VERSION 5.7 ;
  NOWIREEXTENSIONATPIN ON ;
  DIVIDERCHAR "/" ;
  BUSBITCHARS "[]" ;
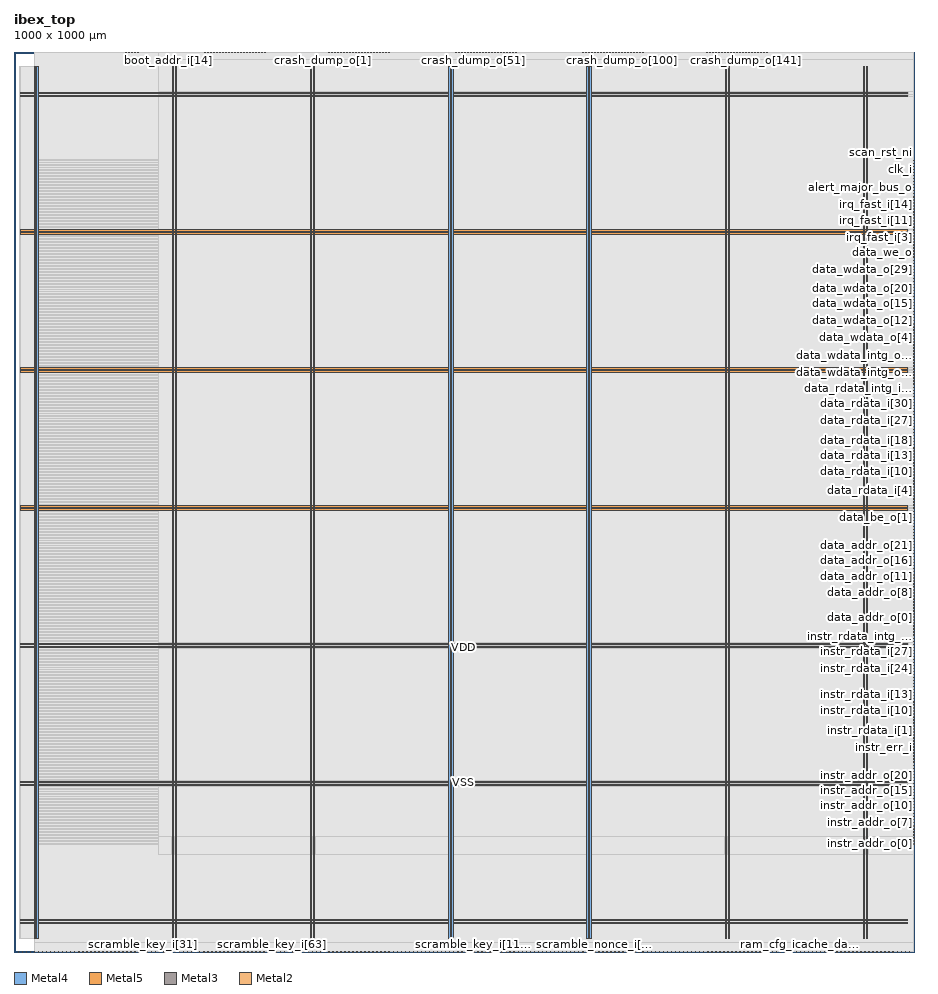
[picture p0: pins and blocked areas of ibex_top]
MACRO ibex_top
  CLASS BLOCK ;
  FOREIGN ibex_top ;
  ORIGIN 0.000 0.000 ;
  SIZE 1000.000 BY 1000.000 ;
  PIN VDD
    DIRECTION INOUT ;
    USE POWER ;
    PORT
      LAYER Metal4 ;
        RECT 22.240 15.380 23.840 984.220 ;
    END
    PORT
      LAYER Metal4 ;
        RECT 175.840 15.380 177.440 984.220 ;
    END
    PORT
      LAYER Metal4 ;
        RECT 329.440 15.380 331.040 984.220 ;
    END
    PORT
      LAYER Metal4 ;
        RECT 483.040 15.380 484.640 984.220 ;
    END
    PORT
      LAYER Metal4 ;
        RECT 636.640 15.380 638.240 984.220 ;
    END
    PORT
      LAYER Metal4 ;
        RECT 790.240 15.380 791.840 984.220 ;
    END
    PORT
      LAYER Metal4 ;
        RECT 943.840 15.380 945.440 984.220 ;
    END
    PORT
      LAYER Metal5 ;
        RECT 6.720 31.530 992.880 33.130 ;
    END
    PORT
      LAYER Metal5 ;
        RECT 6.720 184.710 992.880 186.310 ;
    END
    PORT
      LAYER Metal5 ;
        RECT 6.720 337.890 992.880 339.490 ;
    END
    PORT
      LAYER Metal5 ;
        RECT 6.720 491.070 992.880 492.670 ;
    END
    PORT
      LAYER Metal5 ;
        RECT 6.720 644.250 992.880 645.850 ;
    END
    PORT
      LAYER Metal5 ;
        RECT 6.720 797.430 992.880 799.030 ;
    END
    PORT
      LAYER Metal5 ;
        RECT 6.720 950.610 992.880 952.210 ;
    END
  END VDD
  PIN VSS
    DIRECTION INOUT ;
    USE GROUND ;
    PORT
      LAYER Metal4 ;
        RECT 25.540 15.380 27.140 984.220 ;
    END
    PORT
      LAYER Metal4 ;
        RECT 179.140 15.380 180.740 984.220 ;
    END
    PORT
      LAYER Metal4 ;
        RECT 332.740 15.380 334.340 984.220 ;
    END
    PORT
      LAYER Metal4 ;
        RECT 486.340 15.380 487.940 984.220 ;
    END
    PORT
      LAYER Metal4 ;
        RECT 639.940 15.380 641.540 984.220 ;
    END
    PORT
      LAYER Metal4 ;
        RECT 793.540 15.380 795.140 984.220 ;
    END
    PORT
      LAYER Metal4 ;
        RECT 947.140 15.380 948.740 984.220 ;
    END
    PORT
      LAYER Metal5 ;
        RECT 6.720 34.830 992.880 36.430 ;
    END
    PORT
      LAYER Metal5 ;
        RECT 6.720 188.010 992.880 189.610 ;
    END
    PORT
      LAYER Metal5 ;
        RECT 6.720 341.190 992.880 342.790 ;
    END
    PORT
      LAYER Metal5 ;
        RECT 6.720 494.370 992.880 495.970 ;
    END
    PORT
      LAYER Metal5 ;
        RECT 6.720 647.550 992.880 649.150 ;
    END
    PORT
      LAYER Metal5 ;
        RECT 6.720 800.730 992.880 802.330 ;
    END
    PORT
      LAYER Metal5 ;
        RECT 6.720 953.910 992.880 955.510 ;
    END
  END VSS
  PIN alert_major_bus_o
    DIRECTION OUTPUT ;
    USE SIGNAL ;
    ANTENNADIFFAREA 0.360800 ;
    PORT
      LAYER Metal3 ;
        RECT 999.440 848.960 1000.000 849.520 ;
    END
  END alert_major_bus_o
  PIN alert_major_internal_o
    DIRECTION OUTPUT ;
    USE SIGNAL ;
    ANTENNADIFFAREA 0.360800 ;
    PORT
      LAYER Metal3 ;
        RECT 999.440 852.320 1000.000 852.880 ;
    END
  END alert_major_internal_o
  PIN alert_minor_o
    DIRECTION OUTPUT ;
    USE SIGNAL ;
    ANTENNADIFFAREA 0.360800 ;
    PORT
      LAYER Metal3 ;
        RECT 999.440 855.680 1000.000 856.240 ;
    END
  END alert_minor_o
  PIN boot_addr_i[0]
    DIRECTION INPUT ;
    USE SIGNAL ;
    PORT
      LAYER Metal2 ;
        RECT 124.320 999.440 124.880 1000.000 ;
    END
  END boot_addr_i[0]
  PIN boot_addr_i[10]
    DIRECTION INPUT ;
    USE SIGNAL ;
    ANTENNAGATEAREA 0.396000 ;
    ANTENNADIFFAREA 0.410400 ;
    PORT
      LAYER Metal2 ;
        RECT 157.920 999.440 158.480 1000.000 ;
    END
  END boot_addr_i[10]
  PIN boot_addr_i[11]
    DIRECTION INPUT ;
    USE SIGNAL ;
    ANTENNAGATEAREA 0.396000 ;
    ANTENNADIFFAREA 0.410400 ;
    PORT
      LAYER Metal2 ;
        RECT 161.280 999.440 161.840 1000.000 ;
    END
  END boot_addr_i[11]
  PIN boot_addr_i[12]
    DIRECTION INPUT ;
    USE SIGNAL ;
    ANTENNAGATEAREA 0.396000 ;
    ANTENNADIFFAREA 0.410400 ;
    PORT
      LAYER Metal2 ;
        RECT 164.640 999.440 165.200 1000.000 ;
    END
  END boot_addr_i[12]
  PIN boot_addr_i[13]
    DIRECTION INPUT ;
    USE SIGNAL ;
    ANTENNAGATEAREA 0.396000 ;
    ANTENNADIFFAREA 0.410400 ;
    PORT
      LAYER Metal2 ;
        RECT 168.000 999.440 168.560 1000.000 ;
    END
  END boot_addr_i[13]
  PIN boot_addr_i[14]
    DIRECTION INPUT ;
    USE SIGNAL ;
    ANTENNAGATEAREA 0.396000 ;
    ANTENNADIFFAREA 0.410400 ;
    PORT
      LAYER Metal2 ;
        RECT 171.360 999.440 171.920 1000.000 ;
    END
  END boot_addr_i[14]
  PIN boot_addr_i[15]
    DIRECTION INPUT ;
    USE SIGNAL ;
    ANTENNAGATEAREA 0.396000 ;
    ANTENNADIFFAREA 0.410400 ;
    PORT
      LAYER Metal2 ;
        RECT 174.720 999.440 175.280 1000.000 ;
    END
  END boot_addr_i[15]
  PIN boot_addr_i[16]
    DIRECTION INPUT ;
    USE SIGNAL ;
    ANTENNAGATEAREA 0.396000 ;
    ANTENNADIFFAREA 0.410400 ;
    PORT
      LAYER Metal2 ;
        RECT 178.080 999.440 178.640 1000.000 ;
    END
  END boot_addr_i[16]
  PIN boot_addr_i[17]
    DIRECTION INPUT ;
    USE SIGNAL ;
    ANTENNAGATEAREA 0.396000 ;
    ANTENNADIFFAREA 0.410400 ;
    PORT
      LAYER Metal2 ;
        RECT 181.440 999.440 182.000 1000.000 ;
    END
  END boot_addr_i[17]
  PIN boot_addr_i[18]
    DIRECTION INPUT ;
    USE SIGNAL ;
    ANTENNAGATEAREA 0.396000 ;
    ANTENNADIFFAREA 0.410400 ;
    PORT
      LAYER Metal2 ;
        RECT 184.800 999.440 185.360 1000.000 ;
    END
  END boot_addr_i[18]
  PIN boot_addr_i[19]
    DIRECTION INPUT ;
    USE SIGNAL ;
    ANTENNAGATEAREA 0.396000 ;
    ANTENNADIFFAREA 0.410400 ;
    PORT
      LAYER Metal2 ;
        RECT 188.160 999.440 188.720 1000.000 ;
    END
  END boot_addr_i[19]
  PIN boot_addr_i[1]
    DIRECTION INPUT ;
    USE SIGNAL ;
    PORT
      LAYER Metal2 ;
        RECT 127.680 999.440 128.240 1000.000 ;
    END
  END boot_addr_i[1]
  PIN boot_addr_i[20]
    DIRECTION INPUT ;
    USE SIGNAL ;
    ANTENNAGATEAREA 0.396000 ;
    ANTENNADIFFAREA 0.410400 ;
    PORT
      LAYER Metal2 ;
        RECT 191.520 999.440 192.080 1000.000 ;
    END
  END boot_addr_i[20]
  PIN boot_addr_i[21]
    DIRECTION INPUT ;
    USE SIGNAL ;
    ANTENNAGATEAREA 0.396000 ;
    ANTENNADIFFAREA 0.410400 ;
    PORT
      LAYER Metal2 ;
        RECT 194.880 999.440 195.440 1000.000 ;
    END
  END boot_addr_i[21]
  PIN boot_addr_i[22]
    DIRECTION INPUT ;
    USE SIGNAL ;
    ANTENNAGATEAREA 0.396000 ;
    ANTENNADIFFAREA 0.410400 ;
    PORT
      LAYER Metal2 ;
        RECT 198.240 999.440 198.800 1000.000 ;
    END
  END boot_addr_i[22]
  PIN boot_addr_i[23]
    DIRECTION INPUT ;
    USE SIGNAL ;
    ANTENNAGATEAREA 0.396000 ;
    ANTENNADIFFAREA 0.410400 ;
    PORT
      LAYER Metal2 ;
        RECT 201.600 999.440 202.160 1000.000 ;
    END
  END boot_addr_i[23]
  PIN boot_addr_i[24]
    DIRECTION INPUT ;
    USE SIGNAL ;
    ANTENNAGATEAREA 0.396000 ;
    ANTENNADIFFAREA 0.410400 ;
    PORT
      LAYER Metal2 ;
        RECT 204.960 999.440 205.520 1000.000 ;
    END
  END boot_addr_i[24]
  PIN boot_addr_i[25]
    DIRECTION INPUT ;
    USE SIGNAL ;
    ANTENNAGATEAREA 0.396000 ;
    ANTENNADIFFAREA 0.410400 ;
    PORT
      LAYER Metal2 ;
        RECT 208.320 999.440 208.880 1000.000 ;
    END
  END boot_addr_i[25]
  PIN boot_addr_i[26]
    DIRECTION INPUT ;
    USE SIGNAL ;
    ANTENNAGATEAREA 0.396000 ;
    ANTENNADIFFAREA 0.410400 ;
    PORT
      LAYER Metal2 ;
        RECT 211.680 999.440 212.240 1000.000 ;
    END
  END boot_addr_i[26]
  PIN boot_addr_i[27]
    DIRECTION INPUT ;
    USE SIGNAL ;
    ANTENNAGATEAREA 0.396000 ;
    ANTENNADIFFAREA 0.410400 ;
    PORT
      LAYER Metal2 ;
        RECT 215.040 999.440 215.600 1000.000 ;
    END
  END boot_addr_i[27]
  PIN boot_addr_i[28]
    DIRECTION INPUT ;
    USE SIGNAL ;
    ANTENNAGATEAREA 0.396000 ;
    ANTENNADIFFAREA 0.410400 ;
    PORT
      LAYER Metal2 ;
        RECT 218.400 999.440 218.960 1000.000 ;
    END
  END boot_addr_i[28]
  PIN boot_addr_i[29]
    DIRECTION INPUT ;
    USE SIGNAL ;
    ANTENNAGATEAREA 0.396000 ;
    ANTENNADIFFAREA 0.410400 ;
    PORT
      LAYER Metal2 ;
        RECT 221.760 999.440 222.320 1000.000 ;
    END
  END boot_addr_i[29]
  PIN boot_addr_i[2]
    DIRECTION INPUT ;
    USE SIGNAL ;
    PORT
      LAYER Metal2 ;
        RECT 131.040 999.440 131.600 1000.000 ;
    END
  END boot_addr_i[2]
  PIN boot_addr_i[30]
    DIRECTION INPUT ;
    USE SIGNAL ;
    ANTENNAGATEAREA 0.396000 ;
    ANTENNADIFFAREA 0.410400 ;
    PORT
      LAYER Metal2 ;
        RECT 225.120 999.440 225.680 1000.000 ;
    END
  END boot_addr_i[30]
  PIN boot_addr_i[31]
    DIRECTION INPUT ;
    USE SIGNAL ;
    ANTENNAGATEAREA 0.396000 ;
    ANTENNADIFFAREA 0.410400 ;
    PORT
      LAYER Metal2 ;
        RECT 228.480 999.440 229.040 1000.000 ;
    END
  END boot_addr_i[31]
  PIN boot_addr_i[3]
    DIRECTION INPUT ;
    USE SIGNAL ;
    PORT
      LAYER Metal2 ;
        RECT 134.400 999.440 134.960 1000.000 ;
    END
  END boot_addr_i[3]
  PIN boot_addr_i[4]
    DIRECTION INPUT ;
    USE SIGNAL ;
    PORT
      LAYER Metal2 ;
        RECT 137.760 999.440 138.320 1000.000 ;
    END
  END boot_addr_i[4]
  PIN boot_addr_i[5]
    DIRECTION INPUT ;
    USE SIGNAL ;
    PORT
      LAYER Metal2 ;
        RECT 141.120 999.440 141.680 1000.000 ;
    END
  END boot_addr_i[5]
  PIN boot_addr_i[6]
    DIRECTION INPUT ;
    USE SIGNAL ;
    PORT
      LAYER Metal2 ;
        RECT 144.480 999.440 145.040 1000.000 ;
    END
  END boot_addr_i[6]
  PIN boot_addr_i[7]
    DIRECTION INPUT ;
    USE SIGNAL ;
    PORT
      LAYER Metal2 ;
        RECT 147.840 999.440 148.400 1000.000 ;
    END
  END boot_addr_i[7]
  PIN boot_addr_i[8]
    DIRECTION INPUT ;
    USE SIGNAL ;
    ANTENNAGATEAREA 0.396000 ;
    ANTENNADIFFAREA 0.410400 ;
    PORT
      LAYER Metal2 ;
        RECT 151.200 999.440 151.760 1000.000 ;
    END
  END boot_addr_i[8]
  PIN boot_addr_i[9]
    DIRECTION INPUT ;
    USE SIGNAL ;
    ANTENNAGATEAREA 0.396000 ;
    ANTENNADIFFAREA 0.410400 ;
    PORT
      LAYER Metal2 ;
        RECT 154.560 999.440 155.120 1000.000 ;
    END
  END boot_addr_i[9]
  PIN clk_i
    DIRECTION INPUT ;
    USE SIGNAL ;
    ANTENNAGATEAREA 9.476000 ;
    ANTENNADIFFAREA 0.820800 ;
    PORT
      LAYER Metal3 ;
        RECT 999.440 869.120 1000.000 869.680 ;
    END
  END clk_i
  PIN core_sleep_o
    DIRECTION OUTPUT ;
    USE SIGNAL ;
    ANTENNADIFFAREA 0.897600 ;
    PORT
      LAYER Metal3 ;
        RECT 999.440 859.040 1000.000 859.600 ;
    END
  END core_sleep_o
  PIN crash_dump_o[0]
    DIRECTION OUTPUT ;
    USE SIGNAL ;
    ANTENNADIFFAREA 0.897600 ;
    PORT
      LAYER Metal2 ;
        RECT 339.360 999.440 339.920 1000.000 ;
    END
  END crash_dump_o[0]
  PIN crash_dump_o[100]
    DIRECTION OUTPUT ;
    USE SIGNAL ;
    ANTENNADIFFAREA 0.897600 ;
    PORT
      LAYER Metal2 ;
        RECT 675.360 999.440 675.920 1000.000 ;
    END
  END crash_dump_o[100]
  PIN crash_dump_o[101]
    DIRECTION OUTPUT ;
    USE SIGNAL ;
    ANTENNADIFFAREA 0.897600 ;
    PORT
      LAYER Metal2 ;
        RECT 678.720 999.440 679.280 1000.000 ;
    END
  END crash_dump_o[101]
  PIN crash_dump_o[102]
    DIRECTION OUTPUT ;
    USE SIGNAL ;
    ANTENNADIFFAREA 0.897600 ;
    PORT
      LAYER Metal2 ;
        RECT 682.080 999.440 682.640 1000.000 ;
    END
  END crash_dump_o[102]
  PIN crash_dump_o[103]
    DIRECTION OUTPUT ;
    USE SIGNAL ;
    ANTENNADIFFAREA 0.897600 ;
    PORT
      LAYER Metal2 ;
        RECT 685.440 999.440 686.000 1000.000 ;
    END
  END crash_dump_o[103]
  PIN crash_dump_o[104]
    DIRECTION OUTPUT ;
    USE SIGNAL ;
    ANTENNADIFFAREA 0.897600 ;
    PORT
      LAYER Metal2 ;
        RECT 688.800 999.440 689.360 1000.000 ;
    END
  END crash_dump_o[104]
  PIN crash_dump_o[105]
    DIRECTION OUTPUT ;
    USE SIGNAL ;
    ANTENNADIFFAREA 0.897600 ;
    PORT
      LAYER Metal2 ;
        RECT 692.160 999.440 692.720 1000.000 ;
    END
  END crash_dump_o[105]
  PIN crash_dump_o[106]
    DIRECTION OUTPUT ;
    USE SIGNAL ;
    ANTENNADIFFAREA 0.897600 ;
    PORT
      LAYER Metal2 ;
        RECT 695.520 999.440 696.080 1000.000 ;
    END
  END crash_dump_o[106]
  PIN crash_dump_o[107]
    DIRECTION OUTPUT ;
    USE SIGNAL ;
    ANTENNADIFFAREA 0.897600 ;
    PORT
      LAYER Metal2 ;
        RECT 698.880 999.440 699.440 1000.000 ;
    END
  END crash_dump_o[107]
  PIN crash_dump_o[108]
    DIRECTION OUTPUT ;
    USE SIGNAL ;
    ANTENNADIFFAREA 0.897600 ;
    PORT
      LAYER Metal2 ;
        RECT 702.240 999.440 702.800 1000.000 ;
    END
  END crash_dump_o[108]
  PIN crash_dump_o[109]
    DIRECTION OUTPUT ;
    USE SIGNAL ;
    ANTENNADIFFAREA 0.897600 ;
    PORT
      LAYER Metal2 ;
        RECT 705.600 999.440 706.160 1000.000 ;
    END
  END crash_dump_o[109]
  PIN crash_dump_o[10]
    DIRECTION OUTPUT ;
    USE SIGNAL ;
    ANTENNADIFFAREA 0.897600 ;
    PORT
      LAYER Metal2 ;
        RECT 372.960 999.440 373.520 1000.000 ;
    END
  END crash_dump_o[10]
  PIN crash_dump_o[110]
    DIRECTION OUTPUT ;
    USE SIGNAL ;
    ANTENNADIFFAREA 0.897600 ;
    PORT
      LAYER Metal2 ;
        RECT 708.960 999.440 709.520 1000.000 ;
    END
  END crash_dump_o[110]
  PIN crash_dump_o[111]
    DIRECTION OUTPUT ;
    USE SIGNAL ;
    ANTENNADIFFAREA 0.897600 ;
    PORT
      LAYER Metal2 ;
        RECT 712.320 999.440 712.880 1000.000 ;
    END
  END crash_dump_o[111]
  PIN crash_dump_o[112]
    DIRECTION OUTPUT ;
    USE SIGNAL ;
    ANTENNADIFFAREA 0.897600 ;
    PORT
      LAYER Metal2 ;
        RECT 715.680 999.440 716.240 1000.000 ;
    END
  END crash_dump_o[112]
  PIN crash_dump_o[113]
    DIRECTION OUTPUT ;
    USE SIGNAL ;
    ANTENNADIFFAREA 0.897600 ;
    PORT
      LAYER Metal2 ;
        RECT 719.040 999.440 719.600 1000.000 ;
    END
  END crash_dump_o[113]
  PIN crash_dump_o[114]
    DIRECTION OUTPUT ;
    USE SIGNAL ;
    ANTENNADIFFAREA 0.897600 ;
    PORT
      LAYER Metal2 ;
        RECT 722.400 999.440 722.960 1000.000 ;
    END
  END crash_dump_o[114]
  PIN crash_dump_o[115]
    DIRECTION OUTPUT ;
    USE SIGNAL ;
    ANTENNADIFFAREA 0.897600 ;
    PORT
      LAYER Metal2 ;
        RECT 725.760 999.440 726.320 1000.000 ;
    END
  END crash_dump_o[115]
  PIN crash_dump_o[116]
    DIRECTION OUTPUT ;
    USE SIGNAL ;
    ANTENNADIFFAREA 0.897600 ;
    PORT
      LAYER Metal2 ;
        RECT 729.120 999.440 729.680 1000.000 ;
    END
  END crash_dump_o[116]
  PIN crash_dump_o[117]
    DIRECTION OUTPUT ;
    USE SIGNAL ;
    ANTENNADIFFAREA 0.897600 ;
    PORT
      LAYER Metal2 ;
        RECT 732.480 999.440 733.040 1000.000 ;
    END
  END crash_dump_o[117]
  PIN crash_dump_o[118]
    DIRECTION OUTPUT ;
    USE SIGNAL ;
    ANTENNADIFFAREA 0.897600 ;
    PORT
      LAYER Metal2 ;
        RECT 735.840 999.440 736.400 1000.000 ;
    END
  END crash_dump_o[118]
  PIN crash_dump_o[119]
    DIRECTION OUTPUT ;
    USE SIGNAL ;
    ANTENNADIFFAREA 0.897600 ;
    PORT
      LAYER Metal2 ;
        RECT 739.200 999.440 739.760 1000.000 ;
    END
  END crash_dump_o[119]
  PIN crash_dump_o[11]
    DIRECTION OUTPUT ;
    USE SIGNAL ;
    ANTENNADIFFAREA 0.897600 ;
    PORT
      LAYER Metal2 ;
        RECT 376.320 999.440 376.880 1000.000 ;
    END
  END crash_dump_o[11]
  PIN crash_dump_o[120]
    DIRECTION OUTPUT ;
    USE SIGNAL ;
    ANTENNADIFFAREA 0.897600 ;
    PORT
      LAYER Metal2 ;
        RECT 742.560 999.440 743.120 1000.000 ;
    END
  END crash_dump_o[120]
  PIN crash_dump_o[121]
    DIRECTION OUTPUT ;
    USE SIGNAL ;
    ANTENNADIFFAREA 0.897600 ;
    PORT
      LAYER Metal2 ;
        RECT 745.920 999.440 746.480 1000.000 ;
    END
  END crash_dump_o[121]
  PIN crash_dump_o[122]
    DIRECTION OUTPUT ;
    USE SIGNAL ;
    ANTENNADIFFAREA 0.897600 ;
    PORT
      LAYER Metal2 ;
        RECT 749.280 999.440 749.840 1000.000 ;
    END
  END crash_dump_o[122]
  PIN crash_dump_o[123]
    DIRECTION OUTPUT ;
    USE SIGNAL ;
    ANTENNADIFFAREA 0.897600 ;
    PORT
      LAYER Metal2 ;
        RECT 752.640 999.440 753.200 1000.000 ;
    END
  END crash_dump_o[123]
  PIN crash_dump_o[124]
    DIRECTION OUTPUT ;
    USE SIGNAL ;
    ANTENNADIFFAREA 0.897600 ;
    PORT
      LAYER Metal2 ;
        RECT 756.000 999.440 756.560 1000.000 ;
    END
  END crash_dump_o[124]
  PIN crash_dump_o[125]
    DIRECTION OUTPUT ;
    USE SIGNAL ;
    ANTENNADIFFAREA 0.897600 ;
    PORT
      LAYER Metal2 ;
        RECT 759.360 999.440 759.920 1000.000 ;
    END
  END crash_dump_o[125]
  PIN crash_dump_o[126]
    DIRECTION OUTPUT ;
    USE SIGNAL ;
    ANTENNADIFFAREA 0.897600 ;
    PORT
      LAYER Metal2 ;
        RECT 762.720 999.440 763.280 1000.000 ;
    END
  END crash_dump_o[126]
  PIN crash_dump_o[127]
    DIRECTION OUTPUT ;
    USE SIGNAL ;
    ANTENNADIFFAREA 0.897600 ;
    PORT
      LAYER Metal2 ;
        RECT 766.080 999.440 766.640 1000.000 ;
    END
  END crash_dump_o[127]
  PIN crash_dump_o[128]
    DIRECTION OUTPUT ;
    USE SIGNAL ;
    ANTENNADIFFAREA 0.360800 ;
    PORT
      LAYER Metal2 ;
        RECT 769.440 999.440 770.000 1000.000 ;
    END
  END crash_dump_o[128]
  PIN crash_dump_o[129]
    DIRECTION OUTPUT ;
    USE SIGNAL ;
    ANTENNADIFFAREA 0.897600 ;
    PORT
      LAYER Metal2 ;
        RECT 772.800 999.440 773.360 1000.000 ;
    END
  END crash_dump_o[129]
  PIN crash_dump_o[12]
    DIRECTION OUTPUT ;
    USE SIGNAL ;
    ANTENNADIFFAREA 0.897600 ;
    PORT
      LAYER Metal2 ;
        RECT 379.680 999.440 380.240 1000.000 ;
    END
  END crash_dump_o[12]
  PIN crash_dump_o[130]
    DIRECTION OUTPUT ;
    USE SIGNAL ;
    ANTENNADIFFAREA 0.897600 ;
    PORT
      LAYER Metal2 ;
        RECT 776.160 999.440 776.720 1000.000 ;
    END
  END crash_dump_o[130]
  PIN crash_dump_o[131]
    DIRECTION OUTPUT ;
    USE SIGNAL ;
    ANTENNADIFFAREA 0.897600 ;
    PORT
      LAYER Metal2 ;
        RECT 779.520 999.440 780.080 1000.000 ;
    END
  END crash_dump_o[131]
  PIN crash_dump_o[132]
    DIRECTION OUTPUT ;
    USE SIGNAL ;
    ANTENNADIFFAREA 0.897600 ;
    PORT
      LAYER Metal2 ;
        RECT 782.880 999.440 783.440 1000.000 ;
    END
  END crash_dump_o[132]
  PIN crash_dump_o[133]
    DIRECTION OUTPUT ;
    USE SIGNAL ;
    ANTENNADIFFAREA 0.897600 ;
    PORT
      LAYER Metal2 ;
        RECT 786.240 999.440 786.800 1000.000 ;
    END
  END crash_dump_o[133]
  PIN crash_dump_o[134]
    DIRECTION OUTPUT ;
    USE SIGNAL ;
    ANTENNADIFFAREA 0.897600 ;
    PORT
      LAYER Metal2 ;
        RECT 789.600 999.440 790.160 1000.000 ;
    END
  END crash_dump_o[134]
  PIN crash_dump_o[135]
    DIRECTION OUTPUT ;
    USE SIGNAL ;
    ANTENNADIFFAREA 0.897600 ;
    PORT
      LAYER Metal2 ;
        RECT 792.960 999.440 793.520 1000.000 ;
    END
  END crash_dump_o[135]
  PIN crash_dump_o[136]
    DIRECTION OUTPUT ;
    USE SIGNAL ;
    ANTENNADIFFAREA 0.897600 ;
    PORT
      LAYER Metal2 ;
        RECT 796.320 999.440 796.880 1000.000 ;
    END
  END crash_dump_o[136]
  PIN crash_dump_o[137]
    DIRECTION OUTPUT ;
    USE SIGNAL ;
    ANTENNADIFFAREA 0.897600 ;
    PORT
      LAYER Metal2 ;
        RECT 799.680 999.440 800.240 1000.000 ;
    END
  END crash_dump_o[137]
  PIN crash_dump_o[138]
    DIRECTION OUTPUT ;
    USE SIGNAL ;
    ANTENNADIFFAREA 0.897600 ;
    PORT
      LAYER Metal2 ;
        RECT 803.040 999.440 803.600 1000.000 ;
    END
  END crash_dump_o[138]
  PIN crash_dump_o[139]
    DIRECTION OUTPUT ;
    USE SIGNAL ;
    ANTENNADIFFAREA 0.897600 ;
    PORT
      LAYER Metal2 ;
        RECT 806.400 999.440 806.960 1000.000 ;
    END
  END crash_dump_o[139]
  PIN crash_dump_o[13]
    DIRECTION OUTPUT ;
    USE SIGNAL ;
    ANTENNADIFFAREA 0.897600 ;
    PORT
      LAYER Metal2 ;
        RECT 383.040 999.440 383.600 1000.000 ;
    END
  END crash_dump_o[13]
  PIN crash_dump_o[140]
    DIRECTION OUTPUT ;
    USE SIGNAL ;
    ANTENNADIFFAREA 0.897600 ;
    PORT
      LAYER Metal2 ;
        RECT 809.760 999.440 810.320 1000.000 ;
    END
  END crash_dump_o[140]
  PIN crash_dump_o[141]
    DIRECTION OUTPUT ;
    USE SIGNAL ;
    ANTENNADIFFAREA 0.897600 ;
    PORT
      LAYER Metal2 ;
        RECT 813.120 999.440 813.680 1000.000 ;
    END
  END crash_dump_o[141]
  PIN crash_dump_o[142]
    DIRECTION OUTPUT ;
    USE SIGNAL ;
    ANTENNADIFFAREA 0.897600 ;
    PORT
      LAYER Metal2 ;
        RECT 816.480 999.440 817.040 1000.000 ;
    END
  END crash_dump_o[142]
  PIN crash_dump_o[143]
    DIRECTION OUTPUT ;
    USE SIGNAL ;
    ANTENNADIFFAREA 0.897600 ;
    PORT
      LAYER Metal2 ;
        RECT 819.840 999.440 820.400 1000.000 ;
    END
  END crash_dump_o[143]
  PIN crash_dump_o[144]
    DIRECTION OUTPUT ;
    USE SIGNAL ;
    ANTENNADIFFAREA 0.897600 ;
    PORT
      LAYER Metal2 ;
        RECT 823.200 999.440 823.760 1000.000 ;
    END
  END crash_dump_o[144]
  PIN crash_dump_o[145]
    DIRECTION OUTPUT ;
    USE SIGNAL ;
    ANTENNADIFFAREA 0.897600 ;
    PORT
      LAYER Metal2 ;
        RECT 826.560 999.440 827.120 1000.000 ;
    END
  END crash_dump_o[145]
  PIN crash_dump_o[146]
    DIRECTION OUTPUT ;
    USE SIGNAL ;
    ANTENNADIFFAREA 0.897600 ;
    PORT
      LAYER Metal2 ;
        RECT 829.920 999.440 830.480 1000.000 ;
    END
  END crash_dump_o[146]
  PIN crash_dump_o[147]
    DIRECTION OUTPUT ;
    USE SIGNAL ;
    ANTENNADIFFAREA 0.897600 ;
    PORT
      LAYER Metal2 ;
        RECT 833.280 999.440 833.840 1000.000 ;
    END
  END crash_dump_o[147]
  PIN crash_dump_o[148]
    DIRECTION OUTPUT ;
    USE SIGNAL ;
    ANTENNADIFFAREA 0.897600 ;
    PORT
      LAYER Metal2 ;
        RECT 836.640 999.440 837.200 1000.000 ;
    END
  END crash_dump_o[148]
  PIN crash_dump_o[149]
    DIRECTION OUTPUT ;
    USE SIGNAL ;
    ANTENNADIFFAREA 0.897600 ;
    PORT
      LAYER Metal2 ;
        RECT 840.000 999.440 840.560 1000.000 ;
    END
  END crash_dump_o[149]
  PIN crash_dump_o[14]
    DIRECTION OUTPUT ;
    USE SIGNAL ;
    ANTENNADIFFAREA 0.897600 ;
    PORT
      LAYER Metal2 ;
        RECT 386.400 999.440 386.960 1000.000 ;
    END
  END crash_dump_o[14]
  PIN crash_dump_o[150]
    DIRECTION OUTPUT ;
    USE SIGNAL ;
    ANTENNADIFFAREA 0.897600 ;
    PORT
      LAYER Metal2 ;
        RECT 843.360 999.440 843.920 1000.000 ;
    END
  END crash_dump_o[150]
  PIN crash_dump_o[151]
    DIRECTION OUTPUT ;
    USE SIGNAL ;
    ANTENNADIFFAREA 0.897600 ;
    PORT
      LAYER Metal2 ;
        RECT 846.720 999.440 847.280 1000.000 ;
    END
  END crash_dump_o[151]
  PIN crash_dump_o[152]
    DIRECTION OUTPUT ;
    USE SIGNAL ;
    ANTENNADIFFAREA 0.897600 ;
    PORT
      LAYER Metal2 ;
        RECT 850.080 999.440 850.640 1000.000 ;
    END
  END crash_dump_o[152]
  PIN crash_dump_o[153]
    DIRECTION OUTPUT ;
    USE SIGNAL ;
    ANTENNADIFFAREA 0.897600 ;
    PORT
      LAYER Metal2 ;
        RECT 853.440 999.440 854.000 1000.000 ;
    END
  END crash_dump_o[153]
  PIN crash_dump_o[154]
    DIRECTION OUTPUT ;
    USE SIGNAL ;
    ANTENNADIFFAREA 0.897600 ;
    PORT
      LAYER Metal2 ;
        RECT 856.800 999.440 857.360 1000.000 ;
    END
  END crash_dump_o[154]
  PIN crash_dump_o[155]
    DIRECTION OUTPUT ;
    USE SIGNAL ;
    ANTENNADIFFAREA 0.897600 ;
    PORT
      LAYER Metal2 ;
        RECT 860.160 999.440 860.720 1000.000 ;
    END
  END crash_dump_o[155]
  PIN crash_dump_o[156]
    DIRECTION OUTPUT ;
    USE SIGNAL ;
    ANTENNADIFFAREA 0.897600 ;
    PORT
      LAYER Metal2 ;
        RECT 863.520 999.440 864.080 1000.000 ;
    END
  END crash_dump_o[156]
  PIN crash_dump_o[157]
    DIRECTION OUTPUT ;
    USE SIGNAL ;
    ANTENNADIFFAREA 0.897600 ;
    PORT
      LAYER Metal2 ;
        RECT 866.880 999.440 867.440 1000.000 ;
    END
  END crash_dump_o[157]
  PIN crash_dump_o[158]
    DIRECTION OUTPUT ;
    USE SIGNAL ;
    ANTENNADIFFAREA 0.897600 ;
    PORT
      LAYER Metal2 ;
        RECT 870.240 999.440 870.800 1000.000 ;
    END
  END crash_dump_o[158]
  PIN crash_dump_o[159]
    DIRECTION OUTPUT ;
    USE SIGNAL ;
    ANTENNADIFFAREA 0.897600 ;
    PORT
      LAYER Metal2 ;
        RECT 873.600 999.440 874.160 1000.000 ;
    END
  END crash_dump_o[159]
  PIN crash_dump_o[15]
    DIRECTION OUTPUT ;
    USE SIGNAL ;
    ANTENNADIFFAREA 0.897600 ;
    PORT
      LAYER Metal2 ;
        RECT 389.760 999.440 390.320 1000.000 ;
    END
  END crash_dump_o[15]
  PIN crash_dump_o[16]
    DIRECTION OUTPUT ;
    USE SIGNAL ;
    ANTENNADIFFAREA 0.897600 ;
    PORT
      LAYER Metal2 ;
        RECT 393.120 999.440 393.680 1000.000 ;
    END
  END crash_dump_o[16]
  PIN crash_dump_o[17]
    DIRECTION OUTPUT ;
    USE SIGNAL ;
    ANTENNADIFFAREA 0.897600 ;
    PORT
      LAYER Metal2 ;
        RECT 396.480 999.440 397.040 1000.000 ;
    END
  END crash_dump_o[17]
  PIN crash_dump_o[18]
    DIRECTION OUTPUT ;
    USE SIGNAL ;
    ANTENNADIFFAREA 0.897600 ;
    PORT
      LAYER Metal2 ;
        RECT 399.840 999.440 400.400 1000.000 ;
    END
  END crash_dump_o[18]
  PIN crash_dump_o[19]
    DIRECTION OUTPUT ;
    USE SIGNAL ;
    ANTENNADIFFAREA 0.897600 ;
    PORT
      LAYER Metal2 ;
        RECT 403.200 999.440 403.760 1000.000 ;
    END
  END crash_dump_o[19]
  PIN crash_dump_o[1]
    DIRECTION OUTPUT ;
    USE SIGNAL ;
    ANTENNADIFFAREA 0.897600 ;
    PORT
      LAYER Metal2 ;
        RECT 342.720 999.440 343.280 1000.000 ;
    END
  END crash_dump_o[1]
  PIN crash_dump_o[20]
    DIRECTION OUTPUT ;
    USE SIGNAL ;
    ANTENNADIFFAREA 0.897600 ;
    PORT
      LAYER Metal2 ;
        RECT 406.560 999.440 407.120 1000.000 ;
    END
  END crash_dump_o[20]
  PIN crash_dump_o[21]
    DIRECTION OUTPUT ;
    USE SIGNAL ;
    ANTENNADIFFAREA 0.897600 ;
    PORT
      LAYER Metal2 ;
        RECT 409.920 999.440 410.480 1000.000 ;
    END
  END crash_dump_o[21]
  PIN crash_dump_o[22]
    DIRECTION OUTPUT ;
    USE SIGNAL ;
    ANTENNADIFFAREA 0.897600 ;
    PORT
      LAYER Metal2 ;
        RECT 413.280 999.440 413.840 1000.000 ;
    END
  END crash_dump_o[22]
  PIN crash_dump_o[23]
    DIRECTION OUTPUT ;
    USE SIGNAL ;
    ANTENNADIFFAREA 0.897600 ;
    PORT
      LAYER Metal2 ;
        RECT 416.640 999.440 417.200 1000.000 ;
    END
  END crash_dump_o[23]
  PIN crash_dump_o[24]
    DIRECTION OUTPUT ;
    USE SIGNAL ;
    ANTENNADIFFAREA 0.897600 ;
    PORT
      LAYER Metal2 ;
        RECT 420.000 999.440 420.560 1000.000 ;
    END
  END crash_dump_o[24]
  PIN crash_dump_o[25]
    DIRECTION OUTPUT ;
    USE SIGNAL ;
    ANTENNADIFFAREA 0.897600 ;
    PORT
      LAYER Metal2 ;
        RECT 423.360 999.440 423.920 1000.000 ;
    END
  END crash_dump_o[25]
  PIN crash_dump_o[26]
    DIRECTION OUTPUT ;
    USE SIGNAL ;
    ANTENNADIFFAREA 0.897600 ;
    PORT
      LAYER Metal2 ;
        RECT 426.720 999.440 427.280 1000.000 ;
    END
  END crash_dump_o[26]
  PIN crash_dump_o[27]
    DIRECTION OUTPUT ;
    USE SIGNAL ;
    ANTENNADIFFAREA 0.897600 ;
    PORT
      LAYER Metal2 ;
        RECT 430.080 999.440 430.640 1000.000 ;
    END
  END crash_dump_o[27]
  PIN crash_dump_o[28]
    DIRECTION OUTPUT ;
    USE SIGNAL ;
    ANTENNADIFFAREA 0.897600 ;
    PORT
      LAYER Metal2 ;
        RECT 433.440 999.440 434.000 1000.000 ;
    END
  END crash_dump_o[28]
  PIN crash_dump_o[29]
    DIRECTION OUTPUT ;
    USE SIGNAL ;
    ANTENNADIFFAREA 0.897600 ;
    PORT
      LAYER Metal2 ;
        RECT 436.800 999.440 437.360 1000.000 ;
    END
  END crash_dump_o[29]
  PIN crash_dump_o[2]
    DIRECTION OUTPUT ;
    USE SIGNAL ;
    ANTENNADIFFAREA 0.897600 ;
    PORT
      LAYER Metal2 ;
        RECT 346.080 999.440 346.640 1000.000 ;
    END
  END crash_dump_o[2]
  PIN crash_dump_o[30]
    DIRECTION OUTPUT ;
    USE SIGNAL ;
    ANTENNADIFFAREA 0.897600 ;
    PORT
      LAYER Metal2 ;
        RECT 440.160 999.440 440.720 1000.000 ;
    END
  END crash_dump_o[30]
  PIN crash_dump_o[31]
    DIRECTION OUTPUT ;
    USE SIGNAL ;
    ANTENNADIFFAREA 0.897600 ;
    PORT
      LAYER Metal2 ;
        RECT 443.520 999.440 444.080 1000.000 ;
    END
  END crash_dump_o[31]
  PIN crash_dump_o[32]
    DIRECTION OUTPUT ;
    USE SIGNAL ;
    ANTENNADIFFAREA 0.897600 ;
    PORT
      LAYER Metal2 ;
        RECT 446.880 999.440 447.440 1000.000 ;
    END
  END crash_dump_o[32]
  PIN crash_dump_o[33]
    DIRECTION OUTPUT ;
    USE SIGNAL ;
    ANTENNADIFFAREA 0.897600 ;
    PORT
      LAYER Metal2 ;
        RECT 450.240 999.440 450.800 1000.000 ;
    END
  END crash_dump_o[33]
  PIN crash_dump_o[34]
    DIRECTION OUTPUT ;
    USE SIGNAL ;
    ANTENNADIFFAREA 0.897600 ;
    PORT
      LAYER Metal2 ;
        RECT 453.600 999.440 454.160 1000.000 ;
    END
  END crash_dump_o[34]
  PIN crash_dump_o[35]
    DIRECTION OUTPUT ;
    USE SIGNAL ;
    ANTENNADIFFAREA 0.897600 ;
    PORT
      LAYER Metal2 ;
        RECT 456.960 999.440 457.520 1000.000 ;
    END
  END crash_dump_o[35]
  PIN crash_dump_o[36]
    DIRECTION OUTPUT ;
    USE SIGNAL ;
    ANTENNADIFFAREA 0.897600 ;
    PORT
      LAYER Metal2 ;
        RECT 460.320 999.440 460.880 1000.000 ;
    END
  END crash_dump_o[36]
  PIN crash_dump_o[37]
    DIRECTION OUTPUT ;
    USE SIGNAL ;
    ANTENNADIFFAREA 0.897600 ;
    PORT
      LAYER Metal2 ;
        RECT 463.680 999.440 464.240 1000.000 ;
    END
  END crash_dump_o[37]
  PIN crash_dump_o[38]
    DIRECTION OUTPUT ;
    USE SIGNAL ;
    ANTENNADIFFAREA 0.897600 ;
    PORT
      LAYER Metal2 ;
        RECT 467.040 999.440 467.600 1000.000 ;
    END
  END crash_dump_o[38]
  PIN crash_dump_o[39]
    DIRECTION OUTPUT ;
    USE SIGNAL ;
    ANTENNADIFFAREA 0.897600 ;
    PORT
      LAYER Metal2 ;
        RECT 470.400 999.440 470.960 1000.000 ;
    END
  END crash_dump_o[39]
  PIN crash_dump_o[3]
    DIRECTION OUTPUT ;
    USE SIGNAL ;
    ANTENNADIFFAREA 0.897600 ;
    PORT
      LAYER Metal2 ;
        RECT 349.440 999.440 350.000 1000.000 ;
    END
  END crash_dump_o[3]
  PIN crash_dump_o[40]
    DIRECTION OUTPUT ;
    USE SIGNAL ;
    ANTENNADIFFAREA 0.897600 ;
    PORT
      LAYER Metal2 ;
        RECT 473.760 999.440 474.320 1000.000 ;
    END
  END crash_dump_o[40]
  PIN crash_dump_o[41]
    DIRECTION OUTPUT ;
    USE SIGNAL ;
    ANTENNADIFFAREA 0.897600 ;
    PORT
      LAYER Metal2 ;
        RECT 477.120 999.440 477.680 1000.000 ;
    END
  END crash_dump_o[41]
  PIN crash_dump_o[42]
    DIRECTION OUTPUT ;
    USE SIGNAL ;
    ANTENNADIFFAREA 0.897600 ;
    PORT
      LAYER Metal2 ;
        RECT 480.480 999.440 481.040 1000.000 ;
    END
  END crash_dump_o[42]
  PIN crash_dump_o[43]
    DIRECTION OUTPUT ;
    USE SIGNAL ;
    ANTENNADIFFAREA 0.897600 ;
    PORT
      LAYER Metal2 ;
        RECT 483.840 999.440 484.400 1000.000 ;
    END
  END crash_dump_o[43]
  PIN crash_dump_o[44]
    DIRECTION OUTPUT ;
    USE SIGNAL ;
    ANTENNADIFFAREA 0.897600 ;
    PORT
      LAYER Metal2 ;
        RECT 487.200 999.440 487.760 1000.000 ;
    END
  END crash_dump_o[44]
  PIN crash_dump_o[45]
    DIRECTION OUTPUT ;
    USE SIGNAL ;
    ANTENNADIFFAREA 0.897600 ;
    PORT
      LAYER Metal2 ;
        RECT 490.560 999.440 491.120 1000.000 ;
    END
  END crash_dump_o[45]
  PIN crash_dump_o[46]
    DIRECTION OUTPUT ;
    USE SIGNAL ;
    ANTENNADIFFAREA 0.897600 ;
    PORT
      LAYER Metal2 ;
        RECT 493.920 999.440 494.480 1000.000 ;
    END
  END crash_dump_o[46]
  PIN crash_dump_o[47]
    DIRECTION OUTPUT ;
    USE SIGNAL ;
    ANTENNADIFFAREA 0.897600 ;
    PORT
      LAYER Metal2 ;
        RECT 497.280 999.440 497.840 1000.000 ;
    END
  END crash_dump_o[47]
  PIN crash_dump_o[48]
    DIRECTION OUTPUT ;
    USE SIGNAL ;
    ANTENNADIFFAREA 0.897600 ;
    PORT
      LAYER Metal2 ;
        RECT 500.640 999.440 501.200 1000.000 ;
    END
  END crash_dump_o[48]
  PIN crash_dump_o[49]
    DIRECTION OUTPUT ;
    USE SIGNAL ;
    ANTENNADIFFAREA 0.897600 ;
    PORT
      LAYER Metal2 ;
        RECT 504.000 999.440 504.560 1000.000 ;
    END
  END crash_dump_o[49]
  PIN crash_dump_o[4]
    DIRECTION OUTPUT ;
    USE SIGNAL ;
    ANTENNADIFFAREA 0.897600 ;
    PORT
      LAYER Metal2 ;
        RECT 352.800 999.440 353.360 1000.000 ;
    END
  END crash_dump_o[4]
  PIN crash_dump_o[50]
    DIRECTION OUTPUT ;
    USE SIGNAL ;
    ANTENNADIFFAREA 0.897600 ;
    PORT
      LAYER Metal2 ;
        RECT 507.360 999.440 507.920 1000.000 ;
    END
  END crash_dump_o[50]
  PIN crash_dump_o[51]
    DIRECTION OUTPUT ;
    USE SIGNAL ;
    ANTENNADIFFAREA 0.897600 ;
    PORT
      LAYER Metal2 ;
        RECT 510.720 999.440 511.280 1000.000 ;
    END
  END crash_dump_o[51]
  PIN crash_dump_o[52]
    DIRECTION OUTPUT ;
    USE SIGNAL ;
    ANTENNADIFFAREA 0.897600 ;
    PORT
      LAYER Metal2 ;
        RECT 514.080 999.440 514.640 1000.000 ;
    END
  END crash_dump_o[52]
  PIN crash_dump_o[53]
    DIRECTION OUTPUT ;
    USE SIGNAL ;
    ANTENNADIFFAREA 0.897600 ;
    PORT
      LAYER Metal2 ;
        RECT 517.440 999.440 518.000 1000.000 ;
    END
  END crash_dump_o[53]
  PIN crash_dump_o[54]
    DIRECTION OUTPUT ;
    USE SIGNAL ;
    ANTENNADIFFAREA 0.897600 ;
    PORT
      LAYER Metal2 ;
        RECT 520.800 999.440 521.360 1000.000 ;
    END
  END crash_dump_o[54]
  PIN crash_dump_o[55]
    DIRECTION OUTPUT ;
    USE SIGNAL ;
    ANTENNADIFFAREA 0.897600 ;
    PORT
      LAYER Metal2 ;
        RECT 524.160 999.440 524.720 1000.000 ;
    END
  END crash_dump_o[55]
  PIN crash_dump_o[56]
    DIRECTION OUTPUT ;
    USE SIGNAL ;
    ANTENNADIFFAREA 0.897600 ;
    PORT
      LAYER Metal2 ;
        RECT 527.520 999.440 528.080 1000.000 ;
    END
  END crash_dump_o[56]
  PIN crash_dump_o[57]
    DIRECTION OUTPUT ;
    USE SIGNAL ;
    ANTENNADIFFAREA 0.897600 ;
    PORT
      LAYER Metal2 ;
        RECT 530.880 999.440 531.440 1000.000 ;
    END
  END crash_dump_o[57]
  PIN crash_dump_o[58]
    DIRECTION OUTPUT ;
    USE SIGNAL ;
    ANTENNADIFFAREA 0.897600 ;
    PORT
      LAYER Metal2 ;
        RECT 534.240 999.440 534.800 1000.000 ;
    END
  END crash_dump_o[58]
  PIN crash_dump_o[59]
    DIRECTION OUTPUT ;
    USE SIGNAL ;
    ANTENNADIFFAREA 0.897600 ;
    PORT
      LAYER Metal2 ;
        RECT 537.600 999.440 538.160 1000.000 ;
    END
  END crash_dump_o[59]
  PIN crash_dump_o[5]
    DIRECTION OUTPUT ;
    USE SIGNAL ;
    ANTENNADIFFAREA 0.897600 ;
    PORT
      LAYER Metal2 ;
        RECT 356.160 999.440 356.720 1000.000 ;
    END
  END crash_dump_o[5]
  PIN crash_dump_o[60]
    DIRECTION OUTPUT ;
    USE SIGNAL ;
    ANTENNADIFFAREA 0.897600 ;
    PORT
      LAYER Metal2 ;
        RECT 540.960 999.440 541.520 1000.000 ;
    END
  END crash_dump_o[60]
  PIN crash_dump_o[61]
    DIRECTION OUTPUT ;
    USE SIGNAL ;
    ANTENNADIFFAREA 0.897600 ;
    PORT
      LAYER Metal2 ;
        RECT 544.320 999.440 544.880 1000.000 ;
    END
  END crash_dump_o[61]
  PIN crash_dump_o[62]
    DIRECTION OUTPUT ;
    USE SIGNAL ;
    ANTENNADIFFAREA 0.897600 ;
    PORT
      LAYER Metal2 ;
        RECT 547.680 999.440 548.240 1000.000 ;
    END
  END crash_dump_o[62]
  PIN crash_dump_o[63]
    DIRECTION OUTPUT ;
    USE SIGNAL ;
    ANTENNADIFFAREA 0.897600 ;
    PORT
      LAYER Metal2 ;
        RECT 551.040 999.440 551.600 1000.000 ;
    END
  END crash_dump_o[63]
  PIN crash_dump_o[64]
    DIRECTION OUTPUT ;
    USE SIGNAL ;
    ANTENNADIFFAREA 0.897600 ;
    PORT
      LAYER Metal2 ;
        RECT 554.400 999.440 554.960 1000.000 ;
    END
  END crash_dump_o[64]
  PIN crash_dump_o[65]
    DIRECTION OUTPUT ;
    USE SIGNAL ;
    ANTENNADIFFAREA 0.897600 ;
    PORT
      LAYER Metal2 ;
        RECT 557.760 999.440 558.320 1000.000 ;
    END
  END crash_dump_o[65]
  PIN crash_dump_o[66]
    DIRECTION OUTPUT ;
    USE SIGNAL ;
    ANTENNADIFFAREA 0.897600 ;
    PORT
      LAYER Metal2 ;
        RECT 561.120 999.440 561.680 1000.000 ;
    END
  END crash_dump_o[66]
  PIN crash_dump_o[67]
    DIRECTION OUTPUT ;
    USE SIGNAL ;
    ANTENNADIFFAREA 0.897600 ;
    PORT
      LAYER Metal2 ;
        RECT 564.480 999.440 565.040 1000.000 ;
    END
  END crash_dump_o[67]
  PIN crash_dump_o[68]
    DIRECTION OUTPUT ;
    USE SIGNAL ;
    ANTENNADIFFAREA 0.897600 ;
    PORT
      LAYER Metal2 ;
        RECT 567.840 999.440 568.400 1000.000 ;
    END
  END crash_dump_o[68]
  PIN crash_dump_o[69]
    DIRECTION OUTPUT ;
    USE SIGNAL ;
    ANTENNADIFFAREA 0.897600 ;
    PORT
      LAYER Metal2 ;
        RECT 571.200 999.440 571.760 1000.000 ;
    END
  END crash_dump_o[69]
  PIN crash_dump_o[6]
    DIRECTION OUTPUT ;
    USE SIGNAL ;
    ANTENNADIFFAREA 0.897600 ;
    PORT
      LAYER Metal2 ;
        RECT 359.520 999.440 360.080 1000.000 ;
    END
  END crash_dump_o[6]
  PIN crash_dump_o[70]
    DIRECTION OUTPUT ;
    USE SIGNAL ;
    ANTENNADIFFAREA 0.897600 ;
    PORT
      LAYER Metal2 ;
        RECT 574.560 999.440 575.120 1000.000 ;
    END
  END crash_dump_o[70]
  PIN crash_dump_o[71]
    DIRECTION OUTPUT ;
    USE SIGNAL ;
    ANTENNADIFFAREA 0.897600 ;
    PORT
      LAYER Metal2 ;
        RECT 577.920 999.440 578.480 1000.000 ;
    END
  END crash_dump_o[71]
  PIN crash_dump_o[72]
    DIRECTION OUTPUT ;
    USE SIGNAL ;
    ANTENNADIFFAREA 0.897600 ;
    PORT
      LAYER Metal2 ;
        RECT 581.280 999.440 581.840 1000.000 ;
    END
  END crash_dump_o[72]
  PIN crash_dump_o[73]
    DIRECTION OUTPUT ;
    USE SIGNAL ;
    ANTENNADIFFAREA 0.897600 ;
    PORT
      LAYER Metal2 ;
        RECT 584.640 999.440 585.200 1000.000 ;
    END
  END crash_dump_o[73]
  PIN crash_dump_o[74]
    DIRECTION OUTPUT ;
    USE SIGNAL ;
    ANTENNADIFFAREA 0.897600 ;
    PORT
      LAYER Metal2 ;
        RECT 588.000 999.440 588.560 1000.000 ;
    END
  END crash_dump_o[74]
  PIN crash_dump_o[75]
    DIRECTION OUTPUT ;
    USE SIGNAL ;
    ANTENNADIFFAREA 0.897600 ;
    PORT
      LAYER Metal2 ;
        RECT 591.360 999.440 591.920 1000.000 ;
    END
  END crash_dump_o[75]
  PIN crash_dump_o[76]
    DIRECTION OUTPUT ;
    USE SIGNAL ;
    ANTENNADIFFAREA 0.897600 ;
    PORT
      LAYER Metal2 ;
        RECT 594.720 999.440 595.280 1000.000 ;
    END
  END crash_dump_o[76]
  PIN crash_dump_o[77]
    DIRECTION OUTPUT ;
    USE SIGNAL ;
    ANTENNADIFFAREA 0.897600 ;
    PORT
      LAYER Metal2 ;
        RECT 598.080 999.440 598.640 1000.000 ;
    END
  END crash_dump_o[77]
  PIN crash_dump_o[78]
    DIRECTION OUTPUT ;
    USE SIGNAL ;
    ANTENNADIFFAREA 0.897600 ;
    PORT
      LAYER Metal2 ;
        RECT 601.440 999.440 602.000 1000.000 ;
    END
  END crash_dump_o[78]
  PIN crash_dump_o[79]
    DIRECTION OUTPUT ;
    USE SIGNAL ;
    ANTENNADIFFAREA 0.897600 ;
    PORT
      LAYER Metal2 ;
        RECT 604.800 999.440 605.360 1000.000 ;
    END
  END crash_dump_o[79]
  PIN crash_dump_o[7]
    DIRECTION OUTPUT ;
    USE SIGNAL ;
    ANTENNADIFFAREA 0.897600 ;
    PORT
      LAYER Metal2 ;
        RECT 362.880 999.440 363.440 1000.000 ;
    END
  END crash_dump_o[7]
  PIN crash_dump_o[80]
    DIRECTION OUTPUT ;
    USE SIGNAL ;
    ANTENNADIFFAREA 0.897600 ;
    PORT
      LAYER Metal2 ;
        RECT 608.160 999.440 608.720 1000.000 ;
    END
  END crash_dump_o[80]
  PIN crash_dump_o[81]
    DIRECTION OUTPUT ;
    USE SIGNAL ;
    ANTENNADIFFAREA 0.897600 ;
    PORT
      LAYER Metal2 ;
        RECT 611.520 999.440 612.080 1000.000 ;
    END
  END crash_dump_o[81]
  PIN crash_dump_o[82]
    DIRECTION OUTPUT ;
    USE SIGNAL ;
    ANTENNADIFFAREA 0.897600 ;
    PORT
      LAYER Metal2 ;
        RECT 614.880 999.440 615.440 1000.000 ;
    END
  END crash_dump_o[82]
  PIN crash_dump_o[83]
    DIRECTION OUTPUT ;
    USE SIGNAL ;
    ANTENNADIFFAREA 0.897600 ;
    PORT
      LAYER Metal2 ;
        RECT 618.240 999.440 618.800 1000.000 ;
    END
  END crash_dump_o[83]
  PIN crash_dump_o[84]
    DIRECTION OUTPUT ;
    USE SIGNAL ;
    ANTENNADIFFAREA 0.897600 ;
    PORT
      LAYER Metal2 ;
        RECT 621.600 999.440 622.160 1000.000 ;
    END
  END crash_dump_o[84]
  PIN crash_dump_o[85]
    DIRECTION OUTPUT ;
    USE SIGNAL ;
    ANTENNADIFFAREA 0.897600 ;
    PORT
      LAYER Metal2 ;
        RECT 624.960 999.440 625.520 1000.000 ;
    END
  END crash_dump_o[85]
  PIN crash_dump_o[86]
    DIRECTION OUTPUT ;
    USE SIGNAL ;
    ANTENNADIFFAREA 0.897600 ;
    PORT
      LAYER Metal2 ;
        RECT 628.320 999.440 628.880 1000.000 ;
    END
  END crash_dump_o[86]
  PIN crash_dump_o[87]
    DIRECTION OUTPUT ;
    USE SIGNAL ;
    ANTENNADIFFAREA 0.897600 ;
    PORT
      LAYER Metal2 ;
        RECT 631.680 999.440 632.240 1000.000 ;
    END
  END crash_dump_o[87]
  PIN crash_dump_o[88]
    DIRECTION OUTPUT ;
    USE SIGNAL ;
    ANTENNADIFFAREA 0.897600 ;
    PORT
      LAYER Metal2 ;
        RECT 635.040 999.440 635.600 1000.000 ;
    END
  END crash_dump_o[88]
  PIN crash_dump_o[89]
    DIRECTION OUTPUT ;
    USE SIGNAL ;
    ANTENNADIFFAREA 0.897600 ;
    PORT
      LAYER Metal2 ;
        RECT 638.400 999.440 638.960 1000.000 ;
    END
  END crash_dump_o[89]
  PIN crash_dump_o[8]
    DIRECTION OUTPUT ;
    USE SIGNAL ;
    ANTENNADIFFAREA 0.897600 ;
    PORT
      LAYER Metal2 ;
        RECT 366.240 999.440 366.800 1000.000 ;
    END
  END crash_dump_o[8]
  PIN crash_dump_o[90]
    DIRECTION OUTPUT ;
    USE SIGNAL ;
    ANTENNADIFFAREA 0.897600 ;
    PORT
      LAYER Metal2 ;
        RECT 641.760 999.440 642.320 1000.000 ;
    END
  END crash_dump_o[90]
  PIN crash_dump_o[91]
    DIRECTION OUTPUT ;
    USE SIGNAL ;
    ANTENNADIFFAREA 0.897600 ;
    PORT
      LAYER Metal2 ;
        RECT 645.120 999.440 645.680 1000.000 ;
    END
  END crash_dump_o[91]
  PIN crash_dump_o[92]
    DIRECTION OUTPUT ;
    USE SIGNAL ;
    ANTENNADIFFAREA 0.897600 ;
    PORT
      LAYER Metal2 ;
        RECT 648.480 999.440 649.040 1000.000 ;
    END
  END crash_dump_o[92]
  PIN crash_dump_o[93]
    DIRECTION OUTPUT ;
    USE SIGNAL ;
    ANTENNADIFFAREA 0.897600 ;
    PORT
      LAYER Metal2 ;
        RECT 651.840 999.440 652.400 1000.000 ;
    END
  END crash_dump_o[93]
  PIN crash_dump_o[94]
    DIRECTION OUTPUT ;
    USE SIGNAL ;
    ANTENNADIFFAREA 0.897600 ;
    PORT
      LAYER Metal2 ;
        RECT 655.200 999.440 655.760 1000.000 ;
    END
  END crash_dump_o[94]
  PIN crash_dump_o[95]
    DIRECTION OUTPUT ;
    USE SIGNAL ;
    ANTENNADIFFAREA 0.897600 ;
    PORT
      LAYER Metal2 ;
        RECT 658.560 999.440 659.120 1000.000 ;
    END
  END crash_dump_o[95]
  PIN crash_dump_o[96]
    DIRECTION OUTPUT ;
    USE SIGNAL ;
    ANTENNADIFFAREA 0.360800 ;
    PORT
      LAYER Metal2 ;
        RECT 661.920 999.440 662.480 1000.000 ;
    END
  END crash_dump_o[96]
  PIN crash_dump_o[97]
    DIRECTION OUTPUT ;
    USE SIGNAL ;
    ANTENNADIFFAREA 0.897600 ;
    PORT
      LAYER Metal2 ;
        RECT 665.280 999.440 665.840 1000.000 ;
    END
  END crash_dump_o[97]
  PIN crash_dump_o[98]
    DIRECTION OUTPUT ;
    USE SIGNAL ;
    ANTENNADIFFAREA 0.897600 ;
    PORT
      LAYER Metal2 ;
        RECT 668.640 999.440 669.200 1000.000 ;
    END
  END crash_dump_o[98]
  PIN crash_dump_o[99]
    DIRECTION OUTPUT ;
    USE SIGNAL ;
    ANTENNADIFFAREA 0.897600 ;
    PORT
      LAYER Metal2 ;
        RECT 672.000 999.440 672.560 1000.000 ;
    END
  END crash_dump_o[99]
  PIN crash_dump_o[9]
    DIRECTION OUTPUT ;
    USE SIGNAL ;
    ANTENNADIFFAREA 0.897600 ;
    PORT
      LAYER Metal2 ;
        RECT 369.600 999.440 370.160 1000.000 ;
    END
  END crash_dump_o[9]
  PIN data_addr_o[0]
    DIRECTION OUTPUT ;
    USE SIGNAL ;
    ANTENNADIFFAREA 0.360800 ;
    PORT
      LAYER Metal3 ;
        RECT 999.440 371.840 1000.000 372.400 ;
    END
  END data_addr_o[0]
  PIN data_addr_o[10]
    DIRECTION OUTPUT ;
    USE SIGNAL ;
    ANTENNADIFFAREA 0.897600 ;
    PORT
      LAYER Metal3 ;
        RECT 999.440 405.440 1000.000 406.000 ;
    END
  END data_addr_o[10]
  PIN data_addr_o[11]
    DIRECTION OUTPUT ;
    USE SIGNAL ;
    ANTENNADIFFAREA 0.897600 ;
    PORT
      LAYER Metal3 ;
        RECT 999.440 408.800 1000.000 409.360 ;
    END
  END data_addr_o[11]
  PIN data_addr_o[12]
    DIRECTION OUTPUT ;
    USE SIGNAL ;
    ANTENNADIFFAREA 0.897600 ;
    PORT
      LAYER Metal3 ;
        RECT 999.440 412.160 1000.000 412.720 ;
    END
  END data_addr_o[12]
  PIN data_addr_o[13]
    DIRECTION OUTPUT ;
    USE SIGNAL ;
    ANTENNADIFFAREA 0.897600 ;
    PORT
      LAYER Metal3 ;
        RECT 999.440 415.520 1000.000 416.080 ;
    END
  END data_addr_o[13]
  PIN data_addr_o[14]
    DIRECTION OUTPUT ;
    USE SIGNAL ;
    ANTENNADIFFAREA 0.897600 ;
    PORT
      LAYER Metal3 ;
        RECT 999.440 418.880 1000.000 419.440 ;
    END
  END data_addr_o[14]
  PIN data_addr_o[15]
    DIRECTION OUTPUT ;
    USE SIGNAL ;
    ANTENNADIFFAREA 0.897600 ;
    PORT
      LAYER Metal3 ;
        RECT 999.440 422.240 1000.000 422.800 ;
    END
  END data_addr_o[15]
  PIN data_addr_o[16]
    DIRECTION OUTPUT ;
    USE SIGNAL ;
    ANTENNADIFFAREA 0.897600 ;
    PORT
      LAYER Metal3 ;
        RECT 999.440 425.600 1000.000 426.160 ;
    END
  END data_addr_o[16]
  PIN data_addr_o[17]
    DIRECTION OUTPUT ;
    USE SIGNAL ;
    ANTENNADIFFAREA 0.897600 ;
    PORT
      LAYER Metal3 ;
        RECT 999.440 428.960 1000.000 429.520 ;
    END
  END data_addr_o[17]
  PIN data_addr_o[18]
    DIRECTION OUTPUT ;
    USE SIGNAL ;
    ANTENNADIFFAREA 0.897600 ;
    PORT
      LAYER Metal3 ;
        RECT 999.440 432.320 1000.000 432.880 ;
    END
  END data_addr_o[18]
  PIN data_addr_o[19]
    DIRECTION OUTPUT ;
    USE SIGNAL ;
    ANTENNADIFFAREA 0.897600 ;
    PORT
      LAYER Metal3 ;
        RECT 999.440 435.680 1000.000 436.240 ;
    END
  END data_addr_o[19]
  PIN data_addr_o[1]
    DIRECTION OUTPUT ;
    USE SIGNAL ;
    ANTENNADIFFAREA 0.360800 ;
    PORT
      LAYER Metal3 ;
        RECT 999.440 375.200 1000.000 375.760 ;
    END
  END data_addr_o[1]
  PIN data_addr_o[20]
    DIRECTION OUTPUT ;
    USE SIGNAL ;
    ANTENNADIFFAREA 0.897600 ;
    PORT
      LAYER Metal3 ;
        RECT 999.440 439.040 1000.000 439.600 ;
    END
  END data_addr_o[20]
  PIN data_addr_o[21]
    DIRECTION OUTPUT ;
    USE SIGNAL ;
    ANTENNADIFFAREA 0.897600 ;
    PORT
      LAYER Metal3 ;
        RECT 999.440 442.400 1000.000 442.960 ;
    END
  END data_addr_o[21]
  PIN data_addr_o[22]
    DIRECTION OUTPUT ;
    USE SIGNAL ;
    ANTENNADIFFAREA 0.897600 ;
    PORT
      LAYER Metal3 ;
        RECT 999.440 445.760 1000.000 446.320 ;
    END
  END data_addr_o[22]
  PIN data_addr_o[23]
    DIRECTION OUTPUT ;
    USE SIGNAL ;
    ANTENNADIFFAREA 0.897600 ;
    PORT
      LAYER Metal3 ;
        RECT 999.440 449.120 1000.000 449.680 ;
    END
  END data_addr_o[23]
  PIN data_addr_o[24]
    DIRECTION OUTPUT ;
    USE SIGNAL ;
    ANTENNADIFFAREA 0.897600 ;
    PORT
      LAYER Metal3 ;
        RECT 999.440 452.480 1000.000 453.040 ;
    END
  END data_addr_o[24]
  PIN data_addr_o[25]
    DIRECTION OUTPUT ;
    USE SIGNAL ;
    ANTENNADIFFAREA 0.897600 ;
    PORT
      LAYER Metal3 ;
        RECT 999.440 455.840 1000.000 456.400 ;
    END
  END data_addr_o[25]
  PIN data_addr_o[26]
    DIRECTION OUTPUT ;
    USE SIGNAL ;
    ANTENNADIFFAREA 0.897600 ;
    PORT
      LAYER Metal3 ;
        RECT 999.440 459.200 1000.000 459.760 ;
    END
  END data_addr_o[26]
  PIN data_addr_o[27]
    DIRECTION OUTPUT ;
    USE SIGNAL ;
    ANTENNADIFFAREA 0.897600 ;
    PORT
      LAYER Metal3 ;
        RECT 999.440 462.560 1000.000 463.120 ;
    END
  END data_addr_o[27]
  PIN data_addr_o[28]
    DIRECTION OUTPUT ;
    USE SIGNAL ;
    ANTENNADIFFAREA 0.897600 ;
    PORT
      LAYER Metal3 ;
        RECT 999.440 465.920 1000.000 466.480 ;
    END
  END data_addr_o[28]
  PIN data_addr_o[29]
    DIRECTION OUTPUT ;
    USE SIGNAL ;
    ANTENNADIFFAREA 0.897600 ;
    PORT
      LAYER Metal3 ;
        RECT 999.440 469.280 1000.000 469.840 ;
    END
  END data_addr_o[29]
  PIN data_addr_o[2]
    DIRECTION OUTPUT ;
    USE SIGNAL ;
    ANTENNADIFFAREA 0.897600 ;
    PORT
      LAYER Metal3 ;
        RECT 999.440 378.560 1000.000 379.120 ;
    END
  END data_addr_o[2]
  PIN data_addr_o[30]
    DIRECTION OUTPUT ;
    USE SIGNAL ;
    ANTENNADIFFAREA 0.897600 ;
    PORT
      LAYER Metal3 ;
        RECT 999.440 472.640 1000.000 473.200 ;
    END
  END data_addr_o[30]
  PIN data_addr_o[31]
    DIRECTION OUTPUT ;
    USE SIGNAL ;
    ANTENNADIFFAREA 0.897600 ;
    PORT
      LAYER Metal3 ;
        RECT 999.440 476.000 1000.000 476.560 ;
    END
  END data_addr_o[31]
  PIN data_addr_o[3]
    DIRECTION OUTPUT ;
    USE SIGNAL ;
    ANTENNADIFFAREA 0.897600 ;
    PORT
      LAYER Metal3 ;
        RECT 999.440 381.920 1000.000 382.480 ;
    END
  END data_addr_o[3]
  PIN data_addr_o[4]
    DIRECTION OUTPUT ;
    USE SIGNAL ;
    ANTENNADIFFAREA 0.897600 ;
    PORT
      LAYER Metal3 ;
        RECT 999.440 385.280 1000.000 385.840 ;
    END
  END data_addr_o[4]
  PIN data_addr_o[5]
    DIRECTION OUTPUT ;
    USE SIGNAL ;
    ANTENNADIFFAREA 0.897600 ;
    PORT
      LAYER Metal3 ;
        RECT 999.440 388.640 1000.000 389.200 ;
    END
  END data_addr_o[5]
  PIN data_addr_o[6]
    DIRECTION OUTPUT ;
    USE SIGNAL ;
    ANTENNADIFFAREA 0.897600 ;
    PORT
      LAYER Metal3 ;
        RECT 999.440 392.000 1000.000 392.560 ;
    END
  END data_addr_o[6]
  PIN data_addr_o[7]
    DIRECTION OUTPUT ;
    USE SIGNAL ;
    ANTENNADIFFAREA 0.897600 ;
    PORT
      LAYER Metal3 ;
        RECT 999.440 395.360 1000.000 395.920 ;
    END
  END data_addr_o[7]
  PIN data_addr_o[8]
    DIRECTION OUTPUT ;
    USE SIGNAL ;
    ANTENNADIFFAREA 0.897600 ;
    PORT
      LAYER Metal3 ;
        RECT 999.440 398.720 1000.000 399.280 ;
    END
  END data_addr_o[8]
  PIN data_addr_o[9]
    DIRECTION OUTPUT ;
    USE SIGNAL ;
    ANTENNADIFFAREA 0.897600 ;
    PORT
      LAYER Metal3 ;
        RECT 999.440 402.080 1000.000 402.640 ;
    END
  END data_addr_o[9]
  PIN data_be_o[0]
    DIRECTION OUTPUT ;
    USE SIGNAL ;
    ANTENNADIFFAREA 0.897600 ;
    PORT
      LAYER Metal3 ;
        RECT 999.440 479.360 1000.000 479.920 ;
    END
  END data_be_o[0]
  PIN data_be_o[1]
    DIRECTION OUTPUT ;
    USE SIGNAL ;
    ANTENNADIFFAREA 0.897600 ;
    PORT
      LAYER Metal3 ;
        RECT 999.440 482.720 1000.000 483.280 ;
    END
  END data_be_o[1]
  PIN data_be_o[2]
    DIRECTION OUTPUT ;
    USE SIGNAL ;
    ANTENNADIFFAREA 0.897600 ;
    PORT
      LAYER Metal3 ;
        RECT 999.440 486.080 1000.000 486.640 ;
    END
  END data_be_o[2]
  PIN data_be_o[3]
    DIRECTION OUTPUT ;
    USE SIGNAL ;
    ANTENNADIFFAREA 0.897600 ;
    PORT
      LAYER Metal3 ;
        RECT 999.440 489.440 1000.000 490.000 ;
    END
  END data_be_o[3]
  PIN data_err_i
    DIRECTION INPUT ;
    USE SIGNAL ;
    ANTENNAGATEAREA 0.396000 ;
    ANTENNADIFFAREA 0.410400 ;
    PORT
      LAYER Metal3 ;
        RECT 999.440 492.800 1000.000 493.360 ;
    END
  END data_err_i
  PIN data_gnt_i
    DIRECTION INPUT ;
    USE SIGNAL ;
    ANTENNAGATEAREA 0.396000 ;
    ANTENNADIFFAREA 0.410400 ;
    PORT
      LAYER Metal3 ;
        RECT 999.440 496.160 1000.000 496.720 ;
    END
  END data_gnt_i
  PIN data_rdata_i[0]
    DIRECTION INPUT ;
    USE SIGNAL ;
    ANTENNAGATEAREA 0.396000 ;
    ANTENNADIFFAREA 0.410400 ;
    PORT
      LAYER Metal3 ;
        RECT 999.440 499.520 1000.000 500.080 ;
    END
  END data_rdata_i[0]
  PIN data_rdata_i[10]
    DIRECTION INPUT ;
    USE SIGNAL ;
    ANTENNAGATEAREA 0.396000 ;
    ANTENNADIFFAREA 0.410400 ;
    PORT
      LAYER Metal3 ;
        RECT 999.440 533.120 1000.000 533.680 ;
    END
  END data_rdata_i[10]
  PIN data_rdata_i[11]
    DIRECTION INPUT ;
    USE SIGNAL ;
    ANTENNAGATEAREA 0.396000 ;
    ANTENNADIFFAREA 0.410400 ;
    PORT
      LAYER Metal3 ;
        RECT 999.440 536.480 1000.000 537.040 ;
    END
  END data_rdata_i[11]
  PIN data_rdata_i[12]
    DIRECTION INPUT ;
    USE SIGNAL ;
    ANTENNAGATEAREA 0.396000 ;
    ANTENNADIFFAREA 0.410400 ;
    PORT
      LAYER Metal3 ;
        RECT 999.440 539.840 1000.000 540.400 ;
    END
  END data_rdata_i[12]
  PIN data_rdata_i[13]
    DIRECTION INPUT ;
    USE SIGNAL ;
    ANTENNAGATEAREA 0.396000 ;
    ANTENNADIFFAREA 0.410400 ;
    PORT
      LAYER Metal3 ;
        RECT 999.440 543.200 1000.000 543.760 ;
    END
  END data_rdata_i[13]
  PIN data_rdata_i[14]
    DIRECTION INPUT ;
    USE SIGNAL ;
    ANTENNAGATEAREA 0.396000 ;
    ANTENNADIFFAREA 0.410400 ;
    PORT
      LAYER Metal3 ;
        RECT 999.440 546.560 1000.000 547.120 ;
    END
  END data_rdata_i[14]
  PIN data_rdata_i[15]
    DIRECTION INPUT ;
    USE SIGNAL ;
    ANTENNAGATEAREA 0.396000 ;
    ANTENNADIFFAREA 0.410400 ;
    PORT
      LAYER Metal3 ;
        RECT 999.440 549.920 1000.000 550.480 ;
    END
  END data_rdata_i[15]
  PIN data_rdata_i[16]
    DIRECTION INPUT ;
    USE SIGNAL ;
    ANTENNAGATEAREA 0.396000 ;
    ANTENNADIFFAREA 0.410400 ;
    PORT
      LAYER Metal3 ;
        RECT 999.440 553.280 1000.000 553.840 ;
    END
  END data_rdata_i[16]
  PIN data_rdata_i[17]
    DIRECTION INPUT ;
    USE SIGNAL ;
    ANTENNAGATEAREA 0.396000 ;
    ANTENNADIFFAREA 0.410400 ;
    PORT
      LAYER Metal3 ;
        RECT 999.440 556.640 1000.000 557.200 ;
    END
  END data_rdata_i[17]
  PIN data_rdata_i[18]
    DIRECTION INPUT ;
    USE SIGNAL ;
    ANTENNAGATEAREA 0.396000 ;
    ANTENNADIFFAREA 0.410400 ;
    PORT
      LAYER Metal3 ;
        RECT 999.440 560.000 1000.000 560.560 ;
    END
  END data_rdata_i[18]
  PIN data_rdata_i[19]
    DIRECTION INPUT ;
    USE SIGNAL ;
    ANTENNAGATEAREA 0.396000 ;
    ANTENNADIFFAREA 0.410400 ;
    PORT
      LAYER Metal3 ;
        RECT 999.440 563.360 1000.000 563.920 ;
    END
  END data_rdata_i[19]
  PIN data_rdata_i[1]
    DIRECTION INPUT ;
    USE SIGNAL ;
    ANTENNAGATEAREA 0.396000 ;
    ANTENNADIFFAREA 0.410400 ;
    PORT
      LAYER Metal3 ;
        RECT 999.440 502.880 1000.000 503.440 ;
    END
  END data_rdata_i[1]
  PIN data_rdata_i[20]
    DIRECTION INPUT ;
    USE SIGNAL ;
    ANTENNAGATEAREA 0.396000 ;
    ANTENNADIFFAREA 0.410400 ;
    PORT
      LAYER Metal3 ;
        RECT 999.440 566.720 1000.000 567.280 ;
    END
  END data_rdata_i[20]
  PIN data_rdata_i[21]
    DIRECTION INPUT ;
    USE SIGNAL ;
    ANTENNAGATEAREA 0.396000 ;
    ANTENNADIFFAREA 0.410400 ;
    PORT
      LAYER Metal3 ;
        RECT 999.440 570.080 1000.000 570.640 ;
    END
  END data_rdata_i[21]
  PIN data_rdata_i[22]
    DIRECTION INPUT ;
    USE SIGNAL ;
    ANTENNAGATEAREA 0.396000 ;
    ANTENNADIFFAREA 0.410400 ;
    PORT
      LAYER Metal3 ;
        RECT 999.440 573.440 1000.000 574.000 ;
    END
  END data_rdata_i[22]
  PIN data_rdata_i[23]
    DIRECTION INPUT ;
    USE SIGNAL ;
    ANTENNAGATEAREA 0.396000 ;
    ANTENNADIFFAREA 0.410400 ;
    PORT
      LAYER Metal3 ;
        RECT 999.440 576.800 1000.000 577.360 ;
    END
  END data_rdata_i[23]
  PIN data_rdata_i[24]
    DIRECTION INPUT ;
    USE SIGNAL ;
    ANTENNAGATEAREA 0.396000 ;
    ANTENNADIFFAREA 0.410400 ;
    PORT
      LAYER Metal3 ;
        RECT 999.440 580.160 1000.000 580.720 ;
    END
  END data_rdata_i[24]
  PIN data_rdata_i[25]
    DIRECTION INPUT ;
    USE SIGNAL ;
    ANTENNAGATEAREA 0.396000 ;
    ANTENNADIFFAREA 0.410400 ;
    PORT
      LAYER Metal3 ;
        RECT 999.440 583.520 1000.000 584.080 ;
    END
  END data_rdata_i[25]
  PIN data_rdata_i[26]
    DIRECTION INPUT ;
    USE SIGNAL ;
    ANTENNAGATEAREA 0.396000 ;
    ANTENNADIFFAREA 0.410400 ;
    PORT
      LAYER Metal3 ;
        RECT 999.440 586.880 1000.000 587.440 ;
    END
  END data_rdata_i[26]
  PIN data_rdata_i[27]
    DIRECTION INPUT ;
    USE SIGNAL ;
    ANTENNAGATEAREA 0.396000 ;
    ANTENNADIFFAREA 0.410400 ;
    PORT
      LAYER Metal3 ;
        RECT 999.440 590.240 1000.000 590.800 ;
    END
  END data_rdata_i[27]
  PIN data_rdata_i[28]
    DIRECTION INPUT ;
    USE SIGNAL ;
    ANTENNAGATEAREA 0.396000 ;
    ANTENNADIFFAREA 0.410400 ;
    PORT
      LAYER Metal3 ;
        RECT 999.440 593.600 1000.000 594.160 ;
    END
  END data_rdata_i[28]
  PIN data_rdata_i[29]
    DIRECTION INPUT ;
    USE SIGNAL ;
    ANTENNAGATEAREA 0.396000 ;
    ANTENNADIFFAREA 0.410400 ;
    PORT
      LAYER Metal3 ;
        RECT 999.440 596.960 1000.000 597.520 ;
    END
  END data_rdata_i[29]
  PIN data_rdata_i[2]
    DIRECTION INPUT ;
    USE SIGNAL ;
    ANTENNAGATEAREA 0.396000 ;
    ANTENNADIFFAREA 0.410400 ;
    PORT
      LAYER Metal3 ;
        RECT 999.440 506.240 1000.000 506.800 ;
    END
  END data_rdata_i[2]
  PIN data_rdata_i[30]
    DIRECTION INPUT ;
    USE SIGNAL ;
    ANTENNAGATEAREA 0.396000 ;
    ANTENNADIFFAREA 0.410400 ;
    PORT
      LAYER Metal3 ;
        RECT 999.440 600.320 1000.000 600.880 ;
    END
  END data_rdata_i[30]
  PIN data_rdata_i[31]
    DIRECTION INPUT ;
    USE SIGNAL ;
    ANTENNAGATEAREA 0.396000 ;
    ANTENNADIFFAREA 0.410400 ;
    PORT
      LAYER Metal3 ;
        RECT 999.440 603.680 1000.000 604.240 ;
    END
  END data_rdata_i[31]
  PIN data_rdata_i[3]
    DIRECTION INPUT ;
    USE SIGNAL ;
    ANTENNAGATEAREA 0.396000 ;
    ANTENNADIFFAREA 0.410400 ;
    PORT
      LAYER Metal3 ;
        RECT 999.440 509.600 1000.000 510.160 ;
    END
  END data_rdata_i[3]
  PIN data_rdata_i[4]
    DIRECTION INPUT ;
    USE SIGNAL ;
    ANTENNAGATEAREA 0.396000 ;
    ANTENNADIFFAREA 0.410400 ;
    PORT
      LAYER Metal3 ;
        RECT 999.440 512.960 1000.000 513.520 ;
    END
  END data_rdata_i[4]
  PIN data_rdata_i[5]
    DIRECTION INPUT ;
    USE SIGNAL ;
    ANTENNAGATEAREA 0.396000 ;
    ANTENNADIFFAREA 0.410400 ;
    PORT
      LAYER Metal3 ;
        RECT 999.440 516.320 1000.000 516.880 ;
    END
  END data_rdata_i[5]
  PIN data_rdata_i[6]
    DIRECTION INPUT ;
    USE SIGNAL ;
    ANTENNAGATEAREA 0.396000 ;
    ANTENNADIFFAREA 0.410400 ;
    PORT
      LAYER Metal3 ;
        RECT 999.440 519.680 1000.000 520.240 ;
    END
  END data_rdata_i[6]
  PIN data_rdata_i[7]
    DIRECTION INPUT ;
    USE SIGNAL ;
    ANTENNAGATEAREA 0.396000 ;
    ANTENNADIFFAREA 0.410400 ;
    PORT
      LAYER Metal3 ;
        RECT 999.440 523.040 1000.000 523.600 ;
    END
  END data_rdata_i[7]
  PIN data_rdata_i[8]
    DIRECTION INPUT ;
    USE SIGNAL ;
    ANTENNAGATEAREA 0.396000 ;
    ANTENNADIFFAREA 0.410400 ;
    PORT
      LAYER Metal3 ;
        RECT 999.440 526.400 1000.000 526.960 ;
    END
  END data_rdata_i[8]
  PIN data_rdata_i[9]
    DIRECTION INPUT ;
    USE SIGNAL ;
    ANTENNAGATEAREA 0.396000 ;
    ANTENNADIFFAREA 0.410400 ;
    PORT
      LAYER Metal3 ;
        RECT 999.440 529.760 1000.000 530.320 ;
    END
  END data_rdata_i[9]
  PIN data_rdata_intg_i[0]
    DIRECTION INPUT ;
    USE SIGNAL ;
    PORT
      LAYER Metal3 ;
        RECT 999.440 607.040 1000.000 607.600 ;
    END
  END data_rdata_intg_i[0]
  PIN data_rdata_intg_i[1]
    DIRECTION INPUT ;
    USE SIGNAL ;
    PORT
      LAYER Metal3 ;
        RECT 999.440 610.400 1000.000 610.960 ;
    END
  END data_rdata_intg_i[1]
  PIN data_rdata_intg_i[2]
    DIRECTION INPUT ;
    USE SIGNAL ;
    PORT
      LAYER Metal3 ;
        RECT 999.440 613.760 1000.000 614.320 ;
    END
  END data_rdata_intg_i[2]
  PIN data_rdata_intg_i[3]
    DIRECTION INPUT ;
    USE SIGNAL ;
    PORT
      LAYER Metal3 ;
        RECT 999.440 617.120 1000.000 617.680 ;
    END
  END data_rdata_intg_i[3]
  PIN data_rdata_intg_i[4]
    DIRECTION INPUT ;
    USE SIGNAL ;
    PORT
      LAYER Metal3 ;
        RECT 999.440 620.480 1000.000 621.040 ;
    END
  END data_rdata_intg_i[4]
  PIN data_rdata_intg_i[5]
    DIRECTION INPUT ;
    USE SIGNAL ;
    PORT
      LAYER Metal3 ;
        RECT 999.440 623.840 1000.000 624.400 ;
    END
  END data_rdata_intg_i[5]
  PIN data_rdata_intg_i[6]
    DIRECTION INPUT ;
    USE SIGNAL ;
    PORT
      LAYER Metal3 ;
        RECT 999.440 627.200 1000.000 627.760 ;
    END
  END data_rdata_intg_i[6]
  PIN data_req_o
    DIRECTION OUTPUT ;
    USE SIGNAL ;
    ANTENNADIFFAREA 0.897600 ;
    PORT
      LAYER Metal3 ;
        RECT 999.440 630.560 1000.000 631.120 ;
    END
  END data_req_o
  PIN data_rvalid_i
    DIRECTION INPUT ;
    USE SIGNAL ;
    ANTENNAGATEAREA 0.396000 ;
    ANTENNADIFFAREA 0.410400 ;
    PORT
      LAYER Metal3 ;
        RECT 999.440 633.920 1000.000 634.480 ;
    END
  END data_rvalid_i
  PIN data_wdata_intg_o[0]
    DIRECTION OUTPUT ;
    USE SIGNAL ;
    ANTENNADIFFAREA 0.360800 ;
    PORT
      LAYER Metal3 ;
        RECT 999.440 637.280 1000.000 637.840 ;
    END
  END data_wdata_intg_o[0]
  PIN data_wdata_intg_o[1]
    DIRECTION OUTPUT ;
    USE SIGNAL ;
    ANTENNADIFFAREA 0.360800 ;
    PORT
      LAYER Metal3 ;
        RECT 999.440 640.640 1000.000 641.200 ;
    END
  END data_wdata_intg_o[1]
  PIN data_wdata_intg_o[2]
    DIRECTION OUTPUT ;
    USE SIGNAL ;
    ANTENNADIFFAREA 0.360800 ;
    PORT
      LAYER Metal3 ;
        RECT 999.440 644.000 1000.000 644.560 ;
    END
  END data_wdata_intg_o[2]
  PIN data_wdata_intg_o[3]
    DIRECTION OUTPUT ;
    USE SIGNAL ;
    ANTENNADIFFAREA 0.360800 ;
    PORT
      LAYER Metal3 ;
        RECT 999.440 647.360 1000.000 647.920 ;
    END
  END data_wdata_intg_o[3]
  PIN data_wdata_intg_o[4]
    DIRECTION OUTPUT ;
    USE SIGNAL ;
    ANTENNADIFFAREA 0.360800 ;
    PORT
      LAYER Metal3 ;
        RECT 999.440 650.720 1000.000 651.280 ;
    END
  END data_wdata_intg_o[4]
  PIN data_wdata_intg_o[5]
    DIRECTION OUTPUT ;
    USE SIGNAL ;
    ANTENNADIFFAREA 0.360800 ;
    PORT
      LAYER Metal3 ;
        RECT 999.440 654.080 1000.000 654.640 ;
    END
  END data_wdata_intg_o[5]
  PIN data_wdata_intg_o[6]
    DIRECTION OUTPUT ;
    USE SIGNAL ;
    ANTENNADIFFAREA 0.360800 ;
    PORT
      LAYER Metal3 ;
        RECT 999.440 657.440 1000.000 658.000 ;
    END
  END data_wdata_intg_o[6]
  PIN data_wdata_o[0]
    DIRECTION OUTPUT ;
    USE SIGNAL ;
    ANTENNADIFFAREA 0.897600 ;
    PORT
      LAYER Metal3 ;
        RECT 999.440 660.800 1000.000 661.360 ;
    END
  END data_wdata_o[0]
  PIN data_wdata_o[10]
    DIRECTION OUTPUT ;
    USE SIGNAL ;
    ANTENNADIFFAREA 0.897600 ;
    PORT
      LAYER Metal3 ;
        RECT 999.440 694.400 1000.000 694.960 ;
    END
  END data_wdata_o[10]
  PIN data_wdata_o[11]
    DIRECTION OUTPUT ;
    USE SIGNAL ;
    ANTENNADIFFAREA 0.897600 ;
    PORT
      LAYER Metal3 ;
        RECT 999.440 697.760 1000.000 698.320 ;
    END
  END data_wdata_o[11]
  PIN data_wdata_o[12]
    DIRECTION OUTPUT ;
    USE SIGNAL ;
    ANTENNADIFFAREA 0.897600 ;
    PORT
      LAYER Metal3 ;
        RECT 999.440 701.120 1000.000 701.680 ;
    END
  END data_wdata_o[12]
  PIN data_wdata_o[13]
    DIRECTION OUTPUT ;
    USE SIGNAL ;
    ANTENNADIFFAREA 0.897600 ;
    PORT
      LAYER Metal3 ;
        RECT 999.440 704.480 1000.000 705.040 ;
    END
  END data_wdata_o[13]
  PIN data_wdata_o[14]
    DIRECTION OUTPUT ;
    USE SIGNAL ;
    ANTENNADIFFAREA 0.897600 ;
    PORT
      LAYER Metal3 ;
        RECT 999.440 707.840 1000.000 708.400 ;
    END
  END data_wdata_o[14]
  PIN data_wdata_o[15]
    DIRECTION OUTPUT ;
    USE SIGNAL ;
    ANTENNADIFFAREA 0.897600 ;
    PORT
      LAYER Metal3 ;
        RECT 999.440 711.200 1000.000 711.760 ;
    END
  END data_wdata_o[15]
  PIN data_wdata_o[16]
    DIRECTION OUTPUT ;
    USE SIGNAL ;
    ANTENNADIFFAREA 0.897600 ;
    PORT
      LAYER Metal3 ;
        RECT 999.440 714.560 1000.000 715.120 ;
    END
  END data_wdata_o[16]
  PIN data_wdata_o[17]
    DIRECTION OUTPUT ;
    USE SIGNAL ;
    ANTENNADIFFAREA 0.897600 ;
    PORT
      LAYER Metal3 ;
        RECT 999.440 717.920 1000.000 718.480 ;
    END
  END data_wdata_o[17]
  PIN data_wdata_o[18]
    DIRECTION OUTPUT ;
    USE SIGNAL ;
    ANTENNADIFFAREA 0.897600 ;
    PORT
      LAYER Metal3 ;
        RECT 999.440 721.280 1000.000 721.840 ;
    END
  END data_wdata_o[18]
  PIN data_wdata_o[19]
    DIRECTION OUTPUT ;
    USE SIGNAL ;
    ANTENNADIFFAREA 0.897600 ;
    PORT
      LAYER Metal3 ;
        RECT 999.440 724.640 1000.000 725.200 ;
    END
  END data_wdata_o[19]
  PIN data_wdata_o[1]
    DIRECTION OUTPUT ;
    USE SIGNAL ;
    ANTENNADIFFAREA 0.897600 ;
    PORT
      LAYER Metal3 ;
        RECT 999.440 664.160 1000.000 664.720 ;
    END
  END data_wdata_o[1]
  PIN data_wdata_o[20]
    DIRECTION OUTPUT ;
    USE SIGNAL ;
    ANTENNADIFFAREA 0.897600 ;
    PORT
      LAYER Metal3 ;
        RECT 999.440 728.000 1000.000 728.560 ;
    END
  END data_wdata_o[20]
  PIN data_wdata_o[21]
    DIRECTION OUTPUT ;
    USE SIGNAL ;
    ANTENNADIFFAREA 0.897600 ;
    PORT
      LAYER Metal3 ;
        RECT 999.440 731.360 1000.000 731.920 ;
    END
  END data_wdata_o[21]
  PIN data_wdata_o[22]
    DIRECTION OUTPUT ;
    USE SIGNAL ;
    ANTENNADIFFAREA 0.897600 ;
    PORT
      LAYER Metal3 ;
        RECT 999.440 734.720 1000.000 735.280 ;
    END
  END data_wdata_o[22]
  PIN data_wdata_o[23]
    DIRECTION OUTPUT ;
    USE SIGNAL ;
    ANTENNADIFFAREA 0.897600 ;
    PORT
      LAYER Metal3 ;
        RECT 999.440 738.080 1000.000 738.640 ;
    END
  END data_wdata_o[23]
  PIN data_wdata_o[24]
    DIRECTION OUTPUT ;
    USE SIGNAL ;
    ANTENNADIFFAREA 0.897600 ;
    PORT
      LAYER Metal3 ;
        RECT 999.440 741.440 1000.000 742.000 ;
    END
  END data_wdata_o[24]
  PIN data_wdata_o[25]
    DIRECTION OUTPUT ;
    USE SIGNAL ;
    ANTENNADIFFAREA 0.897600 ;
    PORT
      LAYER Metal3 ;
        RECT 999.440 744.800 1000.000 745.360 ;
    END
  END data_wdata_o[25]
  PIN data_wdata_o[26]
    DIRECTION OUTPUT ;
    USE SIGNAL ;
    ANTENNADIFFAREA 0.897600 ;
    PORT
      LAYER Metal3 ;
        RECT 999.440 748.160 1000.000 748.720 ;
    END
  END data_wdata_o[26]
  PIN data_wdata_o[27]
    DIRECTION OUTPUT ;
    USE SIGNAL ;
    ANTENNADIFFAREA 0.897600 ;
    PORT
      LAYER Metal3 ;
        RECT 999.440 751.520 1000.000 752.080 ;
    END
  END data_wdata_o[27]
  PIN data_wdata_o[28]
    DIRECTION OUTPUT ;
    USE SIGNAL ;
    ANTENNADIFFAREA 0.897600 ;
    PORT
      LAYER Metal3 ;
        RECT 999.440 754.880 1000.000 755.440 ;
    END
  END data_wdata_o[28]
  PIN data_wdata_o[29]
    DIRECTION OUTPUT ;
    USE SIGNAL ;
    ANTENNADIFFAREA 0.897600 ;
    PORT
      LAYER Metal3 ;
        RECT 999.440 758.240 1000.000 758.800 ;
    END
  END data_wdata_o[29]
  PIN data_wdata_o[2]
    DIRECTION OUTPUT ;
    USE SIGNAL ;
    ANTENNADIFFAREA 0.897600 ;
    PORT
      LAYER Metal3 ;
        RECT 999.440 667.520 1000.000 668.080 ;
    END
  END data_wdata_o[2]
  PIN data_wdata_o[30]
    DIRECTION OUTPUT ;
    USE SIGNAL ;
    ANTENNADIFFAREA 0.897600 ;
    PORT
      LAYER Metal3 ;
        RECT 999.440 761.600 1000.000 762.160 ;
    END
  END data_wdata_o[30]
  PIN data_wdata_o[31]
    DIRECTION OUTPUT ;
    USE SIGNAL ;
    ANTENNADIFFAREA 0.897600 ;
    PORT
      LAYER Metal3 ;
        RECT 999.440 764.960 1000.000 765.520 ;
    END
  END data_wdata_o[31]
  PIN data_wdata_o[3]
    DIRECTION OUTPUT ;
    USE SIGNAL ;
    ANTENNADIFFAREA 0.897600 ;
    PORT
      LAYER Metal3 ;
        RECT 999.440 670.880 1000.000 671.440 ;
    END
  END data_wdata_o[3]
  PIN data_wdata_o[4]
    DIRECTION OUTPUT ;
    USE SIGNAL ;
    ANTENNADIFFAREA 0.897600 ;
    PORT
      LAYER Metal3 ;
        RECT 999.440 674.240 1000.000 674.800 ;
    END
  END data_wdata_o[4]
  PIN data_wdata_o[5]
    DIRECTION OUTPUT ;
    USE SIGNAL ;
    ANTENNADIFFAREA 0.897600 ;
    PORT
      LAYER Metal3 ;
        RECT 999.440 677.600 1000.000 678.160 ;
    END
  END data_wdata_o[5]
  PIN data_wdata_o[6]
    DIRECTION OUTPUT ;
    USE SIGNAL ;
    ANTENNADIFFAREA 0.897600 ;
    PORT
      LAYER Metal3 ;
        RECT 999.440 680.960 1000.000 681.520 ;
    END
  END data_wdata_o[6]
  PIN data_wdata_o[7]
    DIRECTION OUTPUT ;
    USE SIGNAL ;
    ANTENNADIFFAREA 0.897600 ;
    PORT
      LAYER Metal3 ;
        RECT 999.440 684.320 1000.000 684.880 ;
    END
  END data_wdata_o[7]
  PIN data_wdata_o[8]
    DIRECTION OUTPUT ;
    USE SIGNAL ;
    ANTENNADIFFAREA 0.897600 ;
    PORT
      LAYER Metal3 ;
        RECT 999.440 687.680 1000.000 688.240 ;
    END
  END data_wdata_o[8]
  PIN data_wdata_o[9]
    DIRECTION OUTPUT ;
    USE SIGNAL ;
    ANTENNADIFFAREA 0.897600 ;
    PORT
      LAYER Metal3 ;
        RECT 999.440 691.040 1000.000 691.600 ;
    END
  END data_wdata_o[9]
  PIN data_we_o
    DIRECTION OUTPUT ;
    USE SIGNAL ;
    ANTENNADIFFAREA 0.897600 ;
    PORT
      LAYER Metal3 ;
        RECT 999.440 768.320 1000.000 768.880 ;
    END
  END data_we_o
  PIN debug_req_i
    DIRECTION INPUT ;
    USE SIGNAL ;
    ANTENNAGATEAREA 0.396000 ;
    ANTENNADIFFAREA 0.410400 ;
    PORT
      LAYER Metal3 ;
        RECT 999.440 865.760 1000.000 866.320 ;
    END
  END debug_req_i
  PIN double_fault_seen_o
    DIRECTION OUTPUT ;
    USE SIGNAL ;
    ANTENNADIFFAREA 0.897600 ;
    PORT
      LAYER Metal3 ;
        RECT 999.440 862.400 1000.000 862.960 ;
    END
  END double_fault_seen_o
  PIN fetch_enable_i[0]
    DIRECTION INPUT ;
    USE SIGNAL ;
    ANTENNAGATEAREA 0.396000 ;
    ANTENNADIFFAREA 0.410400 ;
    PORT
      LAYER Metal3 ;
        RECT 999.440 835.520 1000.000 836.080 ;
    END
  END fetch_enable_i[0]
  PIN fetch_enable_i[1]
    DIRECTION INPUT ;
    USE SIGNAL ;
    PORT
      LAYER Metal3 ;
        RECT 999.440 838.880 1000.000 839.440 ;
    END
  END fetch_enable_i[1]
  PIN fetch_enable_i[2]
    DIRECTION INPUT ;
    USE SIGNAL ;
    PORT
      LAYER Metal3 ;
        RECT 999.440 842.240 1000.000 842.800 ;
    END
  END fetch_enable_i[2]
  PIN fetch_enable_i[3]
    DIRECTION INPUT ;
    USE SIGNAL ;
    PORT
      LAYER Metal3 ;
        RECT 999.440 845.600 1000.000 846.160 ;
    END
  END fetch_enable_i[3]
  PIN hart_id_i[0]
    DIRECTION INPUT ;
    USE SIGNAL ;
    ANTENNAGATEAREA 0.396000 ;
    ANTENNADIFFAREA 0.410400 ;
    PORT
      LAYER Metal2 ;
        RECT 231.840 999.440 232.400 1000.000 ;
    END
  END hart_id_i[0]
  PIN hart_id_i[10]
    DIRECTION INPUT ;
    USE SIGNAL ;
    ANTENNAGATEAREA 0.396000 ;
    ANTENNADIFFAREA 0.410400 ;
    PORT
      LAYER Metal2 ;
        RECT 265.440 999.440 266.000 1000.000 ;
    END
  END hart_id_i[10]
  PIN hart_id_i[11]
    DIRECTION INPUT ;
    USE SIGNAL ;
    ANTENNAGATEAREA 0.396000 ;
    ANTENNADIFFAREA 0.410400 ;
    PORT
      LAYER Metal2 ;
        RECT 268.800 999.440 269.360 1000.000 ;
    END
  END hart_id_i[11]
  PIN hart_id_i[12]
    DIRECTION INPUT ;
    USE SIGNAL ;
    ANTENNAGATEAREA 0.396000 ;
    ANTENNADIFFAREA 0.410400 ;
    PORT
      LAYER Metal2 ;
        RECT 272.160 999.440 272.720 1000.000 ;
    END
  END hart_id_i[12]
  PIN hart_id_i[13]
    DIRECTION INPUT ;
    USE SIGNAL ;
    ANTENNAGATEAREA 0.396000 ;
    ANTENNADIFFAREA 0.410400 ;
    PORT
      LAYER Metal2 ;
        RECT 275.520 999.440 276.080 1000.000 ;
    END
  END hart_id_i[13]
  PIN hart_id_i[14]
    DIRECTION INPUT ;
    USE SIGNAL ;
    ANTENNAGATEAREA 0.396000 ;
    ANTENNADIFFAREA 0.410400 ;
    PORT
      LAYER Metal2 ;
        RECT 278.880 999.440 279.440 1000.000 ;
    END
  END hart_id_i[14]
  PIN hart_id_i[15]
    DIRECTION INPUT ;
    USE SIGNAL ;
    ANTENNAGATEAREA 0.396000 ;
    ANTENNADIFFAREA 0.410400 ;
    PORT
      LAYER Metal2 ;
        RECT 282.240 999.440 282.800 1000.000 ;
    END
  END hart_id_i[15]
  PIN hart_id_i[16]
    DIRECTION INPUT ;
    USE SIGNAL ;
    ANTENNAGATEAREA 0.396000 ;
    ANTENNADIFFAREA 0.410400 ;
    PORT
      LAYER Metal2 ;
        RECT 285.600 999.440 286.160 1000.000 ;
    END
  END hart_id_i[16]
  PIN hart_id_i[17]
    DIRECTION INPUT ;
    USE SIGNAL ;
    ANTENNAGATEAREA 0.396000 ;
    ANTENNADIFFAREA 0.410400 ;
    PORT
      LAYER Metal2 ;
        RECT 288.960 999.440 289.520 1000.000 ;
    END
  END hart_id_i[17]
  PIN hart_id_i[18]
    DIRECTION INPUT ;
    USE SIGNAL ;
    ANTENNAGATEAREA 0.396000 ;
    ANTENNADIFFAREA 0.410400 ;
    PORT
      LAYER Metal2 ;
        RECT 292.320 999.440 292.880 1000.000 ;
    END
  END hart_id_i[18]
  PIN hart_id_i[19]
    DIRECTION INPUT ;
    USE SIGNAL ;
    ANTENNAGATEAREA 0.396000 ;
    ANTENNADIFFAREA 0.410400 ;
    PORT
      LAYER Metal2 ;
        RECT 295.680 999.440 296.240 1000.000 ;
    END
  END hart_id_i[19]
  PIN hart_id_i[1]
    DIRECTION INPUT ;
    USE SIGNAL ;
    ANTENNAGATEAREA 0.396000 ;
    ANTENNADIFFAREA 0.410400 ;
    PORT
      LAYER Metal2 ;
        RECT 235.200 999.440 235.760 1000.000 ;
    END
  END hart_id_i[1]
  PIN hart_id_i[20]
    DIRECTION INPUT ;
    USE SIGNAL ;
    ANTENNAGATEAREA 0.396000 ;
    ANTENNADIFFAREA 0.410400 ;
    PORT
      LAYER Metal2 ;
        RECT 299.040 999.440 299.600 1000.000 ;
    END
  END hart_id_i[20]
  PIN hart_id_i[21]
    DIRECTION INPUT ;
    USE SIGNAL ;
    ANTENNAGATEAREA 0.396000 ;
    ANTENNADIFFAREA 0.410400 ;
    PORT
      LAYER Metal2 ;
        RECT 302.400 999.440 302.960 1000.000 ;
    END
  END hart_id_i[21]
  PIN hart_id_i[22]
    DIRECTION INPUT ;
    USE SIGNAL ;
    ANTENNAGATEAREA 0.396000 ;
    ANTENNADIFFAREA 0.410400 ;
    PORT
      LAYER Metal2 ;
        RECT 305.760 999.440 306.320 1000.000 ;
    END
  END hart_id_i[22]
  PIN hart_id_i[23]
    DIRECTION INPUT ;
    USE SIGNAL ;
    ANTENNAGATEAREA 0.396000 ;
    ANTENNADIFFAREA 0.410400 ;
    PORT
      LAYER Metal2 ;
        RECT 309.120 999.440 309.680 1000.000 ;
    END
  END hart_id_i[23]
  PIN hart_id_i[24]
    DIRECTION INPUT ;
    USE SIGNAL ;
    ANTENNAGATEAREA 0.396000 ;
    ANTENNADIFFAREA 0.410400 ;
    PORT
      LAYER Metal2 ;
        RECT 312.480 999.440 313.040 1000.000 ;
    END
  END hart_id_i[24]
  PIN hart_id_i[25]
    DIRECTION INPUT ;
    USE SIGNAL ;
    ANTENNAGATEAREA 0.396000 ;
    ANTENNADIFFAREA 0.410400 ;
    PORT
      LAYER Metal2 ;
        RECT 315.840 999.440 316.400 1000.000 ;
    END
  END hart_id_i[25]
  PIN hart_id_i[26]
    DIRECTION INPUT ;
    USE SIGNAL ;
    ANTENNAGATEAREA 0.396000 ;
    ANTENNADIFFAREA 0.410400 ;
    PORT
      LAYER Metal2 ;
        RECT 319.200 999.440 319.760 1000.000 ;
    END
  END hart_id_i[26]
  PIN hart_id_i[27]
    DIRECTION INPUT ;
    USE SIGNAL ;
    ANTENNAGATEAREA 0.396000 ;
    ANTENNADIFFAREA 0.410400 ;
    PORT
      LAYER Metal2 ;
        RECT 322.560 999.440 323.120 1000.000 ;
    END
  END hart_id_i[27]
  PIN hart_id_i[28]
    DIRECTION INPUT ;
    USE SIGNAL ;
    ANTENNAGATEAREA 0.396000 ;
    ANTENNADIFFAREA 0.410400 ;
    PORT
      LAYER Metal2 ;
        RECT 325.920 999.440 326.480 1000.000 ;
    END
  END hart_id_i[28]
  PIN hart_id_i[29]
    DIRECTION INPUT ;
    USE SIGNAL ;
    ANTENNAGATEAREA 0.396000 ;
    ANTENNADIFFAREA 0.410400 ;
    PORT
      LAYER Metal2 ;
        RECT 329.280 999.440 329.840 1000.000 ;
    END
  END hart_id_i[29]
  PIN hart_id_i[2]
    DIRECTION INPUT ;
    USE SIGNAL ;
    ANTENNAGATEAREA 0.396000 ;
    ANTENNADIFFAREA 0.410400 ;
    PORT
      LAYER Metal2 ;
        RECT 238.560 999.440 239.120 1000.000 ;
    END
  END hart_id_i[2]
  PIN hart_id_i[30]
    DIRECTION INPUT ;
    USE SIGNAL ;
    ANTENNAGATEAREA 0.396000 ;
    ANTENNADIFFAREA 0.410400 ;
    PORT
      LAYER Metal2 ;
        RECT 332.640 999.440 333.200 1000.000 ;
    END
  END hart_id_i[30]
  PIN hart_id_i[31]
    DIRECTION INPUT ;
    USE SIGNAL ;
    ANTENNAGATEAREA 0.396000 ;
    ANTENNADIFFAREA 0.410400 ;
    PORT
      LAYER Metal2 ;
        RECT 336.000 999.440 336.560 1000.000 ;
    END
  END hart_id_i[31]
  PIN hart_id_i[3]
    DIRECTION INPUT ;
    USE SIGNAL ;
    ANTENNAGATEAREA 0.396000 ;
    ANTENNADIFFAREA 0.410400 ;
    PORT
      LAYER Metal2 ;
        RECT 241.920 999.440 242.480 1000.000 ;
    END
  END hart_id_i[3]
  PIN hart_id_i[4]
    DIRECTION INPUT ;
    USE SIGNAL ;
    ANTENNAGATEAREA 0.396000 ;
    ANTENNADIFFAREA 0.410400 ;
    PORT
      LAYER Metal2 ;
        RECT 245.280 999.440 245.840 1000.000 ;
    END
  END hart_id_i[4]
  PIN hart_id_i[5]
    DIRECTION INPUT ;
    USE SIGNAL ;
    ANTENNAGATEAREA 0.396000 ;
    ANTENNADIFFAREA 0.410400 ;
    PORT
      LAYER Metal2 ;
        RECT 248.640 999.440 249.200 1000.000 ;
    END
  END hart_id_i[5]
  PIN hart_id_i[6]
    DIRECTION INPUT ;
    USE SIGNAL ;
    ANTENNAGATEAREA 0.396000 ;
    ANTENNADIFFAREA 0.410400 ;
    PORT
      LAYER Metal2 ;
        RECT 252.000 999.440 252.560 1000.000 ;
    END
  END hart_id_i[6]
  PIN hart_id_i[7]
    DIRECTION INPUT ;
    USE SIGNAL ;
    ANTENNAGATEAREA 0.396000 ;
    ANTENNADIFFAREA 0.410400 ;
    PORT
      LAYER Metal2 ;
        RECT 255.360 999.440 255.920 1000.000 ;
    END
  END hart_id_i[7]
  PIN hart_id_i[8]
    DIRECTION INPUT ;
    USE SIGNAL ;
    ANTENNAGATEAREA 0.396000 ;
    ANTENNADIFFAREA 0.410400 ;
    PORT
      LAYER Metal2 ;
        RECT 258.720 999.440 259.280 1000.000 ;
    END
  END hart_id_i[8]
  PIN hart_id_i[9]
    DIRECTION INPUT ;
    USE SIGNAL ;
    ANTENNAGATEAREA 0.396000 ;
    ANTENNADIFFAREA 0.410400 ;
    PORT
      LAYER Metal2 ;
        RECT 262.080 999.440 262.640 1000.000 ;
    END
  END hart_id_i[9]
  PIN instr_addr_o[0]
    DIRECTION OUTPUT ;
    USE SIGNAL ;
    ANTENNADIFFAREA 0.360800 ;
    PORT
      LAYER Metal3 ;
        RECT 999.440 119.840 1000.000 120.400 ;
    END
  END instr_addr_o[0]
  PIN instr_addr_o[10]
    DIRECTION OUTPUT ;
    USE SIGNAL ;
    ANTENNADIFFAREA 0.897600 ;
    PORT
      LAYER Metal3 ;
        RECT 999.440 153.440 1000.000 154.000 ;
    END
  END instr_addr_o[10]
  PIN instr_addr_o[11]
    DIRECTION OUTPUT ;
    USE SIGNAL ;
    ANTENNADIFFAREA 0.897600 ;
    PORT
      LAYER Metal3 ;
        RECT 999.440 156.800 1000.000 157.360 ;
    END
  END instr_addr_o[11]
  PIN instr_addr_o[12]
    DIRECTION OUTPUT ;
    USE SIGNAL ;
    ANTENNADIFFAREA 0.897600 ;
    PORT
      LAYER Metal3 ;
        RECT 999.440 160.160 1000.000 160.720 ;
    END
  END instr_addr_o[12]
  PIN instr_addr_o[13]
    DIRECTION OUTPUT ;
    USE SIGNAL ;
    ANTENNADIFFAREA 0.897600 ;
    PORT
      LAYER Metal3 ;
        RECT 999.440 163.520 1000.000 164.080 ;
    END
  END instr_addr_o[13]
  PIN instr_addr_o[14]
    DIRECTION OUTPUT ;
    USE SIGNAL ;
    ANTENNADIFFAREA 0.897600 ;
    PORT
      LAYER Metal3 ;
        RECT 999.440 166.880 1000.000 167.440 ;
    END
  END instr_addr_o[14]
  PIN instr_addr_o[15]
    DIRECTION OUTPUT ;
    USE SIGNAL ;
    ANTENNADIFFAREA 0.897600 ;
    PORT
      LAYER Metal3 ;
        RECT 999.440 170.240 1000.000 170.800 ;
    END
  END instr_addr_o[15]
  PIN instr_addr_o[16]
    DIRECTION OUTPUT ;
    USE SIGNAL ;
    ANTENNADIFFAREA 0.897600 ;
    PORT
      LAYER Metal3 ;
        RECT 999.440 173.600 1000.000 174.160 ;
    END
  END instr_addr_o[16]
  PIN instr_addr_o[17]
    DIRECTION OUTPUT ;
    USE SIGNAL ;
    ANTENNADIFFAREA 0.897600 ;
    PORT
      LAYER Metal3 ;
        RECT 999.440 176.960 1000.000 177.520 ;
    END
  END instr_addr_o[17]
  PIN instr_addr_o[18]
    DIRECTION OUTPUT ;
    USE SIGNAL ;
    ANTENNADIFFAREA 0.897600 ;
    PORT
      LAYER Metal3 ;
        RECT 999.440 180.320 1000.000 180.880 ;
    END
  END instr_addr_o[18]
  PIN instr_addr_o[19]
    DIRECTION OUTPUT ;
    USE SIGNAL ;
    ANTENNADIFFAREA 0.897600 ;
    PORT
      LAYER Metal3 ;
        RECT 999.440 183.680 1000.000 184.240 ;
    END
  END instr_addr_o[19]
  PIN instr_addr_o[1]
    DIRECTION OUTPUT ;
    USE SIGNAL ;
    ANTENNADIFFAREA 0.360800 ;
    PORT
      LAYER Metal3 ;
        RECT 999.440 123.200 1000.000 123.760 ;
    END
  END instr_addr_o[1]
  PIN instr_addr_o[20]
    DIRECTION OUTPUT ;
    USE SIGNAL ;
    ANTENNADIFFAREA 0.897600 ;
    PORT
      LAYER Metal3 ;
        RECT 999.440 187.040 1000.000 187.600 ;
    END
  END instr_addr_o[20]
  PIN instr_addr_o[21]
    DIRECTION OUTPUT ;
    USE SIGNAL ;
    ANTENNADIFFAREA 0.897600 ;
    PORT
      LAYER Metal3 ;
        RECT 999.440 190.400 1000.000 190.960 ;
    END
  END instr_addr_o[21]
  PIN instr_addr_o[22]
    DIRECTION OUTPUT ;
    USE SIGNAL ;
    ANTENNADIFFAREA 0.897600 ;
    PORT
      LAYER Metal3 ;
        RECT 999.440 193.760 1000.000 194.320 ;
    END
  END instr_addr_o[22]
  PIN instr_addr_o[23]
    DIRECTION OUTPUT ;
    USE SIGNAL ;
    ANTENNADIFFAREA 0.897600 ;
    PORT
      LAYER Metal3 ;
        RECT 999.440 197.120 1000.000 197.680 ;
    END
  END instr_addr_o[23]
  PIN instr_addr_o[24]
    DIRECTION OUTPUT ;
    USE SIGNAL ;
    ANTENNADIFFAREA 0.897600 ;
    PORT
      LAYER Metal3 ;
        RECT 999.440 200.480 1000.000 201.040 ;
    END
  END instr_addr_o[24]
  PIN instr_addr_o[25]
    DIRECTION OUTPUT ;
    USE SIGNAL ;
    ANTENNADIFFAREA 0.897600 ;
    PORT
      LAYER Metal3 ;
        RECT 999.440 203.840 1000.000 204.400 ;
    END
  END instr_addr_o[25]
  PIN instr_addr_o[26]
    DIRECTION OUTPUT ;
    USE SIGNAL ;
    ANTENNADIFFAREA 0.897600 ;
    PORT
      LAYER Metal3 ;
        RECT 999.440 207.200 1000.000 207.760 ;
    END
  END instr_addr_o[26]
  PIN instr_addr_o[27]
    DIRECTION OUTPUT ;
    USE SIGNAL ;
    ANTENNADIFFAREA 0.897600 ;
    PORT
      LAYER Metal3 ;
        RECT 999.440 210.560 1000.000 211.120 ;
    END
  END instr_addr_o[27]
  PIN instr_addr_o[28]
    DIRECTION OUTPUT ;
    USE SIGNAL ;
    ANTENNADIFFAREA 0.897600 ;
    PORT
      LAYER Metal3 ;
        RECT 999.440 213.920 1000.000 214.480 ;
    END
  END instr_addr_o[28]
  PIN instr_addr_o[29]
    DIRECTION OUTPUT ;
    USE SIGNAL ;
    ANTENNADIFFAREA 0.897600 ;
    PORT
      LAYER Metal3 ;
        RECT 999.440 217.280 1000.000 217.840 ;
    END
  END instr_addr_o[29]
  PIN instr_addr_o[2]
    DIRECTION OUTPUT ;
    USE SIGNAL ;
    ANTENNADIFFAREA 0.897600 ;
    PORT
      LAYER Metal3 ;
        RECT 999.440 126.560 1000.000 127.120 ;
    END
  END instr_addr_o[2]
  PIN instr_addr_o[30]
    DIRECTION OUTPUT ;
    USE SIGNAL ;
    ANTENNADIFFAREA 0.897600 ;
    PORT
      LAYER Metal3 ;
        RECT 999.440 220.640 1000.000 221.200 ;
    END
  END instr_addr_o[30]
  PIN instr_addr_o[31]
    DIRECTION OUTPUT ;
    USE SIGNAL ;
    ANTENNADIFFAREA 0.897600 ;
    PORT
      LAYER Metal3 ;
        RECT 999.440 224.000 1000.000 224.560 ;
    END
  END instr_addr_o[31]
  PIN instr_addr_o[3]
    DIRECTION OUTPUT ;
    USE SIGNAL ;
    ANTENNADIFFAREA 0.897600 ;
    PORT
      LAYER Metal3 ;
        RECT 999.440 129.920 1000.000 130.480 ;
    END
  END instr_addr_o[3]
  PIN instr_addr_o[4]
    DIRECTION OUTPUT ;
    USE SIGNAL ;
    ANTENNADIFFAREA 0.897600 ;
    PORT
      LAYER Metal3 ;
        RECT 999.440 133.280 1000.000 133.840 ;
    END
  END instr_addr_o[4]
  PIN instr_addr_o[5]
    DIRECTION OUTPUT ;
    USE SIGNAL ;
    ANTENNADIFFAREA 0.897600 ;
    PORT
      LAYER Metal3 ;
        RECT 999.440 136.640 1000.000 137.200 ;
    END
  END instr_addr_o[5]
  PIN instr_addr_o[6]
    DIRECTION OUTPUT ;
    USE SIGNAL ;
    ANTENNADIFFAREA 0.897600 ;
    PORT
      LAYER Metal3 ;
        RECT 999.440 140.000 1000.000 140.560 ;
    END
  END instr_addr_o[6]
  PIN instr_addr_o[7]
    DIRECTION OUTPUT ;
    USE SIGNAL ;
    ANTENNADIFFAREA 0.897600 ;
    PORT
      LAYER Metal3 ;
        RECT 999.440 143.360 1000.000 143.920 ;
    END
  END instr_addr_o[7]
  PIN instr_addr_o[8]
    DIRECTION OUTPUT ;
    USE SIGNAL ;
    ANTENNADIFFAREA 0.897600 ;
    PORT
      LAYER Metal3 ;
        RECT 999.440 146.720 1000.000 147.280 ;
    END
  END instr_addr_o[8]
  PIN instr_addr_o[9]
    DIRECTION OUTPUT ;
    USE SIGNAL ;
    ANTENNADIFFAREA 0.897600 ;
    PORT
      LAYER Metal3 ;
        RECT 999.440 150.080 1000.000 150.640 ;
    END
  END instr_addr_o[9]
  PIN instr_err_i
    DIRECTION INPUT ;
    USE SIGNAL ;
    ANTENNAGATEAREA 0.396000 ;
    ANTENNADIFFAREA 0.410400 ;
    PORT
      LAYER Metal3 ;
        RECT 999.440 227.360 1000.000 227.920 ;
    END
  END instr_err_i
  PIN instr_gnt_i
    DIRECTION INPUT ;
    USE SIGNAL ;
    ANTENNAGATEAREA 0.396000 ;
    ANTENNADIFFAREA 0.410400 ;
    PORT
      LAYER Metal3 ;
        RECT 999.440 230.720 1000.000 231.280 ;
    END
  END instr_gnt_i
  PIN instr_rdata_i[0]
    DIRECTION INPUT ;
    USE SIGNAL ;
    ANTENNAGATEAREA 0.396000 ;
    ANTENNADIFFAREA 0.410400 ;
    PORT
      LAYER Metal3 ;
        RECT 999.440 234.080 1000.000 234.640 ;
    END
  END instr_rdata_i[0]
  PIN instr_rdata_i[10]
    DIRECTION INPUT ;
    USE SIGNAL ;
    ANTENNAGATEAREA 0.396000 ;
    ANTENNADIFFAREA 0.410400 ;
    PORT
      LAYER Metal3 ;
        RECT 999.440 267.680 1000.000 268.240 ;
    END
  END instr_rdata_i[10]
  PIN instr_rdata_i[11]
    DIRECTION INPUT ;
    USE SIGNAL ;
    ANTENNAGATEAREA 0.396000 ;
    ANTENNADIFFAREA 0.410400 ;
    PORT
      LAYER Metal3 ;
        RECT 999.440 271.040 1000.000 271.600 ;
    END
  END instr_rdata_i[11]
  PIN instr_rdata_i[12]
    DIRECTION INPUT ;
    USE SIGNAL ;
    ANTENNAGATEAREA 0.396000 ;
    ANTENNADIFFAREA 0.410400 ;
    PORT
      LAYER Metal3 ;
        RECT 999.440 274.400 1000.000 274.960 ;
    END
  END instr_rdata_i[12]
  PIN instr_rdata_i[13]
    DIRECTION INPUT ;
    USE SIGNAL ;
    ANTENNAGATEAREA 0.396000 ;
    ANTENNADIFFAREA 0.410400 ;
    PORT
      LAYER Metal3 ;
        RECT 999.440 277.760 1000.000 278.320 ;
    END
  END instr_rdata_i[13]
  PIN instr_rdata_i[14]
    DIRECTION INPUT ;
    USE SIGNAL ;
    ANTENNAGATEAREA 0.396000 ;
    ANTENNADIFFAREA 0.410400 ;
    PORT
      LAYER Metal3 ;
        RECT 999.440 281.120 1000.000 281.680 ;
    END
  END instr_rdata_i[14]
  PIN instr_rdata_i[15]
    DIRECTION INPUT ;
    USE SIGNAL ;
    ANTENNAGATEAREA 0.396000 ;
    ANTENNADIFFAREA 0.410400 ;
    PORT
      LAYER Metal3 ;
        RECT 999.440 284.480 1000.000 285.040 ;
    END
  END instr_rdata_i[15]
  PIN instr_rdata_i[16]
    DIRECTION INPUT ;
    USE SIGNAL ;
    ANTENNAGATEAREA 0.396000 ;
    ANTENNADIFFAREA 0.410400 ;
    PORT
      LAYER Metal3 ;
        RECT 999.440 287.840 1000.000 288.400 ;
    END
  END instr_rdata_i[16]
  PIN instr_rdata_i[17]
    DIRECTION INPUT ;
    USE SIGNAL ;
    ANTENNAGATEAREA 0.396000 ;
    ANTENNADIFFAREA 0.410400 ;
    PORT
      LAYER Metal3 ;
        RECT 999.440 291.200 1000.000 291.760 ;
    END
  END instr_rdata_i[17]
  PIN instr_rdata_i[18]
    DIRECTION INPUT ;
    USE SIGNAL ;
    ANTENNAGATEAREA 0.396000 ;
    ANTENNADIFFAREA 0.410400 ;
    PORT
      LAYER Metal3 ;
        RECT 999.440 294.560 1000.000 295.120 ;
    END
  END instr_rdata_i[18]
  PIN instr_rdata_i[19]
    DIRECTION INPUT ;
    USE SIGNAL ;
    ANTENNAGATEAREA 0.396000 ;
    ANTENNADIFFAREA 0.410400 ;
    PORT
      LAYER Metal3 ;
        RECT 999.440 297.920 1000.000 298.480 ;
    END
  END instr_rdata_i[19]
  PIN instr_rdata_i[1]
    DIRECTION INPUT ;
    USE SIGNAL ;
    ANTENNAGATEAREA 0.396000 ;
    ANTENNADIFFAREA 0.410400 ;
    PORT
      LAYER Metal3 ;
        RECT 999.440 237.440 1000.000 238.000 ;
    END
  END instr_rdata_i[1]
  PIN instr_rdata_i[20]
    DIRECTION INPUT ;
    USE SIGNAL ;
    ANTENNAGATEAREA 0.396000 ;
    ANTENNADIFFAREA 0.410400 ;
    PORT
      LAYER Metal3 ;
        RECT 999.440 301.280 1000.000 301.840 ;
    END
  END instr_rdata_i[20]
  PIN instr_rdata_i[21]
    DIRECTION INPUT ;
    USE SIGNAL ;
    ANTENNAGATEAREA 0.396000 ;
    ANTENNADIFFAREA 0.410400 ;
    PORT
      LAYER Metal3 ;
        RECT 999.440 304.640 1000.000 305.200 ;
    END
  END instr_rdata_i[21]
  PIN instr_rdata_i[22]
    DIRECTION INPUT ;
    USE SIGNAL ;
    ANTENNAGATEAREA 0.396000 ;
    ANTENNADIFFAREA 0.410400 ;
    PORT
      LAYER Metal3 ;
        RECT 999.440 308.000 1000.000 308.560 ;
    END
  END instr_rdata_i[22]
  PIN instr_rdata_i[23]
    DIRECTION INPUT ;
    USE SIGNAL ;
    ANTENNAGATEAREA 0.396000 ;
    ANTENNADIFFAREA 0.410400 ;
    PORT
      LAYER Metal3 ;
        RECT 999.440 311.360 1000.000 311.920 ;
    END
  END instr_rdata_i[23]
  PIN instr_rdata_i[24]
    DIRECTION INPUT ;
    USE SIGNAL ;
    ANTENNAGATEAREA 0.396000 ;
    ANTENNADIFFAREA 0.410400 ;
    PORT
      LAYER Metal3 ;
        RECT 999.440 314.720 1000.000 315.280 ;
    END
  END instr_rdata_i[24]
  PIN instr_rdata_i[25]
    DIRECTION INPUT ;
    USE SIGNAL ;
    ANTENNAGATEAREA 0.396000 ;
    ANTENNADIFFAREA 0.410400 ;
    PORT
      LAYER Metal3 ;
        RECT 999.440 318.080 1000.000 318.640 ;
    END
  END instr_rdata_i[25]
  PIN instr_rdata_i[26]
    DIRECTION INPUT ;
    USE SIGNAL ;
    ANTENNAGATEAREA 0.396000 ;
    ANTENNADIFFAREA 0.410400 ;
    PORT
      LAYER Metal3 ;
        RECT 999.440 321.440 1000.000 322.000 ;
    END
  END instr_rdata_i[26]
  PIN instr_rdata_i[27]
    DIRECTION INPUT ;
    USE SIGNAL ;
    ANTENNAGATEAREA 0.396000 ;
    ANTENNADIFFAREA 0.410400 ;
    PORT
      LAYER Metal3 ;
        RECT 999.440 324.800 1000.000 325.360 ;
    END
  END instr_rdata_i[27]
  PIN instr_rdata_i[28]
    DIRECTION INPUT ;
    USE SIGNAL ;
    ANTENNAGATEAREA 0.396000 ;
    ANTENNADIFFAREA 0.410400 ;
    PORT
      LAYER Metal3 ;
        RECT 999.440 328.160 1000.000 328.720 ;
    END
  END instr_rdata_i[28]
  PIN instr_rdata_i[29]
    DIRECTION INPUT ;
    USE SIGNAL ;
    ANTENNAGATEAREA 0.396000 ;
    ANTENNADIFFAREA 0.410400 ;
    PORT
      LAYER Metal3 ;
        RECT 999.440 331.520 1000.000 332.080 ;
    END
  END instr_rdata_i[29]
  PIN instr_rdata_i[2]
    DIRECTION INPUT ;
    USE SIGNAL ;
    ANTENNAGATEAREA 0.396000 ;
    ANTENNADIFFAREA 0.410400 ;
    PORT
      LAYER Metal3 ;
        RECT 999.440 240.800 1000.000 241.360 ;
    END
  END instr_rdata_i[2]
  PIN instr_rdata_i[30]
    DIRECTION INPUT ;
    USE SIGNAL ;
    ANTENNAGATEAREA 0.396000 ;
    ANTENNADIFFAREA 0.410400 ;
    PORT
      LAYER Metal3 ;
        RECT 999.440 334.880 1000.000 335.440 ;
    END
  END instr_rdata_i[30]
  PIN instr_rdata_i[31]
    DIRECTION INPUT ;
    USE SIGNAL ;
    ANTENNAGATEAREA 0.396000 ;
    ANTENNADIFFAREA 0.410400 ;
    PORT
      LAYER Metal3 ;
        RECT 999.440 338.240 1000.000 338.800 ;
    END
  END instr_rdata_i[31]
  PIN instr_rdata_i[3]
    DIRECTION INPUT ;
    USE SIGNAL ;
    ANTENNAGATEAREA 0.396000 ;
    ANTENNADIFFAREA 0.410400 ;
    PORT
      LAYER Metal3 ;
        RECT 999.440 244.160 1000.000 244.720 ;
    END
  END instr_rdata_i[3]
  PIN instr_rdata_i[4]
    DIRECTION INPUT ;
    USE SIGNAL ;
    ANTENNAGATEAREA 0.396000 ;
    ANTENNADIFFAREA 0.410400 ;
    PORT
      LAYER Metal3 ;
        RECT 999.440 247.520 1000.000 248.080 ;
    END
  END instr_rdata_i[4]
  PIN instr_rdata_i[5]
    DIRECTION INPUT ;
    USE SIGNAL ;
    ANTENNAGATEAREA 0.396000 ;
    ANTENNADIFFAREA 0.410400 ;
    PORT
      LAYER Metal3 ;
        RECT 999.440 250.880 1000.000 251.440 ;
    END
  END instr_rdata_i[5]
  PIN instr_rdata_i[6]
    DIRECTION INPUT ;
    USE SIGNAL ;
    ANTENNAGATEAREA 0.396000 ;
    ANTENNADIFFAREA 0.410400 ;
    PORT
      LAYER Metal3 ;
        RECT 999.440 254.240 1000.000 254.800 ;
    END
  END instr_rdata_i[6]
  PIN instr_rdata_i[7]
    DIRECTION INPUT ;
    USE SIGNAL ;
    ANTENNAGATEAREA 0.396000 ;
    ANTENNADIFFAREA 0.410400 ;
    PORT
      LAYER Metal3 ;
        RECT 999.440 257.600 1000.000 258.160 ;
    END
  END instr_rdata_i[7]
  PIN instr_rdata_i[8]
    DIRECTION INPUT ;
    USE SIGNAL ;
    ANTENNAGATEAREA 0.396000 ;
    ANTENNADIFFAREA 0.410400 ;
    PORT
      LAYER Metal3 ;
        RECT 999.440 260.960 1000.000 261.520 ;
    END
  END instr_rdata_i[8]
  PIN instr_rdata_i[9]
    DIRECTION INPUT ;
    USE SIGNAL ;
    ANTENNAGATEAREA 0.396000 ;
    ANTENNADIFFAREA 0.410400 ;
    PORT
      LAYER Metal3 ;
        RECT 999.440 264.320 1000.000 264.880 ;
    END
  END instr_rdata_i[9]
  PIN instr_rdata_intg_i[0]
    DIRECTION INPUT ;
    USE SIGNAL ;
    PORT
      LAYER Metal3 ;
        RECT 999.440 341.600 1000.000 342.160 ;
    END
  END instr_rdata_intg_i[0]
  PIN instr_rdata_intg_i[1]
    DIRECTION INPUT ;
    USE SIGNAL ;
    PORT
      LAYER Metal3 ;
        RECT 999.440 344.960 1000.000 345.520 ;
    END
  END instr_rdata_intg_i[1]
  PIN instr_rdata_intg_i[2]
    DIRECTION INPUT ;
    USE SIGNAL ;
    PORT
      LAYER Metal3 ;
        RECT 999.440 348.320 1000.000 348.880 ;
    END
  END instr_rdata_intg_i[2]
  PIN instr_rdata_intg_i[3]
    DIRECTION INPUT ;
    USE SIGNAL ;
    PORT
      LAYER Metal3 ;
        RECT 999.440 351.680 1000.000 352.240 ;
    END
  END instr_rdata_intg_i[3]
  PIN instr_rdata_intg_i[4]
    DIRECTION INPUT ;
    USE SIGNAL ;
    PORT
      LAYER Metal3 ;
        RECT 999.440 355.040 1000.000 355.600 ;
    END
  END instr_rdata_intg_i[4]
  PIN instr_rdata_intg_i[5]
    DIRECTION INPUT ;
    USE SIGNAL ;
    PORT
      LAYER Metal3 ;
        RECT 999.440 358.400 1000.000 358.960 ;
    END
  END instr_rdata_intg_i[5]
  PIN instr_rdata_intg_i[6]
    DIRECTION INPUT ;
    USE SIGNAL ;
    PORT
      LAYER Metal3 ;
        RECT 999.440 361.760 1000.000 362.320 ;
    END
  END instr_rdata_intg_i[6]
  PIN instr_req_o
    DIRECTION OUTPUT ;
    USE SIGNAL ;
    ANTENNADIFFAREA 0.897600 ;
    PORT
      LAYER Metal3 ;
        RECT 999.440 365.120 1000.000 365.680 ;
    END
  END instr_req_o
  PIN instr_rvalid_i
    DIRECTION INPUT ;
    USE SIGNAL ;
    ANTENNAGATEAREA 0.396000 ;
    ANTENNADIFFAREA 0.410400 ;
    PORT
      LAYER Metal3 ;
        RECT 999.440 368.480 1000.000 369.040 ;
    END
  END instr_rvalid_i
  PIN irq_external_i
    DIRECTION INPUT ;
    USE SIGNAL ;
    ANTENNAGATEAREA 0.396000 ;
    ANTENNADIFFAREA 0.410400 ;
    PORT
      LAYER Metal3 ;
        RECT 999.440 771.680 1000.000 772.240 ;
    END
  END irq_external_i
  PIN irq_fast_i[0]
    DIRECTION INPUT ;
    USE SIGNAL ;
    ANTENNAGATEAREA 0.396000 ;
    ANTENNADIFFAREA 0.410400 ;
    PORT
      LAYER Metal3 ;
        RECT 999.440 775.040 1000.000 775.600 ;
    END
  END irq_fast_i[0]
  PIN irq_fast_i[10]
    DIRECTION INPUT ;
    USE SIGNAL ;
    ANTENNAGATEAREA 0.396000 ;
    ANTENNADIFFAREA 0.410400 ;
    PORT
      LAYER Metal3 ;
        RECT 999.440 808.640 1000.000 809.200 ;
    END
  END irq_fast_i[10]
  PIN irq_fast_i[11]
    DIRECTION INPUT ;
    USE SIGNAL ;
    ANTENNAGATEAREA 0.396000 ;
    ANTENNADIFFAREA 0.410400 ;
    PORT
      LAYER Metal3 ;
        RECT 999.440 812.000 1000.000 812.560 ;
    END
  END irq_fast_i[11]
  PIN irq_fast_i[12]
    DIRECTION INPUT ;
    USE SIGNAL ;
    ANTENNAGATEAREA 0.396000 ;
    ANTENNADIFFAREA 0.410400 ;
    PORT
      LAYER Metal3 ;
        RECT 999.440 815.360 1000.000 815.920 ;
    END
  END irq_fast_i[12]
  PIN irq_fast_i[13]
    DIRECTION INPUT ;
    USE SIGNAL ;
    ANTENNAGATEAREA 0.396000 ;
    ANTENNADIFFAREA 0.410400 ;
    PORT
      LAYER Metal3 ;
        RECT 999.440 818.720 1000.000 819.280 ;
    END
  END irq_fast_i[13]
  PIN irq_fast_i[14]
    DIRECTION INPUT ;
    USE SIGNAL ;
    ANTENNAGATEAREA 0.396000 ;
    ANTENNADIFFAREA 0.410400 ;
    PORT
      LAYER Metal3 ;
        RECT 999.440 822.080 1000.000 822.640 ;
    END
  END irq_fast_i[14]
  PIN irq_fast_i[1]
    DIRECTION INPUT ;
    USE SIGNAL ;
    ANTENNAGATEAREA 0.396000 ;
    ANTENNADIFFAREA 0.410400 ;
    PORT
      LAYER Metal3 ;
        RECT 999.440 778.400 1000.000 778.960 ;
    END
  END irq_fast_i[1]
  PIN irq_fast_i[2]
    DIRECTION INPUT ;
    USE SIGNAL ;
    ANTENNAGATEAREA 0.396000 ;
    ANTENNADIFFAREA 0.410400 ;
    PORT
      LAYER Metal3 ;
        RECT 999.440 781.760 1000.000 782.320 ;
    END
  END irq_fast_i[2]
  PIN irq_fast_i[3]
    DIRECTION INPUT ;
    USE SIGNAL ;
    ANTENNAGATEAREA 0.396000 ;
    ANTENNADIFFAREA 0.410400 ;
    PORT
      LAYER Metal3 ;
        RECT 999.440 785.120 1000.000 785.680 ;
    END
  END irq_fast_i[3]
  PIN irq_fast_i[4]
    DIRECTION INPUT ;
    USE SIGNAL ;
    ANTENNAGATEAREA 0.396000 ;
    ANTENNADIFFAREA 0.410400 ;
    PORT
      LAYER Metal3 ;
        RECT 999.440 788.480 1000.000 789.040 ;
    END
  END irq_fast_i[4]
  PIN irq_fast_i[5]
    DIRECTION INPUT ;
    USE SIGNAL ;
    ANTENNAGATEAREA 0.396000 ;
    ANTENNADIFFAREA 0.410400 ;
    PORT
      LAYER Metal3 ;
        RECT 999.440 791.840 1000.000 792.400 ;
    END
  END irq_fast_i[5]
  PIN irq_fast_i[6]
    DIRECTION INPUT ;
    USE SIGNAL ;
    ANTENNAGATEAREA 0.396000 ;
    ANTENNADIFFAREA 0.410400 ;
    PORT
      LAYER Metal3 ;
        RECT 999.440 795.200 1000.000 795.760 ;
    END
  END irq_fast_i[6]
  PIN irq_fast_i[7]
    DIRECTION INPUT ;
    USE SIGNAL ;
    ANTENNAGATEAREA 0.396000 ;
    ANTENNADIFFAREA 0.410400 ;
    PORT
      LAYER Metal3 ;
        RECT 999.440 798.560 1000.000 799.120 ;
    END
  END irq_fast_i[7]
  PIN irq_fast_i[8]
    DIRECTION INPUT ;
    USE SIGNAL ;
    ANTENNAGATEAREA 0.396000 ;
    ANTENNADIFFAREA 0.410400 ;
    PORT
      LAYER Metal3 ;
        RECT 999.440 801.920 1000.000 802.480 ;
    END
  END irq_fast_i[8]
  PIN irq_fast_i[9]
    DIRECTION INPUT ;
    USE SIGNAL ;
    ANTENNAGATEAREA 0.396000 ;
    ANTENNADIFFAREA 0.410400 ;
    PORT
      LAYER Metal3 ;
        RECT 999.440 805.280 1000.000 805.840 ;
    END
  END irq_fast_i[9]
  PIN irq_nm_i
    DIRECTION INPUT ;
    USE SIGNAL ;
    ANTENNAGATEAREA 0.396000 ;
    ANTENNADIFFAREA 0.410400 ;
    PORT
      LAYER Metal3 ;
        RECT 999.440 825.440 1000.000 826.000 ;
    END
  END irq_nm_i
  PIN irq_software_i
    DIRECTION INPUT ;
    USE SIGNAL ;
    ANTENNAGATEAREA 0.396000 ;
    ANTENNADIFFAREA 0.410400 ;
    PORT
      LAYER Metal3 ;
        RECT 999.440 828.800 1000.000 829.360 ;
    END
  END irq_software_i
  PIN irq_timer_i
    DIRECTION INPUT ;
    USE SIGNAL ;
    ANTENNAGATEAREA 0.396000 ;
    ANTENNADIFFAREA 0.410400 ;
    PORT
      LAYER Metal3 ;
        RECT 999.440 832.160 1000.000 832.720 ;
    END
  END irq_timer_i
  PIN ram_cfg_icache_data_i[0]
    DIRECTION INPUT ;
    USE SIGNAL ;
    PORT
      LAYER Metal2 ;
        RECT 873.600 0.000 874.160 0.560 ;
    END
  END ram_cfg_icache_data_i[0]
  PIN ram_cfg_icache_data_i[10]
    DIRECTION INPUT ;
    USE SIGNAL ;
    PORT
      LAYER Metal2 ;
        RECT 918.400 0.000 918.960 0.560 ;
    END
  END ram_cfg_icache_data_i[10]
  PIN ram_cfg_icache_data_i[11]
    DIRECTION INPUT ;
    USE SIGNAL ;
    PORT
      LAYER Metal2 ;
        RECT 922.880 0.000 923.440 0.560 ;
    END
  END ram_cfg_icache_data_i[11]
  PIN ram_cfg_icache_data_i[1]
    DIRECTION INPUT ;
    USE SIGNAL ;
    PORT
      LAYER Metal2 ;
        RECT 878.080 0.000 878.640 0.560 ;
    END
  END ram_cfg_icache_data_i[1]
  PIN ram_cfg_icache_data_i[2]
    DIRECTION INPUT ;
    USE SIGNAL ;
    PORT
      LAYER Metal2 ;
        RECT 882.560 0.000 883.120 0.560 ;
    END
  END ram_cfg_icache_data_i[2]
  PIN ram_cfg_icache_data_i[3]
    DIRECTION INPUT ;
    USE SIGNAL ;
    PORT
      LAYER Metal2 ;
        RECT 887.040 0.000 887.600 0.560 ;
    END
  END ram_cfg_icache_data_i[3]
  PIN ram_cfg_icache_data_i[4]
    DIRECTION INPUT ;
    USE SIGNAL ;
    PORT
      LAYER Metal2 ;
        RECT 891.520 0.000 892.080 0.560 ;
    END
  END ram_cfg_icache_data_i[4]
  PIN ram_cfg_icache_data_i[5]
    DIRECTION INPUT ;
    USE SIGNAL ;
    PORT
      LAYER Metal2 ;
        RECT 896.000 0.000 896.560 0.560 ;
    END
  END ram_cfg_icache_data_i[5]
  PIN ram_cfg_icache_data_i[6]
    DIRECTION INPUT ;
    USE SIGNAL ;
    PORT
      LAYER Metal2 ;
        RECT 900.480 0.000 901.040 0.560 ;
    END
  END ram_cfg_icache_data_i[6]
  PIN ram_cfg_icache_data_i[7]
    DIRECTION INPUT ;
    USE SIGNAL ;
    PORT
      LAYER Metal2 ;
        RECT 904.960 0.000 905.520 0.560 ;
    END
  END ram_cfg_icache_data_i[7]
  PIN ram_cfg_icache_data_i[8]
    DIRECTION INPUT ;
    USE SIGNAL ;
    PORT
      LAYER Metal2 ;
        RECT 909.440 0.000 910.000 0.560 ;
    END
  END ram_cfg_icache_data_i[8]
  PIN ram_cfg_icache_data_i[9]
    DIRECTION INPUT ;
    USE SIGNAL ;
    PORT
      LAYER Metal2 ;
        RECT 913.920 0.000 914.480 0.560 ;
    END
  END ram_cfg_icache_data_i[9]
  PIN ram_cfg_icache_tag_i[0]
    DIRECTION INPUT ;
    USE SIGNAL ;
    PORT
      LAYER Metal2 ;
        RECT 927.360 0.000 927.920 0.560 ;
    END
  END ram_cfg_icache_tag_i[0]
  PIN ram_cfg_icache_tag_i[10]
    DIRECTION INPUT ;
    USE SIGNAL ;
    PORT
      LAYER Metal2 ;
        RECT 972.160 0.000 972.720 0.560 ;
    END
  END ram_cfg_icache_tag_i[10]
  PIN ram_cfg_icache_tag_i[11]
    DIRECTION INPUT ;
    USE SIGNAL ;
    PORT
      LAYER Metal2 ;
        RECT 976.640 0.000 977.200 0.560 ;
    END
  END ram_cfg_icache_tag_i[11]
  PIN ram_cfg_icache_tag_i[1]
    DIRECTION INPUT ;
    USE SIGNAL ;
    PORT
      LAYER Metal2 ;
        RECT 931.840 0.000 932.400 0.560 ;
    END
  END ram_cfg_icache_tag_i[1]
  PIN ram_cfg_icache_tag_i[2]
    DIRECTION INPUT ;
    USE SIGNAL ;
    PORT
      LAYER Metal2 ;
        RECT 936.320 0.000 936.880 0.560 ;
    END
  END ram_cfg_icache_tag_i[2]
  PIN ram_cfg_icache_tag_i[3]
    DIRECTION INPUT ;
    USE SIGNAL ;
    PORT
      LAYER Metal2 ;
        RECT 940.800 0.000 941.360 0.560 ;
    END
  END ram_cfg_icache_tag_i[3]
  PIN ram_cfg_icache_tag_i[4]
    DIRECTION INPUT ;
    USE SIGNAL ;
    PORT
      LAYER Metal2 ;
        RECT 945.280 0.000 945.840 0.560 ;
    END
  END ram_cfg_icache_tag_i[4]
  PIN ram_cfg_icache_tag_i[5]
    DIRECTION INPUT ;
    USE SIGNAL ;
    PORT
      LAYER Metal2 ;
        RECT 949.760 0.000 950.320 0.560 ;
    END
  END ram_cfg_icache_tag_i[5]
  PIN ram_cfg_icache_tag_i[6]
    DIRECTION INPUT ;
    USE SIGNAL ;
    PORT
      LAYER Metal2 ;
        RECT 954.240 0.000 954.800 0.560 ;
    END
  END ram_cfg_icache_tag_i[6]
  PIN ram_cfg_icache_tag_i[7]
    DIRECTION INPUT ;
    USE SIGNAL ;
    PORT
      LAYER Metal2 ;
        RECT 958.720 0.000 959.280 0.560 ;
    END
  END ram_cfg_icache_tag_i[7]
  PIN ram_cfg_icache_tag_i[8]
    DIRECTION INPUT ;
    USE SIGNAL ;
    PORT
      LAYER Metal2 ;
        RECT 963.200 0.000 963.760 0.560 ;
    END
  END ram_cfg_icache_tag_i[8]
  PIN ram_cfg_icache_tag_i[9]
    DIRECTION INPUT ;
    USE SIGNAL ;
    PORT
      LAYER Metal2 ;
        RECT 967.680 0.000 968.240 0.560 ;
    END
  END ram_cfg_icache_tag_i[9]
  PIN ram_cfg_rsp_icache_data_o[0]
    DIRECTION OUTPUT ;
    USE SIGNAL ;
    ANTENNADIFFAREA 0.360800 ;
    PORT
      LAYER Metal2 ;
        RECT 981.120 0.000 981.680 0.560 ;
    END
  END ram_cfg_rsp_icache_data_o[0]
  PIN ram_cfg_rsp_icache_data_o[1]
    DIRECTION OUTPUT ;
    USE SIGNAL ;
    ANTENNADIFFAREA 0.360800 ;
    PORT
      LAYER Metal2 ;
        RECT 985.600 0.000 986.160 0.560 ;
    END
  END ram_cfg_rsp_icache_data_o[1]
  PIN ram_cfg_rsp_icache_tag_o[0]
    DIRECTION OUTPUT ;
    USE SIGNAL ;
    ANTENNADIFFAREA 0.360800 ;
    PORT
      LAYER Metal2 ;
        RECT 990.080 0.000 990.640 0.560 ;
    END
  END ram_cfg_rsp_icache_tag_o[0]
  PIN ram_cfg_rsp_icache_tag_o[1]
    DIRECTION OUTPUT ;
    USE SIGNAL ;
    ANTENNADIFFAREA 0.360800 ;
    PORT
      LAYER Metal2 ;
        RECT 994.560 0.000 995.120 0.560 ;
    END
  END ram_cfg_rsp_icache_tag_o[1]
  PIN rst_ni
    DIRECTION INPUT ;
    USE SIGNAL ;
    ANTENNAGATEAREA 0.396000 ;
    ANTENNADIFFAREA 0.410400 ;
    PORT
      LAYER Metal3 ;
        RECT 999.440 872.480 1000.000 873.040 ;
    END
  END rst_ni
  PIN scan_rst_ni
    DIRECTION INPUT ;
    USE SIGNAL ;
    PORT
      LAYER Metal3 ;
        RECT 999.440 879.200 1000.000 879.760 ;
    END
  END scan_rst_ni
  PIN scramble_key_i[0]
    DIRECTION INPUT ;
    USE SIGNAL ;
    PORT
      LAYER Metal2 ;
        RECT 4.480 0.000 5.040 0.560 ;
    END
  END scramble_key_i[0]
  PIN scramble_key_i[100]
    DIRECTION INPUT ;
    USE SIGNAL ;
    PORT
      LAYER Metal2 ;
        RECT 452.480 0.000 453.040 0.560 ;
    END
  END scramble_key_i[100]
  PIN scramble_key_i[101]
    DIRECTION INPUT ;
    USE SIGNAL ;
    PORT
      LAYER Metal2 ;
        RECT 456.960 0.000 457.520 0.560 ;
    END
  END scramble_key_i[101]
  PIN scramble_key_i[102]
    DIRECTION INPUT ;
    USE SIGNAL ;
    PORT
      LAYER Metal2 ;
        RECT 461.440 0.000 462.000 0.560 ;
    END
  END scramble_key_i[102]
  PIN scramble_key_i[103]
    DIRECTION INPUT ;
    USE SIGNAL ;
    PORT
      LAYER Metal2 ;
        RECT 465.920 0.000 466.480 0.560 ;
    END
  END scramble_key_i[103]
  PIN scramble_key_i[104]
    DIRECTION INPUT ;
    USE SIGNAL ;
    PORT
      LAYER Metal2 ;
        RECT 470.400 0.000 470.960 0.560 ;
    END
  END scramble_key_i[104]
  PIN scramble_key_i[105]
    DIRECTION INPUT ;
    USE SIGNAL ;
    PORT
      LAYER Metal2 ;
        RECT 474.880 0.000 475.440 0.560 ;
    END
  END scramble_key_i[105]
  PIN scramble_key_i[106]
    DIRECTION INPUT ;
    USE SIGNAL ;
    PORT
      LAYER Metal2 ;
        RECT 479.360 0.000 479.920 0.560 ;
    END
  END scramble_key_i[106]
  PIN scramble_key_i[107]
    DIRECTION INPUT ;
    USE SIGNAL ;
    PORT
      LAYER Metal2 ;
        RECT 483.840 0.000 484.400 0.560 ;
    END
  END scramble_key_i[107]
  PIN scramble_key_i[108]
    DIRECTION INPUT ;
    USE SIGNAL ;
    PORT
      LAYER Metal2 ;
        RECT 488.320 0.000 488.880 0.560 ;
    END
  END scramble_key_i[108]
  PIN scramble_key_i[109]
    DIRECTION INPUT ;
    USE SIGNAL ;
    PORT
      LAYER Metal2 ;
        RECT 492.800 0.000 493.360 0.560 ;
    END
  END scramble_key_i[109]
  PIN scramble_key_i[10]
    DIRECTION INPUT ;
    USE SIGNAL ;
    PORT
      LAYER Metal2 ;
        RECT 49.280 0.000 49.840 0.560 ;
    END
  END scramble_key_i[10]
  PIN scramble_key_i[110]
    DIRECTION INPUT ;
    USE SIGNAL ;
    PORT
      LAYER Metal2 ;
        RECT 497.280 0.000 497.840 0.560 ;
    END
  END scramble_key_i[110]
  PIN scramble_key_i[111]
    DIRECTION INPUT ;
    USE SIGNAL ;
    PORT
      LAYER Metal2 ;
        RECT 501.760 0.000 502.320 0.560 ;
    END
  END scramble_key_i[111]
  PIN scramble_key_i[112]
    DIRECTION INPUT ;
    USE SIGNAL ;
    PORT
      LAYER Metal2 ;
        RECT 506.240 0.000 506.800 0.560 ;
    END
  END scramble_key_i[112]
  PIN scramble_key_i[113]
    DIRECTION INPUT ;
    USE SIGNAL ;
    PORT
      LAYER Metal2 ;
        RECT 510.720 0.000 511.280 0.560 ;
    END
  END scramble_key_i[113]
  PIN scramble_key_i[114]
    DIRECTION INPUT ;
    USE SIGNAL ;
    PORT
      LAYER Metal2 ;
        RECT 515.200 0.000 515.760 0.560 ;
    END
  END scramble_key_i[114]
  PIN scramble_key_i[115]
    DIRECTION INPUT ;
    USE SIGNAL ;
    PORT
      LAYER Metal2 ;
        RECT 519.680 0.000 520.240 0.560 ;
    END
  END scramble_key_i[115]
  PIN scramble_key_i[116]
    DIRECTION INPUT ;
    USE SIGNAL ;
    PORT
      LAYER Metal2 ;
        RECT 524.160 0.000 524.720 0.560 ;
    END
  END scramble_key_i[116]
  PIN scramble_key_i[117]
    DIRECTION INPUT ;
    USE SIGNAL ;
    PORT
      LAYER Metal2 ;
        RECT 528.640 0.000 529.200 0.560 ;
    END
  END scramble_key_i[117]
  PIN scramble_key_i[118]
    DIRECTION INPUT ;
    USE SIGNAL ;
    PORT
      LAYER Metal2 ;
        RECT 533.120 0.000 533.680 0.560 ;
    END
  END scramble_key_i[118]
  PIN scramble_key_i[119]
    DIRECTION INPUT ;
    USE SIGNAL ;
    PORT
      LAYER Metal2 ;
        RECT 537.600 0.000 538.160 0.560 ;
    END
  END scramble_key_i[119]
  PIN scramble_key_i[11]
    DIRECTION INPUT ;
    USE SIGNAL ;
    PORT
      LAYER Metal2 ;
        RECT 53.760 0.000 54.320 0.560 ;
    END
  END scramble_key_i[11]
  PIN scramble_key_i[120]
    DIRECTION INPUT ;
    USE SIGNAL ;
    PORT
      LAYER Metal2 ;
        RECT 542.080 0.000 542.640 0.560 ;
    END
  END scramble_key_i[120]
  PIN scramble_key_i[121]
    DIRECTION INPUT ;
    USE SIGNAL ;
    PORT
      LAYER Metal2 ;
        RECT 546.560 0.000 547.120 0.560 ;
    END
  END scramble_key_i[121]
  PIN scramble_key_i[122]
    DIRECTION INPUT ;
    USE SIGNAL ;
    PORT
      LAYER Metal2 ;
        RECT 551.040 0.000 551.600 0.560 ;
    END
  END scramble_key_i[122]
  PIN scramble_key_i[123]
    DIRECTION INPUT ;
    USE SIGNAL ;
    PORT
      LAYER Metal2 ;
        RECT 555.520 0.000 556.080 0.560 ;
    END
  END scramble_key_i[123]
  PIN scramble_key_i[124]
    DIRECTION INPUT ;
    USE SIGNAL ;
    PORT
      LAYER Metal2 ;
        RECT 560.000 0.000 560.560 0.560 ;
    END
  END scramble_key_i[124]
  PIN scramble_key_i[125]
    DIRECTION INPUT ;
    USE SIGNAL ;
    PORT
      LAYER Metal2 ;
        RECT 564.480 0.000 565.040 0.560 ;
    END
  END scramble_key_i[125]
  PIN scramble_key_i[126]
    DIRECTION INPUT ;
    USE SIGNAL ;
    PORT
      LAYER Metal2 ;
        RECT 568.960 0.000 569.520 0.560 ;
    END
  END scramble_key_i[126]
  PIN scramble_key_i[127]
    DIRECTION INPUT ;
    USE SIGNAL ;
    PORT
      LAYER Metal2 ;
        RECT 573.440 0.000 574.000 0.560 ;
    END
  END scramble_key_i[127]
  PIN scramble_key_i[12]
    DIRECTION INPUT ;
    USE SIGNAL ;
    PORT
      LAYER Metal2 ;
        RECT 58.240 0.000 58.800 0.560 ;
    END
  END scramble_key_i[12]
  PIN scramble_key_i[13]
    DIRECTION INPUT ;
    USE SIGNAL ;
    PORT
      LAYER Metal2 ;
        RECT 62.720 0.000 63.280 0.560 ;
    END
  END scramble_key_i[13]
  PIN scramble_key_i[14]
    DIRECTION INPUT ;
    USE SIGNAL ;
    PORT
      LAYER Metal2 ;
        RECT 67.200 0.000 67.760 0.560 ;
    END
  END scramble_key_i[14]
  PIN scramble_key_i[15]
    DIRECTION INPUT ;
    USE SIGNAL ;
    PORT
      LAYER Metal2 ;
        RECT 71.680 0.000 72.240 0.560 ;
    END
  END scramble_key_i[15]
  PIN scramble_key_i[16]
    DIRECTION INPUT ;
    USE SIGNAL ;
    PORT
      LAYER Metal2 ;
        RECT 76.160 0.000 76.720 0.560 ;
    END
  END scramble_key_i[16]
  PIN scramble_key_i[17]
    DIRECTION INPUT ;
    USE SIGNAL ;
    PORT
      LAYER Metal2 ;
        RECT 80.640 0.000 81.200 0.560 ;
    END
  END scramble_key_i[17]
  PIN scramble_key_i[18]
    DIRECTION INPUT ;
    USE SIGNAL ;
    PORT
      LAYER Metal2 ;
        RECT 85.120 0.000 85.680 0.560 ;
    END
  END scramble_key_i[18]
  PIN scramble_key_i[19]
    DIRECTION INPUT ;
    USE SIGNAL ;
    PORT
      LAYER Metal2 ;
        RECT 89.600 0.000 90.160 0.560 ;
    END
  END scramble_key_i[19]
  PIN scramble_key_i[1]
    DIRECTION INPUT ;
    USE SIGNAL ;
    PORT
      LAYER Metal2 ;
        RECT 8.960 0.000 9.520 0.560 ;
    END
  END scramble_key_i[1]
  PIN scramble_key_i[20]
    DIRECTION INPUT ;
    USE SIGNAL ;
    PORT
      LAYER Metal2 ;
        RECT 94.080 0.000 94.640 0.560 ;
    END
  END scramble_key_i[20]
  PIN scramble_key_i[21]
    DIRECTION INPUT ;
    USE SIGNAL ;
    PORT
      LAYER Metal2 ;
        RECT 98.560 0.000 99.120 0.560 ;
    END
  END scramble_key_i[21]
  PIN scramble_key_i[22]
    DIRECTION INPUT ;
    USE SIGNAL ;
    PORT
      LAYER Metal2 ;
        RECT 103.040 0.000 103.600 0.560 ;
    END
  END scramble_key_i[22]
  PIN scramble_key_i[23]
    DIRECTION INPUT ;
    USE SIGNAL ;
    PORT
      LAYER Metal2 ;
        RECT 107.520 0.000 108.080 0.560 ;
    END
  END scramble_key_i[23]
  PIN scramble_key_i[24]
    DIRECTION INPUT ;
    USE SIGNAL ;
    PORT
      LAYER Metal2 ;
        RECT 112.000 0.000 112.560 0.560 ;
    END
  END scramble_key_i[24]
  PIN scramble_key_i[25]
    DIRECTION INPUT ;
    USE SIGNAL ;
    PORT
      LAYER Metal2 ;
        RECT 116.480 0.000 117.040 0.560 ;
    END
  END scramble_key_i[25]
  PIN scramble_key_i[26]
    DIRECTION INPUT ;
    USE SIGNAL ;
    PORT
      LAYER Metal2 ;
        RECT 120.960 0.000 121.520 0.560 ;
    END
  END scramble_key_i[26]
  PIN scramble_key_i[27]
    DIRECTION INPUT ;
    USE SIGNAL ;
    PORT
      LAYER Metal2 ;
        RECT 125.440 0.000 126.000 0.560 ;
    END
  END scramble_key_i[27]
  PIN scramble_key_i[28]
    DIRECTION INPUT ;
    USE SIGNAL ;
    PORT
      LAYER Metal2 ;
        RECT 129.920 0.000 130.480 0.560 ;
    END
  END scramble_key_i[28]
  PIN scramble_key_i[29]
    DIRECTION INPUT ;
    USE SIGNAL ;
    PORT
      LAYER Metal2 ;
        RECT 134.400 0.000 134.960 0.560 ;
    END
  END scramble_key_i[29]
  PIN scramble_key_i[2]
    DIRECTION INPUT ;
    USE SIGNAL ;
    PORT
      LAYER Metal2 ;
        RECT 13.440 0.000 14.000 0.560 ;
    END
  END scramble_key_i[2]
  PIN scramble_key_i[30]
    DIRECTION INPUT ;
    USE SIGNAL ;
    PORT
      LAYER Metal2 ;
        RECT 138.880 0.000 139.440 0.560 ;
    END
  END scramble_key_i[30]
  PIN scramble_key_i[31]
    DIRECTION INPUT ;
    USE SIGNAL ;
    PORT
      LAYER Metal2 ;
        RECT 143.360 0.000 143.920 0.560 ;
    END
  END scramble_key_i[31]
  PIN scramble_key_i[32]
    DIRECTION INPUT ;
    USE SIGNAL ;
    PORT
      LAYER Metal2 ;
        RECT 147.840 0.000 148.400 0.560 ;
    END
  END scramble_key_i[32]
  PIN scramble_key_i[33]
    DIRECTION INPUT ;
    USE SIGNAL ;
    PORT
      LAYER Metal2 ;
        RECT 152.320 0.000 152.880 0.560 ;
    END
  END scramble_key_i[33]
  PIN scramble_key_i[34]
    DIRECTION INPUT ;
    USE SIGNAL ;
    PORT
      LAYER Metal2 ;
        RECT 156.800 0.000 157.360 0.560 ;
    END
  END scramble_key_i[34]
  PIN scramble_key_i[35]
    DIRECTION INPUT ;
    USE SIGNAL ;
    PORT
      LAYER Metal2 ;
        RECT 161.280 0.000 161.840 0.560 ;
    END
  END scramble_key_i[35]
  PIN scramble_key_i[36]
    DIRECTION INPUT ;
    USE SIGNAL ;
    PORT
      LAYER Metal2 ;
        RECT 165.760 0.000 166.320 0.560 ;
    END
  END scramble_key_i[36]
  PIN scramble_key_i[37]
    DIRECTION INPUT ;
    USE SIGNAL ;
    PORT
      LAYER Metal2 ;
        RECT 170.240 0.000 170.800 0.560 ;
    END
  END scramble_key_i[37]
  PIN scramble_key_i[38]
    DIRECTION INPUT ;
    USE SIGNAL ;
    PORT
      LAYER Metal2 ;
        RECT 174.720 0.000 175.280 0.560 ;
    END
  END scramble_key_i[38]
  PIN scramble_key_i[39]
    DIRECTION INPUT ;
    USE SIGNAL ;
    PORT
      LAYER Metal2 ;
        RECT 179.200 0.000 179.760 0.560 ;
    END
  END scramble_key_i[39]
  PIN scramble_key_i[3]
    DIRECTION INPUT ;
    USE SIGNAL ;
    PORT
      LAYER Metal2 ;
        RECT 17.920 0.000 18.480 0.560 ;
    END
  END scramble_key_i[3]
  PIN scramble_key_i[40]
    DIRECTION INPUT ;
    USE SIGNAL ;
    PORT
      LAYER Metal2 ;
        RECT 183.680 0.000 184.240 0.560 ;
    END
  END scramble_key_i[40]
  PIN scramble_key_i[41]
    DIRECTION INPUT ;
    USE SIGNAL ;
    PORT
      LAYER Metal2 ;
        RECT 188.160 0.000 188.720 0.560 ;
    END
  END scramble_key_i[41]
  PIN scramble_key_i[42]
    DIRECTION INPUT ;
    USE SIGNAL ;
    PORT
      LAYER Metal2 ;
        RECT 192.640 0.000 193.200 0.560 ;
    END
  END scramble_key_i[42]
  PIN scramble_key_i[43]
    DIRECTION INPUT ;
    USE SIGNAL ;
    PORT
      LAYER Metal2 ;
        RECT 197.120 0.000 197.680 0.560 ;
    END
  END scramble_key_i[43]
  PIN scramble_key_i[44]
    DIRECTION INPUT ;
    USE SIGNAL ;
    PORT
      LAYER Metal2 ;
        RECT 201.600 0.000 202.160 0.560 ;
    END
  END scramble_key_i[44]
  PIN scramble_key_i[45]
    DIRECTION INPUT ;
    USE SIGNAL ;
    PORT
      LAYER Metal2 ;
        RECT 206.080 0.000 206.640 0.560 ;
    END
  END scramble_key_i[45]
  PIN scramble_key_i[46]
    DIRECTION INPUT ;
    USE SIGNAL ;
    PORT
      LAYER Metal2 ;
        RECT 210.560 0.000 211.120 0.560 ;
    END
  END scramble_key_i[46]
  PIN scramble_key_i[47]
    DIRECTION INPUT ;
    USE SIGNAL ;
    PORT
      LAYER Metal2 ;
        RECT 215.040 0.000 215.600 0.560 ;
    END
  END scramble_key_i[47]
  PIN scramble_key_i[48]
    DIRECTION INPUT ;
    USE SIGNAL ;
    PORT
      LAYER Metal2 ;
        RECT 219.520 0.000 220.080 0.560 ;
    END
  END scramble_key_i[48]
  PIN scramble_key_i[49]
    DIRECTION INPUT ;
    USE SIGNAL ;
    PORT
      LAYER Metal2 ;
        RECT 224.000 0.000 224.560 0.560 ;
    END
  END scramble_key_i[49]
  PIN scramble_key_i[4]
    DIRECTION INPUT ;
    USE SIGNAL ;
    PORT
      LAYER Metal2 ;
        RECT 22.400 0.000 22.960 0.560 ;
    END
  END scramble_key_i[4]
  PIN scramble_key_i[50]
    DIRECTION INPUT ;
    USE SIGNAL ;
    PORT
      LAYER Metal2 ;
        RECT 228.480 0.000 229.040 0.560 ;
    END
  END scramble_key_i[50]
  PIN scramble_key_i[51]
    DIRECTION INPUT ;
    USE SIGNAL ;
    PORT
      LAYER Metal2 ;
        RECT 232.960 0.000 233.520 0.560 ;
    END
  END scramble_key_i[51]
  PIN scramble_key_i[52]
    DIRECTION INPUT ;
    USE SIGNAL ;
    PORT
      LAYER Metal2 ;
        RECT 237.440 0.000 238.000 0.560 ;
    END
  END scramble_key_i[52]
  PIN scramble_key_i[53]
    DIRECTION INPUT ;
    USE SIGNAL ;
    PORT
      LAYER Metal2 ;
        RECT 241.920 0.000 242.480 0.560 ;
    END
  END scramble_key_i[53]
  PIN scramble_key_i[54]
    DIRECTION INPUT ;
    USE SIGNAL ;
    PORT
      LAYER Metal2 ;
        RECT 246.400 0.000 246.960 0.560 ;
    END
  END scramble_key_i[54]
  PIN scramble_key_i[55]
    DIRECTION INPUT ;
    USE SIGNAL ;
    PORT
      LAYER Metal2 ;
        RECT 250.880 0.000 251.440 0.560 ;
    END
  END scramble_key_i[55]
  PIN scramble_key_i[56]
    DIRECTION INPUT ;
    USE SIGNAL ;
    PORT
      LAYER Metal2 ;
        RECT 255.360 0.000 255.920 0.560 ;
    END
  END scramble_key_i[56]
  PIN scramble_key_i[57]
    DIRECTION INPUT ;
    USE SIGNAL ;
    PORT
      LAYER Metal2 ;
        RECT 259.840 0.000 260.400 0.560 ;
    END
  END scramble_key_i[57]
  PIN scramble_key_i[58]
    DIRECTION INPUT ;
    USE SIGNAL ;
    PORT
      LAYER Metal2 ;
        RECT 264.320 0.000 264.880 0.560 ;
    END
  END scramble_key_i[58]
  PIN scramble_key_i[59]
    DIRECTION INPUT ;
    USE SIGNAL ;
    PORT
      LAYER Metal2 ;
        RECT 268.800 0.000 269.360 0.560 ;
    END
  END scramble_key_i[59]
  PIN scramble_key_i[5]
    DIRECTION INPUT ;
    USE SIGNAL ;
    PORT
      LAYER Metal2 ;
        RECT 26.880 0.000 27.440 0.560 ;
    END
  END scramble_key_i[5]
  PIN scramble_key_i[60]
    DIRECTION INPUT ;
    USE SIGNAL ;
    PORT
      LAYER Metal2 ;
        RECT 273.280 0.000 273.840 0.560 ;
    END
  END scramble_key_i[60]
  PIN scramble_key_i[61]
    DIRECTION INPUT ;
    USE SIGNAL ;
    PORT
      LAYER Metal2 ;
        RECT 277.760 0.000 278.320 0.560 ;
    END
  END scramble_key_i[61]
  PIN scramble_key_i[62]
    DIRECTION INPUT ;
    USE SIGNAL ;
    PORT
      LAYER Metal2 ;
        RECT 282.240 0.000 282.800 0.560 ;
    END
  END scramble_key_i[62]
  PIN scramble_key_i[63]
    DIRECTION INPUT ;
    USE SIGNAL ;
    PORT
      LAYER Metal2 ;
        RECT 286.720 0.000 287.280 0.560 ;
    END
  END scramble_key_i[63]
  PIN scramble_key_i[64]
    DIRECTION INPUT ;
    USE SIGNAL ;
    PORT
      LAYER Metal2 ;
        RECT 291.200 0.000 291.760 0.560 ;
    END
  END scramble_key_i[64]
  PIN scramble_key_i[65]
    DIRECTION INPUT ;
    USE SIGNAL ;
    PORT
      LAYER Metal2 ;
        RECT 295.680 0.000 296.240 0.560 ;
    END
  END scramble_key_i[65]
  PIN scramble_key_i[66]
    DIRECTION INPUT ;
    USE SIGNAL ;
    PORT
      LAYER Metal2 ;
        RECT 300.160 0.000 300.720 0.560 ;
    END
  END scramble_key_i[66]
  PIN scramble_key_i[67]
    DIRECTION INPUT ;
    USE SIGNAL ;
    PORT
      LAYER Metal2 ;
        RECT 304.640 0.000 305.200 0.560 ;
    END
  END scramble_key_i[67]
  PIN scramble_key_i[68]
    DIRECTION INPUT ;
    USE SIGNAL ;
    PORT
      LAYER Metal2 ;
        RECT 309.120 0.000 309.680 0.560 ;
    END
  END scramble_key_i[68]
  PIN scramble_key_i[69]
    DIRECTION INPUT ;
    USE SIGNAL ;
    PORT
      LAYER Metal2 ;
        RECT 313.600 0.000 314.160 0.560 ;
    END
  END scramble_key_i[69]
  PIN scramble_key_i[6]
    DIRECTION INPUT ;
    USE SIGNAL ;
    PORT
      LAYER Metal2 ;
        RECT 31.360 0.000 31.920 0.560 ;
    END
  END scramble_key_i[6]
  PIN scramble_key_i[70]
    DIRECTION INPUT ;
    USE SIGNAL ;
    PORT
      LAYER Metal2 ;
        RECT 318.080 0.000 318.640 0.560 ;
    END
  END scramble_key_i[70]
  PIN scramble_key_i[71]
    DIRECTION INPUT ;
    USE SIGNAL ;
    PORT
      LAYER Metal2 ;
        RECT 322.560 0.000 323.120 0.560 ;
    END
  END scramble_key_i[71]
  PIN scramble_key_i[72]
    DIRECTION INPUT ;
    USE SIGNAL ;
    PORT
      LAYER Metal2 ;
        RECT 327.040 0.000 327.600 0.560 ;
    END
  END scramble_key_i[72]
  PIN scramble_key_i[73]
    DIRECTION INPUT ;
    USE SIGNAL ;
    PORT
      LAYER Metal2 ;
        RECT 331.520 0.000 332.080 0.560 ;
    END
  END scramble_key_i[73]
  PIN scramble_key_i[74]
    DIRECTION INPUT ;
    USE SIGNAL ;
    PORT
      LAYER Metal2 ;
        RECT 336.000 0.000 336.560 0.560 ;
    END
  END scramble_key_i[74]
  PIN scramble_key_i[75]
    DIRECTION INPUT ;
    USE SIGNAL ;
    PORT
      LAYER Metal2 ;
        RECT 340.480 0.000 341.040 0.560 ;
    END
  END scramble_key_i[75]
  PIN scramble_key_i[76]
    DIRECTION INPUT ;
    USE SIGNAL ;
    PORT
      LAYER Metal2 ;
        RECT 344.960 0.000 345.520 0.560 ;
    END
  END scramble_key_i[76]
  PIN scramble_key_i[77]
    DIRECTION INPUT ;
    USE SIGNAL ;
    PORT
      LAYER Metal2 ;
        RECT 349.440 0.000 350.000 0.560 ;
    END
  END scramble_key_i[77]
  PIN scramble_key_i[78]
    DIRECTION INPUT ;
    USE SIGNAL ;
    PORT
      LAYER Metal2 ;
        RECT 353.920 0.000 354.480 0.560 ;
    END
  END scramble_key_i[78]
  PIN scramble_key_i[79]
    DIRECTION INPUT ;
    USE SIGNAL ;
    PORT
      LAYER Metal2 ;
        RECT 358.400 0.000 358.960 0.560 ;
    END
  END scramble_key_i[79]
  PIN scramble_key_i[7]
    DIRECTION INPUT ;
    USE SIGNAL ;
    PORT
      LAYER Metal2 ;
        RECT 35.840 0.000 36.400 0.560 ;
    END
  END scramble_key_i[7]
  PIN scramble_key_i[80]
    DIRECTION INPUT ;
    USE SIGNAL ;
    PORT
      LAYER Metal2 ;
        RECT 362.880 0.000 363.440 0.560 ;
    END
  END scramble_key_i[80]
  PIN scramble_key_i[81]
    DIRECTION INPUT ;
    USE SIGNAL ;
    PORT
      LAYER Metal2 ;
        RECT 367.360 0.000 367.920 0.560 ;
    END
  END scramble_key_i[81]
  PIN scramble_key_i[82]
    DIRECTION INPUT ;
    USE SIGNAL ;
    PORT
      LAYER Metal2 ;
        RECT 371.840 0.000 372.400 0.560 ;
    END
  END scramble_key_i[82]
  PIN scramble_key_i[83]
    DIRECTION INPUT ;
    USE SIGNAL ;
    PORT
      LAYER Metal2 ;
        RECT 376.320 0.000 376.880 0.560 ;
    END
  END scramble_key_i[83]
  PIN scramble_key_i[84]
    DIRECTION INPUT ;
    USE SIGNAL ;
    PORT
      LAYER Metal2 ;
        RECT 380.800 0.000 381.360 0.560 ;
    END
  END scramble_key_i[84]
  PIN scramble_key_i[85]
    DIRECTION INPUT ;
    USE SIGNAL ;
    PORT
      LAYER Metal2 ;
        RECT 385.280 0.000 385.840 0.560 ;
    END
  END scramble_key_i[85]
  PIN scramble_key_i[86]
    DIRECTION INPUT ;
    USE SIGNAL ;
    PORT
      LAYER Metal2 ;
        RECT 389.760 0.000 390.320 0.560 ;
    END
  END scramble_key_i[86]
  PIN scramble_key_i[87]
    DIRECTION INPUT ;
    USE SIGNAL ;
    PORT
      LAYER Metal2 ;
        RECT 394.240 0.000 394.800 0.560 ;
    END
  END scramble_key_i[87]
  PIN scramble_key_i[88]
    DIRECTION INPUT ;
    USE SIGNAL ;
    PORT
      LAYER Metal2 ;
        RECT 398.720 0.000 399.280 0.560 ;
    END
  END scramble_key_i[88]
  PIN scramble_key_i[89]
    DIRECTION INPUT ;
    USE SIGNAL ;
    PORT
      LAYER Metal2 ;
        RECT 403.200 0.000 403.760 0.560 ;
    END
  END scramble_key_i[89]
  PIN scramble_key_i[8]
    DIRECTION INPUT ;
    USE SIGNAL ;
    PORT
      LAYER Metal2 ;
        RECT 40.320 0.000 40.880 0.560 ;
    END
  END scramble_key_i[8]
  PIN scramble_key_i[90]
    DIRECTION INPUT ;
    USE SIGNAL ;
    PORT
      LAYER Metal2 ;
        RECT 407.680 0.000 408.240 0.560 ;
    END
  END scramble_key_i[90]
  PIN scramble_key_i[91]
    DIRECTION INPUT ;
    USE SIGNAL ;
    PORT
      LAYER Metal2 ;
        RECT 412.160 0.000 412.720 0.560 ;
    END
  END scramble_key_i[91]
  PIN scramble_key_i[92]
    DIRECTION INPUT ;
    USE SIGNAL ;
    PORT
      LAYER Metal2 ;
        RECT 416.640 0.000 417.200 0.560 ;
    END
  END scramble_key_i[92]
  PIN scramble_key_i[93]
    DIRECTION INPUT ;
    USE SIGNAL ;
    PORT
      LAYER Metal2 ;
        RECT 421.120 0.000 421.680 0.560 ;
    END
  END scramble_key_i[93]
  PIN scramble_key_i[94]
    DIRECTION INPUT ;
    USE SIGNAL ;
    PORT
      LAYER Metal2 ;
        RECT 425.600 0.000 426.160 0.560 ;
    END
  END scramble_key_i[94]
  PIN scramble_key_i[95]
    DIRECTION INPUT ;
    USE SIGNAL ;
    PORT
      LAYER Metal2 ;
        RECT 430.080 0.000 430.640 0.560 ;
    END
  END scramble_key_i[95]
  PIN scramble_key_i[96]
    DIRECTION INPUT ;
    USE SIGNAL ;
    PORT
      LAYER Metal2 ;
        RECT 434.560 0.000 435.120 0.560 ;
    END
  END scramble_key_i[96]
  PIN scramble_key_i[97]
    DIRECTION INPUT ;
    USE SIGNAL ;
    PORT
      LAYER Metal2 ;
        RECT 439.040 0.000 439.600 0.560 ;
    END
  END scramble_key_i[97]
  PIN scramble_key_i[98]
    DIRECTION INPUT ;
    USE SIGNAL ;
    PORT
      LAYER Metal2 ;
        RECT 443.520 0.000 444.080 0.560 ;
    END
  END scramble_key_i[98]
  PIN scramble_key_i[99]
    DIRECTION INPUT ;
    USE SIGNAL ;
    PORT
      LAYER Metal2 ;
        RECT 448.000 0.000 448.560 0.560 ;
    END
  END scramble_key_i[99]
  PIN scramble_key_i[9]
    DIRECTION INPUT ;
    USE SIGNAL ;
    PORT
      LAYER Metal2 ;
        RECT 44.800 0.000 45.360 0.560 ;
    END
  END scramble_key_i[9]
  PIN scramble_key_valid_i
    DIRECTION INPUT ;
    USE SIGNAL ;
    PORT
      LAYER Metal2 ;
        RECT 577.920 0.000 578.480 0.560 ;
    END
  END scramble_key_valid_i
  PIN scramble_nonce_i[0]
    DIRECTION INPUT ;
    USE SIGNAL ;
    PORT
      LAYER Metal2 ;
        RECT 582.400 0.000 582.960 0.560 ;
    END
  END scramble_nonce_i[0]
  PIN scramble_nonce_i[10]
    DIRECTION INPUT ;
    USE SIGNAL ;
    PORT
      LAYER Metal2 ;
        RECT 627.200 0.000 627.760 0.560 ;
    END
  END scramble_nonce_i[10]
  PIN scramble_nonce_i[11]
    DIRECTION INPUT ;
    USE SIGNAL ;
    PORT
      LAYER Metal2 ;
        RECT 631.680 0.000 632.240 0.560 ;
    END
  END scramble_nonce_i[11]
  PIN scramble_nonce_i[12]
    DIRECTION INPUT ;
    USE SIGNAL ;
    PORT
      LAYER Metal2 ;
        RECT 636.160 0.000 636.720 0.560 ;
    END
  END scramble_nonce_i[12]
  PIN scramble_nonce_i[13]
    DIRECTION INPUT ;
    USE SIGNAL ;
    PORT
      LAYER Metal2 ;
        RECT 640.640 0.000 641.200 0.560 ;
    END
  END scramble_nonce_i[13]
  PIN scramble_nonce_i[14]
    DIRECTION INPUT ;
    USE SIGNAL ;
    PORT
      LAYER Metal2 ;
        RECT 645.120 0.000 645.680 0.560 ;
    END
  END scramble_nonce_i[14]
  PIN scramble_nonce_i[15]
    DIRECTION INPUT ;
    USE SIGNAL ;
    PORT
      LAYER Metal2 ;
        RECT 649.600 0.000 650.160 0.560 ;
    END
  END scramble_nonce_i[15]
  PIN scramble_nonce_i[16]
    DIRECTION INPUT ;
    USE SIGNAL ;
    PORT
      LAYER Metal2 ;
        RECT 654.080 0.000 654.640 0.560 ;
    END
  END scramble_nonce_i[16]
  PIN scramble_nonce_i[17]
    DIRECTION INPUT ;
    USE SIGNAL ;
    PORT
      LAYER Metal2 ;
        RECT 658.560 0.000 659.120 0.560 ;
    END
  END scramble_nonce_i[17]
  PIN scramble_nonce_i[18]
    DIRECTION INPUT ;
    USE SIGNAL ;
    PORT
      LAYER Metal2 ;
        RECT 663.040 0.000 663.600 0.560 ;
    END
  END scramble_nonce_i[18]
  PIN scramble_nonce_i[19]
    DIRECTION INPUT ;
    USE SIGNAL ;
    PORT
      LAYER Metal2 ;
        RECT 667.520 0.000 668.080 0.560 ;
    END
  END scramble_nonce_i[19]
  PIN scramble_nonce_i[1]
    DIRECTION INPUT ;
    USE SIGNAL ;
    PORT
      LAYER Metal2 ;
        RECT 586.880 0.000 587.440 0.560 ;
    END
  END scramble_nonce_i[1]
  PIN scramble_nonce_i[20]
    DIRECTION INPUT ;
    USE SIGNAL ;
    PORT
      LAYER Metal2 ;
        RECT 672.000 0.000 672.560 0.560 ;
    END
  END scramble_nonce_i[20]
  PIN scramble_nonce_i[21]
    DIRECTION INPUT ;
    USE SIGNAL ;
    PORT
      LAYER Metal2 ;
        RECT 676.480 0.000 677.040 0.560 ;
    END
  END scramble_nonce_i[21]
  PIN scramble_nonce_i[22]
    DIRECTION INPUT ;
    USE SIGNAL ;
    PORT
      LAYER Metal2 ;
        RECT 680.960 0.000 681.520 0.560 ;
    END
  END scramble_nonce_i[22]
  PIN scramble_nonce_i[23]
    DIRECTION INPUT ;
    USE SIGNAL ;
    PORT
      LAYER Metal2 ;
        RECT 685.440 0.000 686.000 0.560 ;
    END
  END scramble_nonce_i[23]
  PIN scramble_nonce_i[24]
    DIRECTION INPUT ;
    USE SIGNAL ;
    PORT
      LAYER Metal2 ;
        RECT 689.920 0.000 690.480 0.560 ;
    END
  END scramble_nonce_i[24]
  PIN scramble_nonce_i[25]
    DIRECTION INPUT ;
    USE SIGNAL ;
    PORT
      LAYER Metal2 ;
        RECT 694.400 0.000 694.960 0.560 ;
    END
  END scramble_nonce_i[25]
  PIN scramble_nonce_i[26]
    DIRECTION INPUT ;
    USE SIGNAL ;
    PORT
      LAYER Metal2 ;
        RECT 698.880 0.000 699.440 0.560 ;
    END
  END scramble_nonce_i[26]
  PIN scramble_nonce_i[27]
    DIRECTION INPUT ;
    USE SIGNAL ;
    PORT
      LAYER Metal2 ;
        RECT 703.360 0.000 703.920 0.560 ;
    END
  END scramble_nonce_i[27]
  PIN scramble_nonce_i[28]
    DIRECTION INPUT ;
    USE SIGNAL ;
    PORT
      LAYER Metal2 ;
        RECT 707.840 0.000 708.400 0.560 ;
    END
  END scramble_nonce_i[28]
  PIN scramble_nonce_i[29]
    DIRECTION INPUT ;
    USE SIGNAL ;
    PORT
      LAYER Metal2 ;
        RECT 712.320 0.000 712.880 0.560 ;
    END
  END scramble_nonce_i[29]
  PIN scramble_nonce_i[2]
    DIRECTION INPUT ;
    USE SIGNAL ;
    PORT
      LAYER Metal2 ;
        RECT 591.360 0.000 591.920 0.560 ;
    END
  END scramble_nonce_i[2]
  PIN scramble_nonce_i[30]
    DIRECTION INPUT ;
    USE SIGNAL ;
    PORT
      LAYER Metal2 ;
        RECT 716.800 0.000 717.360 0.560 ;
    END
  END scramble_nonce_i[30]
  PIN scramble_nonce_i[31]
    DIRECTION INPUT ;
    USE SIGNAL ;
    PORT
      LAYER Metal2 ;
        RECT 721.280 0.000 721.840 0.560 ;
    END
  END scramble_nonce_i[31]
  PIN scramble_nonce_i[32]
    DIRECTION INPUT ;
    USE SIGNAL ;
    PORT
      LAYER Metal2 ;
        RECT 725.760 0.000 726.320 0.560 ;
    END
  END scramble_nonce_i[32]
  PIN scramble_nonce_i[33]
    DIRECTION INPUT ;
    USE SIGNAL ;
    PORT
      LAYER Metal2 ;
        RECT 730.240 0.000 730.800 0.560 ;
    END
  END scramble_nonce_i[33]
  PIN scramble_nonce_i[34]
    DIRECTION INPUT ;
    USE SIGNAL ;
    PORT
      LAYER Metal2 ;
        RECT 734.720 0.000 735.280 0.560 ;
    END
  END scramble_nonce_i[34]
  PIN scramble_nonce_i[35]
    DIRECTION INPUT ;
    USE SIGNAL ;
    PORT
      LAYER Metal2 ;
        RECT 739.200 0.000 739.760 0.560 ;
    END
  END scramble_nonce_i[35]
  PIN scramble_nonce_i[36]
    DIRECTION INPUT ;
    USE SIGNAL ;
    PORT
      LAYER Metal2 ;
        RECT 743.680 0.000 744.240 0.560 ;
    END
  END scramble_nonce_i[36]
  PIN scramble_nonce_i[37]
    DIRECTION INPUT ;
    USE SIGNAL ;
    PORT
      LAYER Metal2 ;
        RECT 748.160 0.000 748.720 0.560 ;
    END
  END scramble_nonce_i[37]
  PIN scramble_nonce_i[38]
    DIRECTION INPUT ;
    USE SIGNAL ;
    PORT
      LAYER Metal2 ;
        RECT 752.640 0.000 753.200 0.560 ;
    END
  END scramble_nonce_i[38]
  PIN scramble_nonce_i[39]
    DIRECTION INPUT ;
    USE SIGNAL ;
    PORT
      LAYER Metal2 ;
        RECT 757.120 0.000 757.680 0.560 ;
    END
  END scramble_nonce_i[39]
  PIN scramble_nonce_i[3]
    DIRECTION INPUT ;
    USE SIGNAL ;
    PORT
      LAYER Metal2 ;
        RECT 595.840 0.000 596.400 0.560 ;
    END
  END scramble_nonce_i[3]
  PIN scramble_nonce_i[40]
    DIRECTION INPUT ;
    USE SIGNAL ;
    PORT
      LAYER Metal2 ;
        RECT 761.600 0.000 762.160 0.560 ;
    END
  END scramble_nonce_i[40]
  PIN scramble_nonce_i[41]
    DIRECTION INPUT ;
    USE SIGNAL ;
    PORT
      LAYER Metal2 ;
        RECT 766.080 0.000 766.640 0.560 ;
    END
  END scramble_nonce_i[41]
  PIN scramble_nonce_i[42]
    DIRECTION INPUT ;
    USE SIGNAL ;
    PORT
      LAYER Metal2 ;
        RECT 770.560 0.000 771.120 0.560 ;
    END
  END scramble_nonce_i[42]
  PIN scramble_nonce_i[43]
    DIRECTION INPUT ;
    USE SIGNAL ;
    PORT
      LAYER Metal2 ;
        RECT 775.040 0.000 775.600 0.560 ;
    END
  END scramble_nonce_i[43]
  PIN scramble_nonce_i[44]
    DIRECTION INPUT ;
    USE SIGNAL ;
    PORT
      LAYER Metal2 ;
        RECT 779.520 0.000 780.080 0.560 ;
    END
  END scramble_nonce_i[44]
  PIN scramble_nonce_i[45]
    DIRECTION INPUT ;
    USE SIGNAL ;
    PORT
      LAYER Metal2 ;
        RECT 784.000 0.000 784.560 0.560 ;
    END
  END scramble_nonce_i[45]
  PIN scramble_nonce_i[46]
    DIRECTION INPUT ;
    USE SIGNAL ;
    PORT
      LAYER Metal2 ;
        RECT 788.480 0.000 789.040 0.560 ;
    END
  END scramble_nonce_i[46]
  PIN scramble_nonce_i[47]
    DIRECTION INPUT ;
    USE SIGNAL ;
    PORT
      LAYER Metal2 ;
        RECT 792.960 0.000 793.520 0.560 ;
    END
  END scramble_nonce_i[47]
  PIN scramble_nonce_i[48]
    DIRECTION INPUT ;
    USE SIGNAL ;
    PORT
      LAYER Metal2 ;
        RECT 797.440 0.000 798.000 0.560 ;
    END
  END scramble_nonce_i[48]
  PIN scramble_nonce_i[49]
    DIRECTION INPUT ;
    USE SIGNAL ;
    PORT
      LAYER Metal2 ;
        RECT 801.920 0.000 802.480 0.560 ;
    END
  END scramble_nonce_i[49]
  PIN scramble_nonce_i[4]
    DIRECTION INPUT ;
    USE SIGNAL ;
    PORT
      LAYER Metal2 ;
        RECT 600.320 0.000 600.880 0.560 ;
    END
  END scramble_nonce_i[4]
  PIN scramble_nonce_i[50]
    DIRECTION INPUT ;
    USE SIGNAL ;
    PORT
      LAYER Metal2 ;
        RECT 806.400 0.000 806.960 0.560 ;
    END
  END scramble_nonce_i[50]
  PIN scramble_nonce_i[51]
    DIRECTION INPUT ;
    USE SIGNAL ;
    PORT
      LAYER Metal2 ;
        RECT 810.880 0.000 811.440 0.560 ;
    END
  END scramble_nonce_i[51]
  PIN scramble_nonce_i[52]
    DIRECTION INPUT ;
    USE SIGNAL ;
    PORT
      LAYER Metal2 ;
        RECT 815.360 0.000 815.920 0.560 ;
    END
  END scramble_nonce_i[52]
  PIN scramble_nonce_i[53]
    DIRECTION INPUT ;
    USE SIGNAL ;
    PORT
      LAYER Metal2 ;
        RECT 819.840 0.000 820.400 0.560 ;
    END
  END scramble_nonce_i[53]
  PIN scramble_nonce_i[54]
    DIRECTION INPUT ;
    USE SIGNAL ;
    PORT
      LAYER Metal2 ;
        RECT 824.320 0.000 824.880 0.560 ;
    END
  END scramble_nonce_i[54]
  PIN scramble_nonce_i[55]
    DIRECTION INPUT ;
    USE SIGNAL ;
    PORT
      LAYER Metal2 ;
        RECT 828.800 0.000 829.360 0.560 ;
    END
  END scramble_nonce_i[55]
  PIN scramble_nonce_i[56]
    DIRECTION INPUT ;
    USE SIGNAL ;
    PORT
      LAYER Metal2 ;
        RECT 833.280 0.000 833.840 0.560 ;
    END
  END scramble_nonce_i[56]
  PIN scramble_nonce_i[57]
    DIRECTION INPUT ;
    USE SIGNAL ;
    PORT
      LAYER Metal2 ;
        RECT 837.760 0.000 838.320 0.560 ;
    END
  END scramble_nonce_i[57]
  PIN scramble_nonce_i[58]
    DIRECTION INPUT ;
    USE SIGNAL ;
    PORT
      LAYER Metal2 ;
        RECT 842.240 0.000 842.800 0.560 ;
    END
  END scramble_nonce_i[58]
  PIN scramble_nonce_i[59]
    DIRECTION INPUT ;
    USE SIGNAL ;
    PORT
      LAYER Metal2 ;
        RECT 846.720 0.000 847.280 0.560 ;
    END
  END scramble_nonce_i[59]
  PIN scramble_nonce_i[5]
    DIRECTION INPUT ;
    USE SIGNAL ;
    PORT
      LAYER Metal2 ;
        RECT 604.800 0.000 605.360 0.560 ;
    END
  END scramble_nonce_i[5]
  PIN scramble_nonce_i[60]
    DIRECTION INPUT ;
    USE SIGNAL ;
    PORT
      LAYER Metal2 ;
        RECT 851.200 0.000 851.760 0.560 ;
    END
  END scramble_nonce_i[60]
  PIN scramble_nonce_i[61]
    DIRECTION INPUT ;
    USE SIGNAL ;
    PORT
      LAYER Metal2 ;
        RECT 855.680 0.000 856.240 0.560 ;
    END
  END scramble_nonce_i[61]
  PIN scramble_nonce_i[62]
    DIRECTION INPUT ;
    USE SIGNAL ;
    PORT
      LAYER Metal2 ;
        RECT 860.160 0.000 860.720 0.560 ;
    END
  END scramble_nonce_i[62]
  PIN scramble_nonce_i[63]
    DIRECTION INPUT ;
    USE SIGNAL ;
    PORT
      LAYER Metal2 ;
        RECT 864.640 0.000 865.200 0.560 ;
    END
  END scramble_nonce_i[63]
  PIN scramble_nonce_i[6]
    DIRECTION INPUT ;
    USE SIGNAL ;
    PORT
      LAYER Metal2 ;
        RECT 609.280 0.000 609.840 0.560 ;
    END
  END scramble_nonce_i[6]
  PIN scramble_nonce_i[7]
    DIRECTION INPUT ;
    USE SIGNAL ;
    PORT
      LAYER Metal2 ;
        RECT 613.760 0.000 614.320 0.560 ;
    END
  END scramble_nonce_i[7]
  PIN scramble_nonce_i[8]
    DIRECTION INPUT ;
    USE SIGNAL ;
    PORT
      LAYER Metal2 ;
        RECT 618.240 0.000 618.800 0.560 ;
    END
  END scramble_nonce_i[8]
  PIN scramble_nonce_i[9]
    DIRECTION INPUT ;
    USE SIGNAL ;
    PORT
      LAYER Metal2 ;
        RECT 622.720 0.000 623.280 0.560 ;
    END
  END scramble_nonce_i[9]
  PIN scramble_req_o
    DIRECTION OUTPUT ;
    USE SIGNAL ;
    ANTENNADIFFAREA 0.360800 ;
    PORT
      LAYER Metal2 ;
        RECT 869.120 0.000 869.680 0.560 ;
    END
  END scramble_req_o
  PIN test_en_i
    DIRECTION INPUT ;
    USE SIGNAL ;
    ANTENNAGATEAREA 0.396000 ;
    ANTENNADIFFAREA 0.410400 ;
    PORT
      LAYER Metal3 ;
        RECT 999.440 875.840 1000.000 876.400 ;
    END
  END test_en_i
  OBS
      LAYER Nwell ;
        RECT 6.290 15.250 993.310 984.350 ;
      LAYER Metal1 ;
        RECT 6.720 15.380 992.880 984.220 ;
      LAYER Metal2 ;
        RECT 22.380 999.140 124.020 999.860 ;
        RECT 125.180 999.140 127.380 999.860 ;
        RECT 128.540 999.140 130.740 999.860 ;
        RECT 131.900 999.140 134.100 999.860 ;
        RECT 135.260 999.140 137.460 999.860 ;
        RECT 138.620 999.140 140.820 999.860 ;
        RECT 141.980 999.140 144.180 999.860 ;
        RECT 145.340 999.140 147.540 999.860 ;
        RECT 148.700 999.140 150.900 999.860 ;
        RECT 152.060 999.140 154.260 999.860 ;
        RECT 155.420 999.140 157.620 999.860 ;
        RECT 158.780 999.140 160.980 999.860 ;
        RECT 162.140 999.140 164.340 999.860 ;
        RECT 165.500 999.140 167.700 999.860 ;
        RECT 168.860 999.140 171.060 999.860 ;
        RECT 172.220 999.140 174.420 999.860 ;
        RECT 175.580 999.140 177.780 999.860 ;
        RECT 178.940 999.140 181.140 999.860 ;
        RECT 182.300 999.140 184.500 999.860 ;
        RECT 185.660 999.140 187.860 999.860 ;
        RECT 189.020 999.140 191.220 999.860 ;
        RECT 192.380 999.140 194.580 999.860 ;
        RECT 195.740 999.140 197.940 999.860 ;
        RECT 199.100 999.140 201.300 999.860 ;
        RECT 202.460 999.140 204.660 999.860 ;
        RECT 205.820 999.140 208.020 999.860 ;
        RECT 209.180 999.140 211.380 999.860 ;
        RECT 212.540 999.140 214.740 999.860 ;
        RECT 215.900 999.140 218.100 999.860 ;
        RECT 219.260 999.140 221.460 999.860 ;
        RECT 222.620 999.140 224.820 999.860 ;
        RECT 225.980 999.140 228.180 999.860 ;
        RECT 229.340 999.140 231.540 999.860 ;
        RECT 232.700 999.140 234.900 999.860 ;
        RECT 236.060 999.140 238.260 999.860 ;
        RECT 239.420 999.140 241.620 999.860 ;
        RECT 242.780 999.140 244.980 999.860 ;
        RECT 246.140 999.140 248.340 999.860 ;
        RECT 249.500 999.140 251.700 999.860 ;
        RECT 252.860 999.140 255.060 999.860 ;
        RECT 256.220 999.140 258.420 999.860 ;
        RECT 259.580 999.140 261.780 999.860 ;
        RECT 262.940 999.140 265.140 999.860 ;
        RECT 266.300 999.140 268.500 999.860 ;
        RECT 269.660 999.140 271.860 999.860 ;
        RECT 273.020 999.140 275.220 999.860 ;
        RECT 276.380 999.140 278.580 999.860 ;
        RECT 279.740 999.140 281.940 999.860 ;
        RECT 283.100 999.140 285.300 999.860 ;
        RECT 286.460 999.140 288.660 999.860 ;
        RECT 289.820 999.140 292.020 999.860 ;
        RECT 293.180 999.140 295.380 999.860 ;
        RECT 296.540 999.140 298.740 999.860 ;
        RECT 299.900 999.140 302.100 999.860 ;
        RECT 303.260 999.140 305.460 999.860 ;
        RECT 306.620 999.140 308.820 999.860 ;
        RECT 309.980 999.140 312.180 999.860 ;
        RECT 313.340 999.140 315.540 999.860 ;
        RECT 316.700 999.140 318.900 999.860 ;
        RECT 320.060 999.140 322.260 999.860 ;
        RECT 323.420 999.140 325.620 999.860 ;
        RECT 326.780 999.140 328.980 999.860 ;
        RECT 330.140 999.140 332.340 999.860 ;
        RECT 333.500 999.140 335.700 999.860 ;
        RECT 336.860 999.140 339.060 999.860 ;
        RECT 340.220 999.140 342.420 999.860 ;
        RECT 343.580 999.140 345.780 999.860 ;
        RECT 346.940 999.140 349.140 999.860 ;
        RECT 350.300 999.140 352.500 999.860 ;
        RECT 353.660 999.140 355.860 999.860 ;
        RECT 357.020 999.140 359.220 999.860 ;
        RECT 360.380 999.140 362.580 999.860 ;
        RECT 363.740 999.140 365.940 999.860 ;
        RECT 367.100 999.140 369.300 999.860 ;
        RECT 370.460 999.140 372.660 999.860 ;
        RECT 373.820 999.140 376.020 999.860 ;
        RECT 377.180 999.140 379.380 999.860 ;
        RECT 380.540 999.140 382.740 999.860 ;
        RECT 383.900 999.140 386.100 999.860 ;
        RECT 387.260 999.140 389.460 999.860 ;
        RECT 390.620 999.140 392.820 999.860 ;
        RECT 393.980 999.140 396.180 999.860 ;
        RECT 397.340 999.140 399.540 999.860 ;
        RECT 400.700 999.140 402.900 999.860 ;
        RECT 404.060 999.140 406.260 999.860 ;
        RECT 407.420 999.140 409.620 999.860 ;
        RECT 410.780 999.140 412.980 999.860 ;
        RECT 414.140 999.140 416.340 999.860 ;
        RECT 417.500 999.140 419.700 999.860 ;
        RECT 420.860 999.140 423.060 999.860 ;
        RECT 424.220 999.140 426.420 999.860 ;
        RECT 427.580 999.140 429.780 999.860 ;
        RECT 430.940 999.140 433.140 999.860 ;
        RECT 434.300 999.140 436.500 999.860 ;
        RECT 437.660 999.140 439.860 999.860 ;
        RECT 441.020 999.140 443.220 999.860 ;
        RECT 444.380 999.140 446.580 999.860 ;
        RECT 447.740 999.140 449.940 999.860 ;
        RECT 451.100 999.140 453.300 999.860 ;
        RECT 454.460 999.140 456.660 999.860 ;
        RECT 457.820 999.140 460.020 999.860 ;
        RECT 461.180 999.140 463.380 999.860 ;
        RECT 464.540 999.140 466.740 999.860 ;
        RECT 467.900 999.140 470.100 999.860 ;
        RECT 471.260 999.140 473.460 999.860 ;
        RECT 474.620 999.140 476.820 999.860 ;
        RECT 477.980 999.140 480.180 999.860 ;
        RECT 481.340 999.140 483.540 999.860 ;
        RECT 484.700 999.140 486.900 999.860 ;
        RECT 488.060 999.140 490.260 999.860 ;
        RECT 491.420 999.140 493.620 999.860 ;
        RECT 494.780 999.140 496.980 999.860 ;
        RECT 498.140 999.140 500.340 999.860 ;
        RECT 501.500 999.140 503.700 999.860 ;
        RECT 504.860 999.140 507.060 999.860 ;
        RECT 508.220 999.140 510.420 999.860 ;
        RECT 511.580 999.140 513.780 999.860 ;
        RECT 514.940 999.140 517.140 999.860 ;
        RECT 518.300 999.140 520.500 999.860 ;
        RECT 521.660 999.140 523.860 999.860 ;
        RECT 525.020 999.140 527.220 999.860 ;
        RECT 528.380 999.140 530.580 999.860 ;
        RECT 531.740 999.140 533.940 999.860 ;
        RECT 535.100 999.140 537.300 999.860 ;
        RECT 538.460 999.140 540.660 999.860 ;
        RECT 541.820 999.140 544.020 999.860 ;
        RECT 545.180 999.140 547.380 999.860 ;
        RECT 548.540 999.140 550.740 999.860 ;
        RECT 551.900 999.140 554.100 999.860 ;
        RECT 555.260 999.140 557.460 999.860 ;
        RECT 558.620 999.140 560.820 999.860 ;
        RECT 561.980 999.140 564.180 999.860 ;
        RECT 565.340 999.140 567.540 999.860 ;
        RECT 568.700 999.140 570.900 999.860 ;
        RECT 572.060 999.140 574.260 999.860 ;
        RECT 575.420 999.140 577.620 999.860 ;
        RECT 578.780 999.140 580.980 999.860 ;
        RECT 582.140 999.140 584.340 999.860 ;
        RECT 585.500 999.140 587.700 999.860 ;
        RECT 588.860 999.140 591.060 999.860 ;
        RECT 592.220 999.140 594.420 999.860 ;
        RECT 595.580 999.140 597.780 999.860 ;
        RECT 598.940 999.140 601.140 999.860 ;
        RECT 602.300 999.140 604.500 999.860 ;
        RECT 605.660 999.140 607.860 999.860 ;
        RECT 609.020 999.140 611.220 999.860 ;
        RECT 612.380 999.140 614.580 999.860 ;
        RECT 615.740 999.140 617.940 999.860 ;
        RECT 619.100 999.140 621.300 999.860 ;
        RECT 622.460 999.140 624.660 999.860 ;
        RECT 625.820 999.140 628.020 999.860 ;
        RECT 629.180 999.140 631.380 999.860 ;
        RECT 632.540 999.140 634.740 999.860 ;
        RECT 635.900 999.140 638.100 999.860 ;
        RECT 639.260 999.140 641.460 999.860 ;
        RECT 642.620 999.140 644.820 999.860 ;
        RECT 645.980 999.140 648.180 999.860 ;
        RECT 649.340 999.140 651.540 999.860 ;
        RECT 652.700 999.140 654.900 999.860 ;
        RECT 656.060 999.140 658.260 999.860 ;
        RECT 659.420 999.140 661.620 999.860 ;
        RECT 662.780 999.140 664.980 999.860 ;
        RECT 666.140 999.140 668.340 999.860 ;
        RECT 669.500 999.140 671.700 999.860 ;
        RECT 672.860 999.140 675.060 999.860 ;
        RECT 676.220 999.140 678.420 999.860 ;
        RECT 679.580 999.140 681.780 999.860 ;
        RECT 682.940 999.140 685.140 999.860 ;
        RECT 686.300 999.140 688.500 999.860 ;
        RECT 689.660 999.140 691.860 999.860 ;
        RECT 693.020 999.140 695.220 999.860 ;
        RECT 696.380 999.140 698.580 999.860 ;
        RECT 699.740 999.140 701.940 999.860 ;
        RECT 703.100 999.140 705.300 999.860 ;
        RECT 706.460 999.140 708.660 999.860 ;
        RECT 709.820 999.140 712.020 999.860 ;
        RECT 713.180 999.140 715.380 999.860 ;
        RECT 716.540 999.140 718.740 999.860 ;
        RECT 719.900 999.140 722.100 999.860 ;
        RECT 723.260 999.140 725.460 999.860 ;
        RECT 726.620 999.140 728.820 999.860 ;
        RECT 729.980 999.140 732.180 999.860 ;
        RECT 733.340 999.140 735.540 999.860 ;
        RECT 736.700 999.140 738.900 999.860 ;
        RECT 740.060 999.140 742.260 999.860 ;
        RECT 743.420 999.140 745.620 999.860 ;
        RECT 746.780 999.140 748.980 999.860 ;
        RECT 750.140 999.140 752.340 999.860 ;
        RECT 753.500 999.140 755.700 999.860 ;
        RECT 756.860 999.140 759.060 999.860 ;
        RECT 760.220 999.140 762.420 999.860 ;
        RECT 763.580 999.140 765.780 999.860 ;
        RECT 766.940 999.140 769.140 999.860 ;
        RECT 770.300 999.140 772.500 999.860 ;
        RECT 773.660 999.140 775.860 999.860 ;
        RECT 777.020 999.140 779.220 999.860 ;
        RECT 780.380 999.140 782.580 999.860 ;
        RECT 783.740 999.140 785.940 999.860 ;
        RECT 787.100 999.140 789.300 999.860 ;
        RECT 790.460 999.140 792.660 999.860 ;
        RECT 793.820 999.140 796.020 999.860 ;
        RECT 797.180 999.140 799.380 999.860 ;
        RECT 800.540 999.140 802.740 999.860 ;
        RECT 803.900 999.140 806.100 999.860 ;
        RECT 807.260 999.140 809.460 999.860 ;
        RECT 810.620 999.140 812.820 999.860 ;
        RECT 813.980 999.140 816.180 999.860 ;
        RECT 817.340 999.140 819.540 999.860 ;
        RECT 820.700 999.140 822.900 999.860 ;
        RECT 824.060 999.140 826.260 999.860 ;
        RECT 827.420 999.140 829.620 999.860 ;
        RECT 830.780 999.140 832.980 999.860 ;
        RECT 834.140 999.140 836.340 999.860 ;
        RECT 837.500 999.140 839.700 999.860 ;
        RECT 840.860 999.140 843.060 999.860 ;
        RECT 844.220 999.140 846.420 999.860 ;
        RECT 847.580 999.140 849.780 999.860 ;
        RECT 850.940 999.140 853.140 999.860 ;
        RECT 854.300 999.140 856.500 999.860 ;
        RECT 857.660 999.140 859.860 999.860 ;
        RECT 861.020 999.140 863.220 999.860 ;
        RECT 864.380 999.140 866.580 999.860 ;
        RECT 867.740 999.140 869.940 999.860 ;
        RECT 871.100 999.140 873.300 999.860 ;
        RECT 874.460 999.140 999.460 999.860 ;
        RECT 22.380 0.860 999.460 999.140 ;
        RECT 23.260 0.560 26.580 0.860 ;
        RECT 27.740 0.560 31.060 0.860 ;
        RECT 32.220 0.560 35.540 0.860 ;
        RECT 36.700 0.560 40.020 0.860 ;
        RECT 41.180 0.560 44.500 0.860 ;
        RECT 45.660 0.560 48.980 0.860 ;
        RECT 50.140 0.560 53.460 0.860 ;
        RECT 54.620 0.560 57.940 0.860 ;
        RECT 59.100 0.560 62.420 0.860 ;
        RECT 63.580 0.560 66.900 0.860 ;
        RECT 68.060 0.560 71.380 0.860 ;
        RECT 72.540 0.560 75.860 0.860 ;
        RECT 77.020 0.560 80.340 0.860 ;
        RECT 81.500 0.560 84.820 0.860 ;
        RECT 85.980 0.560 89.300 0.860 ;
        RECT 90.460 0.560 93.780 0.860 ;
        RECT 94.940 0.560 98.260 0.860 ;
        RECT 99.420 0.560 102.740 0.860 ;
        RECT 103.900 0.560 107.220 0.860 ;
        RECT 108.380 0.560 111.700 0.860 ;
        RECT 112.860 0.560 116.180 0.860 ;
        RECT 117.340 0.560 120.660 0.860 ;
        RECT 121.820 0.560 125.140 0.860 ;
        RECT 126.300 0.560 129.620 0.860 ;
        RECT 130.780 0.560 134.100 0.860 ;
        RECT 135.260 0.560 138.580 0.860 ;
        RECT 139.740 0.560 143.060 0.860 ;
        RECT 144.220 0.560 147.540 0.860 ;
        RECT 148.700 0.560 152.020 0.860 ;
        RECT 153.180 0.560 156.500 0.860 ;
        RECT 157.660 0.560 160.980 0.860 ;
        RECT 162.140 0.560 165.460 0.860 ;
        RECT 166.620 0.560 169.940 0.860 ;
        RECT 171.100 0.560 174.420 0.860 ;
        RECT 175.580 0.560 178.900 0.860 ;
        RECT 180.060 0.560 183.380 0.860 ;
        RECT 184.540 0.560 187.860 0.860 ;
        RECT 189.020 0.560 192.340 0.860 ;
        RECT 193.500 0.560 196.820 0.860 ;
        RECT 197.980 0.560 201.300 0.860 ;
        RECT 202.460 0.560 205.780 0.860 ;
        RECT 206.940 0.560 210.260 0.860 ;
        RECT 211.420 0.560 214.740 0.860 ;
        RECT 215.900 0.560 219.220 0.860 ;
        RECT 220.380 0.560 223.700 0.860 ;
        RECT 224.860 0.560 228.180 0.860 ;
        RECT 229.340 0.560 232.660 0.860 ;
        RECT 233.820 0.560 237.140 0.860 ;
        RECT 238.300 0.560 241.620 0.860 ;
        RECT 242.780 0.560 246.100 0.860 ;
        RECT 247.260 0.560 250.580 0.860 ;
        RECT 251.740 0.560 255.060 0.860 ;
        RECT 256.220 0.560 259.540 0.860 ;
        RECT 260.700 0.560 264.020 0.860 ;
        RECT 265.180 0.560 268.500 0.860 ;
        RECT 269.660 0.560 272.980 0.860 ;
        RECT 274.140 0.560 277.460 0.860 ;
        RECT 278.620 0.560 281.940 0.860 ;
        RECT 283.100 0.560 286.420 0.860 ;
        RECT 287.580 0.560 290.900 0.860 ;
        RECT 292.060 0.560 295.380 0.860 ;
        RECT 296.540 0.560 299.860 0.860 ;
        RECT 301.020 0.560 304.340 0.860 ;
        RECT 305.500 0.560 308.820 0.860 ;
        RECT 309.980 0.560 313.300 0.860 ;
        RECT 314.460 0.560 317.780 0.860 ;
        RECT 318.940 0.560 322.260 0.860 ;
        RECT 323.420 0.560 326.740 0.860 ;
        RECT 327.900 0.560 331.220 0.860 ;
        RECT 332.380 0.560 335.700 0.860 ;
        RECT 336.860 0.560 340.180 0.860 ;
        RECT 341.340 0.560 344.660 0.860 ;
        RECT 345.820 0.560 349.140 0.860 ;
        RECT 350.300 0.560 353.620 0.860 ;
        RECT 354.780 0.560 358.100 0.860 ;
        RECT 359.260 0.560 362.580 0.860 ;
        RECT 363.740 0.560 367.060 0.860 ;
        RECT 368.220 0.560 371.540 0.860 ;
        RECT 372.700 0.560 376.020 0.860 ;
        RECT 377.180 0.560 380.500 0.860 ;
        RECT 381.660 0.560 384.980 0.860 ;
        RECT 386.140 0.560 389.460 0.860 ;
        RECT 390.620 0.560 393.940 0.860 ;
        RECT 395.100 0.560 398.420 0.860 ;
        RECT 399.580 0.560 402.900 0.860 ;
        RECT 404.060 0.560 407.380 0.860 ;
        RECT 408.540 0.560 411.860 0.860 ;
        RECT 413.020 0.560 416.340 0.860 ;
        RECT 417.500 0.560 420.820 0.860 ;
        RECT 421.980 0.560 425.300 0.860 ;
        RECT 426.460 0.560 429.780 0.860 ;
        RECT 430.940 0.560 434.260 0.860 ;
        RECT 435.420 0.560 438.740 0.860 ;
        RECT 439.900 0.560 443.220 0.860 ;
        RECT 444.380 0.560 447.700 0.860 ;
        RECT 448.860 0.560 452.180 0.860 ;
        RECT 453.340 0.560 456.660 0.860 ;
        RECT 457.820 0.560 461.140 0.860 ;
        RECT 462.300 0.560 465.620 0.860 ;
        RECT 466.780 0.560 470.100 0.860 ;
        RECT 471.260 0.560 474.580 0.860 ;
        RECT 475.740 0.560 479.060 0.860 ;
        RECT 480.220 0.560 483.540 0.860 ;
        RECT 484.700 0.560 488.020 0.860 ;
        RECT 489.180 0.560 492.500 0.860 ;
        RECT 493.660 0.560 496.980 0.860 ;
        RECT 498.140 0.560 501.460 0.860 ;
        RECT 502.620 0.560 505.940 0.860 ;
        RECT 507.100 0.560 510.420 0.860 ;
        RECT 511.580 0.560 514.900 0.860 ;
        RECT 516.060 0.560 519.380 0.860 ;
        RECT 520.540 0.560 523.860 0.860 ;
        RECT 525.020 0.560 528.340 0.860 ;
        RECT 529.500 0.560 532.820 0.860 ;
        RECT 533.980 0.560 537.300 0.860 ;
        RECT 538.460 0.560 541.780 0.860 ;
        RECT 542.940 0.560 546.260 0.860 ;
        RECT 547.420 0.560 550.740 0.860 ;
        RECT 551.900 0.560 555.220 0.860 ;
        RECT 556.380 0.560 559.700 0.860 ;
        RECT 560.860 0.560 564.180 0.860 ;
        RECT 565.340 0.560 568.660 0.860 ;
        RECT 569.820 0.560 573.140 0.860 ;
        RECT 574.300 0.560 577.620 0.860 ;
        RECT 578.780 0.560 582.100 0.860 ;
        RECT 583.260 0.560 586.580 0.860 ;
        RECT 587.740 0.560 591.060 0.860 ;
        RECT 592.220 0.560 595.540 0.860 ;
        RECT 596.700 0.560 600.020 0.860 ;
        RECT 601.180 0.560 604.500 0.860 ;
        RECT 605.660 0.560 608.980 0.860 ;
        RECT 610.140 0.560 613.460 0.860 ;
        RECT 614.620 0.560 617.940 0.860 ;
        RECT 619.100 0.560 622.420 0.860 ;
        RECT 623.580 0.560 626.900 0.860 ;
        RECT 628.060 0.560 631.380 0.860 ;
        RECT 632.540 0.560 635.860 0.860 ;
        RECT 637.020 0.560 640.340 0.860 ;
        RECT 641.500 0.560 644.820 0.860 ;
        RECT 645.980 0.560 649.300 0.860 ;
        RECT 650.460 0.560 653.780 0.860 ;
        RECT 654.940 0.560 658.260 0.860 ;
        RECT 659.420 0.560 662.740 0.860 ;
        RECT 663.900 0.560 667.220 0.860 ;
        RECT 668.380 0.560 671.700 0.860 ;
        RECT 672.860 0.560 676.180 0.860 ;
        RECT 677.340 0.560 680.660 0.860 ;
        RECT 681.820 0.560 685.140 0.860 ;
        RECT 686.300 0.560 689.620 0.860 ;
        RECT 690.780 0.560 694.100 0.860 ;
        RECT 695.260 0.560 698.580 0.860 ;
        RECT 699.740 0.560 703.060 0.860 ;
        RECT 704.220 0.560 707.540 0.860 ;
        RECT 708.700 0.560 712.020 0.860 ;
        RECT 713.180 0.560 716.500 0.860 ;
        RECT 717.660 0.560 720.980 0.860 ;
        RECT 722.140 0.560 725.460 0.860 ;
        RECT 726.620 0.560 729.940 0.860 ;
        RECT 731.100 0.560 734.420 0.860 ;
        RECT 735.580 0.560 738.900 0.860 ;
        RECT 740.060 0.560 743.380 0.860 ;
        RECT 744.540 0.560 747.860 0.860 ;
        RECT 749.020 0.560 752.340 0.860 ;
        RECT 753.500 0.560 756.820 0.860 ;
        RECT 757.980 0.560 761.300 0.860 ;
        RECT 762.460 0.560 765.780 0.860 ;
        RECT 766.940 0.560 770.260 0.860 ;
        RECT 771.420 0.560 774.740 0.860 ;
        RECT 775.900 0.560 779.220 0.860 ;
        RECT 780.380 0.560 783.700 0.860 ;
        RECT 784.860 0.560 788.180 0.860 ;
        RECT 789.340 0.560 792.660 0.860 ;
        RECT 793.820 0.560 797.140 0.860 ;
        RECT 798.300 0.560 801.620 0.860 ;
        RECT 802.780 0.560 806.100 0.860 ;
        RECT 807.260 0.560 810.580 0.860 ;
        RECT 811.740 0.560 815.060 0.860 ;
        RECT 816.220 0.560 819.540 0.860 ;
        RECT 820.700 0.560 824.020 0.860 ;
        RECT 825.180 0.560 828.500 0.860 ;
        RECT 829.660 0.560 832.980 0.860 ;
        RECT 834.140 0.560 837.460 0.860 ;
        RECT 838.620 0.560 841.940 0.860 ;
        RECT 843.100 0.560 846.420 0.860 ;
        RECT 847.580 0.560 850.900 0.860 ;
        RECT 852.060 0.560 855.380 0.860 ;
        RECT 856.540 0.560 859.860 0.860 ;
        RECT 861.020 0.560 864.340 0.860 ;
        RECT 865.500 0.560 868.820 0.860 ;
        RECT 869.980 0.560 873.300 0.860 ;
        RECT 874.460 0.560 877.780 0.860 ;
        RECT 878.940 0.560 882.260 0.860 ;
        RECT 883.420 0.560 886.740 0.860 ;
        RECT 887.900 0.560 891.220 0.860 ;
        RECT 892.380 0.560 895.700 0.860 ;
        RECT 896.860 0.560 900.180 0.860 ;
        RECT 901.340 0.560 904.660 0.860 ;
        RECT 905.820 0.560 909.140 0.860 ;
        RECT 910.300 0.560 913.620 0.860 ;
        RECT 914.780 0.560 918.100 0.860 ;
        RECT 919.260 0.560 922.580 0.860 ;
        RECT 923.740 0.560 927.060 0.860 ;
        RECT 928.220 0.560 931.540 0.860 ;
        RECT 932.700 0.560 936.020 0.860 ;
        RECT 937.180 0.560 940.500 0.860 ;
        RECT 941.660 0.560 944.980 0.860 ;
        RECT 946.140 0.560 949.460 0.860 ;
        RECT 950.620 0.560 953.940 0.860 ;
        RECT 955.100 0.560 958.420 0.860 ;
        RECT 959.580 0.560 962.900 0.860 ;
        RECT 964.060 0.560 967.380 0.860 ;
        RECT 968.540 0.560 971.860 0.860 ;
        RECT 973.020 0.560 976.340 0.860 ;
        RECT 977.500 0.560 980.820 0.860 ;
        RECT 981.980 0.560 985.300 0.860 ;
        RECT 986.460 0.560 989.780 0.860 ;
        RECT 990.940 0.560 994.260 0.860 ;
        RECT 995.420 0.560 999.460 0.860 ;
      LAYER Metal3 ;
        RECT 22.330 880.060 999.860 999.460 ;
        RECT 22.330 878.900 999.140 880.060 ;
        RECT 22.330 876.700 999.860 878.900 ;
        RECT 22.330 875.540 999.140 876.700 ;
        RECT 22.330 873.340 999.860 875.540 ;
        RECT 22.330 872.180 999.140 873.340 ;
        RECT 22.330 869.980 999.860 872.180 ;
        RECT 22.330 868.820 999.140 869.980 ;
        RECT 22.330 866.620 999.860 868.820 ;
        RECT 22.330 865.460 999.140 866.620 ;
        RECT 22.330 863.260 999.860 865.460 ;
        RECT 22.330 862.100 999.140 863.260 ;
        RECT 22.330 859.900 999.860 862.100 ;
        RECT 22.330 858.740 999.140 859.900 ;
        RECT 22.330 856.540 999.860 858.740 ;
        RECT 22.330 855.380 999.140 856.540 ;
        RECT 22.330 853.180 999.860 855.380 ;
        RECT 22.330 852.020 999.140 853.180 ;
        RECT 22.330 849.820 999.860 852.020 ;
        RECT 22.330 848.660 999.140 849.820 ;
        RECT 22.330 846.460 999.860 848.660 ;
        RECT 22.330 845.300 999.140 846.460 ;
        RECT 22.330 843.100 999.860 845.300 ;
        RECT 22.330 841.940 999.140 843.100 ;
        RECT 22.330 839.740 999.860 841.940 ;
        RECT 22.330 838.580 999.140 839.740 ;
        RECT 22.330 836.380 999.860 838.580 ;
        RECT 22.330 835.220 999.140 836.380 ;
        RECT 22.330 833.020 999.860 835.220 ;
        RECT 22.330 831.860 999.140 833.020 ;
        RECT 22.330 829.660 999.860 831.860 ;
        RECT 22.330 828.500 999.140 829.660 ;
        RECT 22.330 826.300 999.860 828.500 ;
        RECT 22.330 825.140 999.140 826.300 ;
        RECT 22.330 822.940 999.860 825.140 ;
        RECT 22.330 821.780 999.140 822.940 ;
        RECT 22.330 819.580 999.860 821.780 ;
        RECT 22.330 818.420 999.140 819.580 ;
        RECT 22.330 816.220 999.860 818.420 ;
        RECT 22.330 815.060 999.140 816.220 ;
        RECT 22.330 812.860 999.860 815.060 ;
        RECT 22.330 811.700 999.140 812.860 ;
        RECT 22.330 809.500 999.860 811.700 ;
        RECT 22.330 808.340 999.140 809.500 ;
        RECT 22.330 806.140 999.860 808.340 ;
        RECT 22.330 804.980 999.140 806.140 ;
        RECT 22.330 802.780 999.860 804.980 ;
        RECT 22.330 801.620 999.140 802.780 ;
        RECT 22.330 799.420 999.860 801.620 ;
        RECT 22.330 798.260 999.140 799.420 ;
        RECT 22.330 796.060 999.860 798.260 ;
        RECT 22.330 794.900 999.140 796.060 ;
        RECT 22.330 792.700 999.860 794.900 ;
        RECT 22.330 791.540 999.140 792.700 ;
        RECT 22.330 789.340 999.860 791.540 ;
        RECT 22.330 788.180 999.140 789.340 ;
        RECT 22.330 785.980 999.860 788.180 ;
        RECT 22.330 784.820 999.140 785.980 ;
        RECT 22.330 782.620 999.860 784.820 ;
        RECT 22.330 781.460 999.140 782.620 ;
        RECT 22.330 779.260 999.860 781.460 ;
        RECT 22.330 778.100 999.140 779.260 ;
        RECT 22.330 775.900 999.860 778.100 ;
        RECT 22.330 774.740 999.140 775.900 ;
        RECT 22.330 772.540 999.860 774.740 ;
        RECT 22.330 771.380 999.140 772.540 ;
        RECT 22.330 769.180 999.860 771.380 ;
        RECT 22.330 768.020 999.140 769.180 ;
        RECT 22.330 765.820 999.860 768.020 ;
        RECT 22.330 764.660 999.140 765.820 ;
        RECT 22.330 762.460 999.860 764.660 ;
        RECT 22.330 761.300 999.140 762.460 ;
        RECT 22.330 759.100 999.860 761.300 ;
        RECT 22.330 757.940 999.140 759.100 ;
        RECT 22.330 755.740 999.860 757.940 ;
        RECT 22.330 754.580 999.140 755.740 ;
        RECT 22.330 752.380 999.860 754.580 ;
        RECT 22.330 751.220 999.140 752.380 ;
        RECT 22.330 749.020 999.860 751.220 ;
        RECT 22.330 747.860 999.140 749.020 ;
        RECT 22.330 745.660 999.860 747.860 ;
        RECT 22.330 744.500 999.140 745.660 ;
        RECT 22.330 742.300 999.860 744.500 ;
        RECT 22.330 741.140 999.140 742.300 ;
        RECT 22.330 738.940 999.860 741.140 ;
        RECT 22.330 737.780 999.140 738.940 ;
        RECT 22.330 735.580 999.860 737.780 ;
        RECT 22.330 734.420 999.140 735.580 ;
        RECT 22.330 732.220 999.860 734.420 ;
        RECT 22.330 731.060 999.140 732.220 ;
        RECT 22.330 728.860 999.860 731.060 ;
        RECT 22.330 727.700 999.140 728.860 ;
        RECT 22.330 725.500 999.860 727.700 ;
        RECT 22.330 724.340 999.140 725.500 ;
        RECT 22.330 722.140 999.860 724.340 ;
        RECT 22.330 720.980 999.140 722.140 ;
        RECT 22.330 718.780 999.860 720.980 ;
        RECT 22.330 717.620 999.140 718.780 ;
        RECT 22.330 715.420 999.860 717.620 ;
        RECT 22.330 714.260 999.140 715.420 ;
        RECT 22.330 712.060 999.860 714.260 ;
        RECT 22.330 710.900 999.140 712.060 ;
        RECT 22.330 708.700 999.860 710.900 ;
        RECT 22.330 707.540 999.140 708.700 ;
        RECT 22.330 705.340 999.860 707.540 ;
        RECT 22.330 704.180 999.140 705.340 ;
        RECT 22.330 701.980 999.860 704.180 ;
        RECT 22.330 700.820 999.140 701.980 ;
        RECT 22.330 698.620 999.860 700.820 ;
        RECT 22.330 697.460 999.140 698.620 ;
        RECT 22.330 695.260 999.860 697.460 ;
        RECT 22.330 694.100 999.140 695.260 ;
        RECT 22.330 691.900 999.860 694.100 ;
        RECT 22.330 690.740 999.140 691.900 ;
        RECT 22.330 688.540 999.860 690.740 ;
        RECT 22.330 687.380 999.140 688.540 ;
        RECT 22.330 685.180 999.860 687.380 ;
        RECT 22.330 684.020 999.140 685.180 ;
        RECT 22.330 681.820 999.860 684.020 ;
        RECT 22.330 680.660 999.140 681.820 ;
        RECT 22.330 678.460 999.860 680.660 ;
        RECT 22.330 677.300 999.140 678.460 ;
        RECT 22.330 675.100 999.860 677.300 ;
        RECT 22.330 673.940 999.140 675.100 ;
        RECT 22.330 671.740 999.860 673.940 ;
        RECT 22.330 670.580 999.140 671.740 ;
        RECT 22.330 668.380 999.860 670.580 ;
        RECT 22.330 667.220 999.140 668.380 ;
        RECT 22.330 665.020 999.860 667.220 ;
        RECT 22.330 663.860 999.140 665.020 ;
        RECT 22.330 661.660 999.860 663.860 ;
        RECT 22.330 660.500 999.140 661.660 ;
        RECT 22.330 658.300 999.860 660.500 ;
        RECT 22.330 657.140 999.140 658.300 ;
        RECT 22.330 654.940 999.860 657.140 ;
        RECT 22.330 653.780 999.140 654.940 ;
        RECT 22.330 651.580 999.860 653.780 ;
        RECT 22.330 650.420 999.140 651.580 ;
        RECT 22.330 648.220 999.860 650.420 ;
        RECT 22.330 647.060 999.140 648.220 ;
        RECT 22.330 644.860 999.860 647.060 ;
        RECT 22.330 643.700 999.140 644.860 ;
        RECT 22.330 641.500 999.860 643.700 ;
        RECT 22.330 640.340 999.140 641.500 ;
        RECT 22.330 638.140 999.860 640.340 ;
        RECT 22.330 636.980 999.140 638.140 ;
        RECT 22.330 634.780 999.860 636.980 ;
        RECT 22.330 633.620 999.140 634.780 ;
        RECT 22.330 631.420 999.860 633.620 ;
        RECT 22.330 630.260 999.140 631.420 ;
        RECT 22.330 628.060 999.860 630.260 ;
        RECT 22.330 626.900 999.140 628.060 ;
        RECT 22.330 624.700 999.860 626.900 ;
        RECT 22.330 623.540 999.140 624.700 ;
        RECT 22.330 621.340 999.860 623.540 ;
        RECT 22.330 620.180 999.140 621.340 ;
        RECT 22.330 617.980 999.860 620.180 ;
        RECT 22.330 616.820 999.140 617.980 ;
        RECT 22.330 614.620 999.860 616.820 ;
        RECT 22.330 613.460 999.140 614.620 ;
        RECT 22.330 611.260 999.860 613.460 ;
        RECT 22.330 610.100 999.140 611.260 ;
        RECT 22.330 607.900 999.860 610.100 ;
        RECT 22.330 606.740 999.140 607.900 ;
        RECT 22.330 604.540 999.860 606.740 ;
        RECT 22.330 603.380 999.140 604.540 ;
        RECT 22.330 601.180 999.860 603.380 ;
        RECT 22.330 600.020 999.140 601.180 ;
        RECT 22.330 597.820 999.860 600.020 ;
        RECT 22.330 596.660 999.140 597.820 ;
        RECT 22.330 594.460 999.860 596.660 ;
        RECT 22.330 593.300 999.140 594.460 ;
        RECT 22.330 591.100 999.860 593.300 ;
        RECT 22.330 589.940 999.140 591.100 ;
        RECT 22.330 587.740 999.860 589.940 ;
        RECT 22.330 586.580 999.140 587.740 ;
        RECT 22.330 584.380 999.860 586.580 ;
        RECT 22.330 583.220 999.140 584.380 ;
        RECT 22.330 581.020 999.860 583.220 ;
        RECT 22.330 579.860 999.140 581.020 ;
        RECT 22.330 577.660 999.860 579.860 ;
        RECT 22.330 576.500 999.140 577.660 ;
        RECT 22.330 574.300 999.860 576.500 ;
        RECT 22.330 573.140 999.140 574.300 ;
        RECT 22.330 570.940 999.860 573.140 ;
        RECT 22.330 569.780 999.140 570.940 ;
        RECT 22.330 567.580 999.860 569.780 ;
        RECT 22.330 566.420 999.140 567.580 ;
        RECT 22.330 564.220 999.860 566.420 ;
        RECT 22.330 563.060 999.140 564.220 ;
        RECT 22.330 560.860 999.860 563.060 ;
        RECT 22.330 559.700 999.140 560.860 ;
        RECT 22.330 557.500 999.860 559.700 ;
        RECT 22.330 556.340 999.140 557.500 ;
        RECT 22.330 554.140 999.860 556.340 ;
        RECT 22.330 552.980 999.140 554.140 ;
        RECT 22.330 550.780 999.860 552.980 ;
        RECT 22.330 549.620 999.140 550.780 ;
        RECT 22.330 547.420 999.860 549.620 ;
        RECT 22.330 546.260 999.140 547.420 ;
        RECT 22.330 544.060 999.860 546.260 ;
        RECT 22.330 542.900 999.140 544.060 ;
        RECT 22.330 540.700 999.860 542.900 ;
        RECT 22.330 539.540 999.140 540.700 ;
        RECT 22.330 537.340 999.860 539.540 ;
        RECT 22.330 536.180 999.140 537.340 ;
        RECT 22.330 533.980 999.860 536.180 ;
        RECT 22.330 532.820 999.140 533.980 ;
        RECT 22.330 530.620 999.860 532.820 ;
        RECT 22.330 529.460 999.140 530.620 ;
        RECT 22.330 527.260 999.860 529.460 ;
        RECT 22.330 526.100 999.140 527.260 ;
        RECT 22.330 523.900 999.860 526.100 ;
        RECT 22.330 522.740 999.140 523.900 ;
        RECT 22.330 520.540 999.860 522.740 ;
        RECT 22.330 519.380 999.140 520.540 ;
        RECT 22.330 517.180 999.860 519.380 ;
        RECT 22.330 516.020 999.140 517.180 ;
        RECT 22.330 513.820 999.860 516.020 ;
        RECT 22.330 512.660 999.140 513.820 ;
        RECT 22.330 510.460 999.860 512.660 ;
        RECT 22.330 509.300 999.140 510.460 ;
        RECT 22.330 507.100 999.860 509.300 ;
        RECT 22.330 505.940 999.140 507.100 ;
        RECT 22.330 503.740 999.860 505.940 ;
        RECT 22.330 502.580 999.140 503.740 ;
        RECT 22.330 500.380 999.860 502.580 ;
        RECT 22.330 499.220 999.140 500.380 ;
        RECT 22.330 497.020 999.860 499.220 ;
        RECT 22.330 495.860 999.140 497.020 ;
        RECT 22.330 493.660 999.860 495.860 ;
        RECT 22.330 492.500 999.140 493.660 ;
        RECT 22.330 490.300 999.860 492.500 ;
        RECT 22.330 489.140 999.140 490.300 ;
        RECT 22.330 486.940 999.860 489.140 ;
        RECT 22.330 485.780 999.140 486.940 ;
        RECT 22.330 483.580 999.860 485.780 ;
        RECT 22.330 482.420 999.140 483.580 ;
        RECT 22.330 480.220 999.860 482.420 ;
        RECT 22.330 479.060 999.140 480.220 ;
        RECT 22.330 476.860 999.860 479.060 ;
        RECT 22.330 475.700 999.140 476.860 ;
        RECT 22.330 473.500 999.860 475.700 ;
        RECT 22.330 472.340 999.140 473.500 ;
        RECT 22.330 470.140 999.860 472.340 ;
        RECT 22.330 468.980 999.140 470.140 ;
        RECT 22.330 466.780 999.860 468.980 ;
        RECT 22.330 465.620 999.140 466.780 ;
        RECT 22.330 463.420 999.860 465.620 ;
        RECT 22.330 462.260 999.140 463.420 ;
        RECT 22.330 460.060 999.860 462.260 ;
        RECT 22.330 458.900 999.140 460.060 ;
        RECT 22.330 456.700 999.860 458.900 ;
        RECT 22.330 455.540 999.140 456.700 ;
        RECT 22.330 453.340 999.860 455.540 ;
        RECT 22.330 452.180 999.140 453.340 ;
        RECT 22.330 449.980 999.860 452.180 ;
        RECT 22.330 448.820 999.140 449.980 ;
        RECT 22.330 446.620 999.860 448.820 ;
        RECT 22.330 445.460 999.140 446.620 ;
        RECT 22.330 443.260 999.860 445.460 ;
        RECT 22.330 442.100 999.140 443.260 ;
        RECT 22.330 439.900 999.860 442.100 ;
        RECT 22.330 438.740 999.140 439.900 ;
        RECT 22.330 436.540 999.860 438.740 ;
        RECT 22.330 435.380 999.140 436.540 ;
        RECT 22.330 433.180 999.860 435.380 ;
        RECT 22.330 432.020 999.140 433.180 ;
        RECT 22.330 429.820 999.860 432.020 ;
        RECT 22.330 428.660 999.140 429.820 ;
        RECT 22.330 426.460 999.860 428.660 ;
        RECT 22.330 425.300 999.140 426.460 ;
        RECT 22.330 423.100 999.860 425.300 ;
        RECT 22.330 421.940 999.140 423.100 ;
        RECT 22.330 419.740 999.860 421.940 ;
        RECT 22.330 418.580 999.140 419.740 ;
        RECT 22.330 416.380 999.860 418.580 ;
        RECT 22.330 415.220 999.140 416.380 ;
        RECT 22.330 413.020 999.860 415.220 ;
        RECT 22.330 411.860 999.140 413.020 ;
        RECT 22.330 409.660 999.860 411.860 ;
        RECT 22.330 408.500 999.140 409.660 ;
        RECT 22.330 406.300 999.860 408.500 ;
        RECT 22.330 405.140 999.140 406.300 ;
        RECT 22.330 402.940 999.860 405.140 ;
        RECT 22.330 401.780 999.140 402.940 ;
        RECT 22.330 399.580 999.860 401.780 ;
        RECT 22.330 398.420 999.140 399.580 ;
        RECT 22.330 396.220 999.860 398.420 ;
        RECT 22.330 395.060 999.140 396.220 ;
        RECT 22.330 392.860 999.860 395.060 ;
        RECT 22.330 391.700 999.140 392.860 ;
        RECT 22.330 389.500 999.860 391.700 ;
        RECT 22.330 388.340 999.140 389.500 ;
        RECT 22.330 386.140 999.860 388.340 ;
        RECT 22.330 384.980 999.140 386.140 ;
        RECT 22.330 382.780 999.860 384.980 ;
        RECT 22.330 381.620 999.140 382.780 ;
        RECT 22.330 379.420 999.860 381.620 ;
        RECT 22.330 378.260 999.140 379.420 ;
        RECT 22.330 376.060 999.860 378.260 ;
        RECT 22.330 374.900 999.140 376.060 ;
        RECT 22.330 372.700 999.860 374.900 ;
        RECT 22.330 371.540 999.140 372.700 ;
        RECT 22.330 369.340 999.860 371.540 ;
        RECT 22.330 368.180 999.140 369.340 ;
        RECT 22.330 365.980 999.860 368.180 ;
        RECT 22.330 364.820 999.140 365.980 ;
        RECT 22.330 362.620 999.860 364.820 ;
        RECT 22.330 361.460 999.140 362.620 ;
        RECT 22.330 359.260 999.860 361.460 ;
        RECT 22.330 358.100 999.140 359.260 ;
        RECT 22.330 355.900 999.860 358.100 ;
        RECT 22.330 354.740 999.140 355.900 ;
        RECT 22.330 352.540 999.860 354.740 ;
        RECT 22.330 351.380 999.140 352.540 ;
        RECT 22.330 349.180 999.860 351.380 ;
        RECT 22.330 348.020 999.140 349.180 ;
        RECT 22.330 345.820 999.860 348.020 ;
        RECT 22.330 344.660 999.140 345.820 ;
        RECT 22.330 342.460 999.860 344.660 ;
        RECT 22.330 341.300 999.140 342.460 ;
        RECT 22.330 339.100 999.860 341.300 ;
        RECT 22.330 337.940 999.140 339.100 ;
        RECT 22.330 335.740 999.860 337.940 ;
        RECT 22.330 334.580 999.140 335.740 ;
        RECT 22.330 332.380 999.860 334.580 ;
        RECT 22.330 331.220 999.140 332.380 ;
        RECT 22.330 329.020 999.860 331.220 ;
        RECT 22.330 327.860 999.140 329.020 ;
        RECT 22.330 325.660 999.860 327.860 ;
        RECT 22.330 324.500 999.140 325.660 ;
        RECT 22.330 322.300 999.860 324.500 ;
        RECT 22.330 321.140 999.140 322.300 ;
        RECT 22.330 318.940 999.860 321.140 ;
        RECT 22.330 317.780 999.140 318.940 ;
        RECT 22.330 315.580 999.860 317.780 ;
        RECT 22.330 314.420 999.140 315.580 ;
        RECT 22.330 312.220 999.860 314.420 ;
        RECT 22.330 311.060 999.140 312.220 ;
        RECT 22.330 308.860 999.860 311.060 ;
        RECT 22.330 307.700 999.140 308.860 ;
        RECT 22.330 305.500 999.860 307.700 ;
        RECT 22.330 304.340 999.140 305.500 ;
        RECT 22.330 302.140 999.860 304.340 ;
        RECT 22.330 300.980 999.140 302.140 ;
        RECT 22.330 298.780 999.860 300.980 ;
        RECT 22.330 297.620 999.140 298.780 ;
        RECT 22.330 295.420 999.860 297.620 ;
        RECT 22.330 294.260 999.140 295.420 ;
        RECT 22.330 292.060 999.860 294.260 ;
        RECT 22.330 290.900 999.140 292.060 ;
        RECT 22.330 288.700 999.860 290.900 ;
        RECT 22.330 287.540 999.140 288.700 ;
        RECT 22.330 285.340 999.860 287.540 ;
        RECT 22.330 284.180 999.140 285.340 ;
        RECT 22.330 281.980 999.860 284.180 ;
        RECT 22.330 280.820 999.140 281.980 ;
        RECT 22.330 278.620 999.860 280.820 ;
        RECT 22.330 277.460 999.140 278.620 ;
        RECT 22.330 275.260 999.860 277.460 ;
        RECT 22.330 274.100 999.140 275.260 ;
        RECT 22.330 271.900 999.860 274.100 ;
        RECT 22.330 270.740 999.140 271.900 ;
        RECT 22.330 268.540 999.860 270.740 ;
        RECT 22.330 267.380 999.140 268.540 ;
        RECT 22.330 265.180 999.860 267.380 ;
        RECT 22.330 264.020 999.140 265.180 ;
        RECT 22.330 261.820 999.860 264.020 ;
        RECT 22.330 260.660 999.140 261.820 ;
        RECT 22.330 258.460 999.860 260.660 ;
        RECT 22.330 257.300 999.140 258.460 ;
        RECT 22.330 255.100 999.860 257.300 ;
        RECT 22.330 253.940 999.140 255.100 ;
        RECT 22.330 251.740 999.860 253.940 ;
        RECT 22.330 250.580 999.140 251.740 ;
        RECT 22.330 248.380 999.860 250.580 ;
        RECT 22.330 247.220 999.140 248.380 ;
        RECT 22.330 245.020 999.860 247.220 ;
        RECT 22.330 243.860 999.140 245.020 ;
        RECT 22.330 241.660 999.860 243.860 ;
        RECT 22.330 240.500 999.140 241.660 ;
        RECT 22.330 238.300 999.860 240.500 ;
        RECT 22.330 237.140 999.140 238.300 ;
        RECT 22.330 234.940 999.860 237.140 ;
        RECT 22.330 233.780 999.140 234.940 ;
        RECT 22.330 231.580 999.860 233.780 ;
        RECT 22.330 230.420 999.140 231.580 ;
        RECT 22.330 228.220 999.860 230.420 ;
        RECT 22.330 227.060 999.140 228.220 ;
        RECT 22.330 224.860 999.860 227.060 ;
        RECT 22.330 223.700 999.140 224.860 ;
        RECT 22.330 221.500 999.860 223.700 ;
        RECT 22.330 220.340 999.140 221.500 ;
        RECT 22.330 218.140 999.860 220.340 ;
        RECT 22.330 216.980 999.140 218.140 ;
        RECT 22.330 214.780 999.860 216.980 ;
        RECT 22.330 213.620 999.140 214.780 ;
        RECT 22.330 211.420 999.860 213.620 ;
        RECT 22.330 210.260 999.140 211.420 ;
        RECT 22.330 208.060 999.860 210.260 ;
        RECT 22.330 206.900 999.140 208.060 ;
        RECT 22.330 204.700 999.860 206.900 ;
        RECT 22.330 203.540 999.140 204.700 ;
        RECT 22.330 201.340 999.860 203.540 ;
        RECT 22.330 200.180 999.140 201.340 ;
        RECT 22.330 197.980 999.860 200.180 ;
        RECT 22.330 196.820 999.140 197.980 ;
        RECT 22.330 194.620 999.860 196.820 ;
        RECT 22.330 193.460 999.140 194.620 ;
        RECT 22.330 191.260 999.860 193.460 ;
        RECT 22.330 190.100 999.140 191.260 ;
        RECT 22.330 187.900 999.860 190.100 ;
        RECT 22.330 186.740 999.140 187.900 ;
        RECT 22.330 184.540 999.860 186.740 ;
        RECT 22.330 183.380 999.140 184.540 ;
        RECT 22.330 181.180 999.860 183.380 ;
        RECT 22.330 180.020 999.140 181.180 ;
        RECT 22.330 177.820 999.860 180.020 ;
        RECT 22.330 176.660 999.140 177.820 ;
        RECT 22.330 174.460 999.860 176.660 ;
        RECT 22.330 173.300 999.140 174.460 ;
        RECT 22.330 171.100 999.860 173.300 ;
        RECT 22.330 169.940 999.140 171.100 ;
        RECT 22.330 167.740 999.860 169.940 ;
        RECT 22.330 166.580 999.140 167.740 ;
        RECT 22.330 164.380 999.860 166.580 ;
        RECT 22.330 163.220 999.140 164.380 ;
        RECT 22.330 161.020 999.860 163.220 ;
        RECT 22.330 159.860 999.140 161.020 ;
        RECT 22.330 157.660 999.860 159.860 ;
        RECT 22.330 156.500 999.140 157.660 ;
        RECT 22.330 154.300 999.860 156.500 ;
        RECT 22.330 153.140 999.140 154.300 ;
        RECT 22.330 150.940 999.860 153.140 ;
        RECT 22.330 149.780 999.140 150.940 ;
        RECT 22.330 147.580 999.860 149.780 ;
        RECT 22.330 146.420 999.140 147.580 ;
        RECT 22.330 144.220 999.860 146.420 ;
        RECT 22.330 143.060 999.140 144.220 ;
        RECT 22.330 140.860 999.860 143.060 ;
        RECT 22.330 139.700 999.140 140.860 ;
        RECT 22.330 137.500 999.860 139.700 ;
        RECT 22.330 136.340 999.140 137.500 ;
        RECT 22.330 134.140 999.860 136.340 ;
        RECT 22.330 132.980 999.140 134.140 ;
        RECT 22.330 130.780 999.860 132.980 ;
        RECT 22.330 129.620 999.140 130.780 ;
        RECT 22.330 127.420 999.860 129.620 ;
        RECT 22.330 126.260 999.140 127.420 ;
        RECT 22.330 124.060 999.860 126.260 ;
        RECT 22.330 122.900 999.140 124.060 ;
        RECT 22.330 120.700 999.860 122.900 ;
        RECT 22.330 119.540 999.140 120.700 ;
        RECT 22.330 10.780 999.860 119.540 ;
      LAYER Metal4 ;
        RECT 160.300 984.520 999.460 999.510 ;
        RECT 160.300 108.170 175.540 984.520 ;
        RECT 177.740 108.170 178.840 984.520 ;
        RECT 181.040 108.170 329.140 984.520 ;
        RECT 331.340 108.170 332.440 984.520 ;
        RECT 334.640 108.170 482.740 984.520 ;
        RECT 484.940 108.170 486.040 984.520 ;
        RECT 488.240 108.170 636.340 984.520 ;
        RECT 638.540 108.170 639.640 984.520 ;
        RECT 641.840 108.170 789.940 984.520 ;
        RECT 792.140 108.170 793.240 984.520 ;
        RECT 795.440 108.170 943.540 984.520 ;
        RECT 945.740 108.170 946.840 984.520 ;
        RECT 949.040 108.170 999.460 984.520 ;
      LAYER Metal5 ;
        RECT 160.220 956.110 998.980 991.570 ;
        RECT 993.480 953.310 998.980 956.110 ;
        RECT 160.220 952.810 998.980 953.310 ;
        RECT 993.480 950.010 998.980 952.810 ;
        RECT 160.220 802.930 998.980 950.010 ;
        RECT 993.480 800.130 998.980 802.930 ;
        RECT 160.220 799.630 998.980 800.130 ;
        RECT 993.480 796.830 998.980 799.630 ;
        RECT 160.220 649.750 998.980 796.830 ;
        RECT 993.480 646.950 998.980 649.750 ;
        RECT 160.220 646.450 998.980 646.950 ;
        RECT 993.480 643.650 998.980 646.450 ;
        RECT 160.220 496.570 998.980 643.650 ;
        RECT 993.480 493.770 998.980 496.570 ;
        RECT 160.220 493.270 998.980 493.770 ;
        RECT 993.480 490.470 998.980 493.270 ;
        RECT 160.220 343.390 998.980 490.470 ;
        RECT 993.480 340.590 998.980 343.390 ;
        RECT 160.220 340.090 998.980 340.590 ;
        RECT 993.480 337.290 998.980 340.090 ;
        RECT 160.220 190.210 998.980 337.290 ;
        RECT 993.480 187.410 998.980 190.210 ;
        RECT 160.220 186.910 998.980 187.410 ;
        RECT 993.480 184.110 998.980 186.910 ;
        RECT 160.220 128.030 998.980 184.110 ;
  END
END ibex_top
END LIBRARY

